VERSION 5.7 ;
  NOWIREEXTENSIONATPIN ON ;
  DIVIDERCHAR "/" ;
  BUSBITCHARS "[]" ;
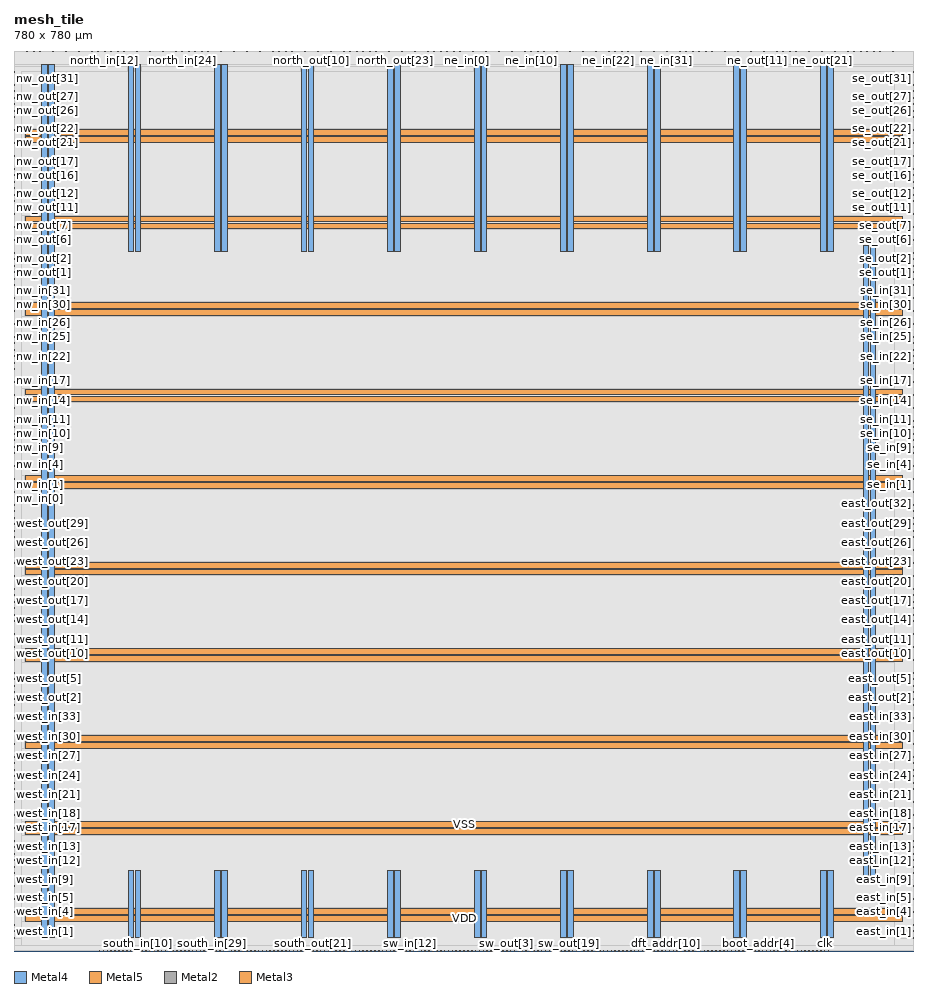
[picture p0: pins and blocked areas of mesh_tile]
MACRO mesh_tile
  CLASS BLOCK ;
  FOREIGN mesh_tile ;
  ORIGIN 0.000 0.000 ;
  SIZE 780.000 BY 780.000 ;
  PIN VDD
    DIRECTION INOUT ;
    USE POWER ;
    PORT
      LAYER Metal4 ;
        RECT 23.900 11.460 28.900 768.620 ;
    END
    PORT
      LAYER Metal4 ;
        RECT 98.900 11.460 103.900 69.720 ;
    END
    PORT
      LAYER Metal4 ;
        RECT 98.900 606.090 103.900 768.620 ;
    END
    PORT
      LAYER Metal4 ;
        RECT 173.900 11.460 178.900 69.720 ;
    END
    PORT
      LAYER Metal4 ;
        RECT 173.900 606.090 178.900 768.620 ;
    END
    PORT
      LAYER Metal4 ;
        RECT 248.900 11.460 253.900 69.720 ;
    END
    PORT
      LAYER Metal4 ;
        RECT 248.900 606.090 253.900 768.620 ;
    END
    PORT
      LAYER Metal4 ;
        RECT 323.900 11.460 328.900 69.720 ;
    END
    PORT
      LAYER Metal4 ;
        RECT 323.900 606.090 328.900 768.620 ;
    END
    PORT
      LAYER Metal4 ;
        RECT 398.900 11.460 403.900 69.720 ;
    END
    PORT
      LAYER Metal4 ;
        RECT 398.900 606.090 403.900 768.620 ;
    END
    PORT
      LAYER Metal4 ;
        RECT 473.900 11.460 478.900 69.720 ;
    END
    PORT
      LAYER Metal4 ;
        RECT 473.900 606.090 478.900 768.620 ;
    END
    PORT
      LAYER Metal4 ;
        RECT 548.900 11.460 553.900 69.720 ;
    END
    PORT
      LAYER Metal4 ;
        RECT 548.900 606.090 553.900 768.620 ;
    END
    PORT
      LAYER Metal4 ;
        RECT 623.900 11.460 628.900 69.720 ;
    END
    PORT
      LAYER Metal4 ;
        RECT 623.900 606.090 628.900 768.620 ;
    END
    PORT
      LAYER Metal4 ;
        RECT 698.900 11.460 703.900 69.720 ;
    END
    PORT
      LAYER Metal4 ;
        RECT 698.900 606.090 703.900 768.620 ;
    END
    PORT
      LAYER Metal5 ;
        RECT 10.080 25.910 770.000 30.910 ;
    END
    PORT
      LAYER Metal5 ;
        RECT 10.080 100.910 770.000 105.910 ;
    END
    PORT
      LAYER Metal5 ;
        RECT 10.080 175.910 770.000 180.910 ;
    END
    PORT
      LAYER Metal5 ;
        RECT 10.080 250.910 770.000 255.910 ;
    END
    PORT
      LAYER Metal5 ;
        RECT 10.080 325.910 770.000 330.910 ;
    END
    PORT
      LAYER Metal5 ;
        RECT 10.080 400.910 770.000 405.910 ;
    END
    PORT
      LAYER Metal5 ;
        RECT 10.080 475.910 770.000 480.910 ;
    END
    PORT
      LAYER Metal5 ;
        RECT 10.080 550.910 770.000 555.910 ;
    END
    PORT
      LAYER Metal5 ;
        RECT 10.080 625.910 770.000 630.910 ;
    END
    PORT
      LAYER Metal5 ;
        RECT 10.080 700.910 770.000 705.910 ;
    END
    PORT
      LAYER Metal4 ;
        RECT 735.860 62.420 740.860 611.820 ;
    END
  END VDD
  PIN VSS
    DIRECTION INOUT ;
    USE GROUND ;
    PORT
      LAYER Metal4 ;
        RECT 29.900 11.460 34.900 768.620 ;
    END
    PORT
      LAYER Metal4 ;
        RECT 104.900 11.460 109.900 69.720 ;
    END
    PORT
      LAYER Metal4 ;
        RECT 104.900 606.090 109.900 768.620 ;
    END
    PORT
      LAYER Metal4 ;
        RECT 179.900 11.460 184.900 69.720 ;
    END
    PORT
      LAYER Metal4 ;
        RECT 179.900 606.090 184.900 768.620 ;
    END
    PORT
      LAYER Metal4 ;
        RECT 254.900 11.460 259.900 69.720 ;
    END
    PORT
      LAYER Metal4 ;
        RECT 254.900 606.090 259.900 768.620 ;
    END
    PORT
      LAYER Metal4 ;
        RECT 329.900 11.460 334.900 69.720 ;
    END
    PORT
      LAYER Metal4 ;
        RECT 329.900 606.090 334.900 768.620 ;
    END
    PORT
      LAYER Metal4 ;
        RECT 404.900 11.460 409.900 69.720 ;
    END
    PORT
      LAYER Metal4 ;
        RECT 404.900 606.090 409.900 768.620 ;
    END
    PORT
      LAYER Metal4 ;
        RECT 479.900 11.460 484.900 69.720 ;
    END
    PORT
      LAYER Metal4 ;
        RECT 479.900 606.090 484.900 768.620 ;
    END
    PORT
      LAYER Metal4 ;
        RECT 554.900 11.460 559.900 69.720 ;
    END
    PORT
      LAYER Metal4 ;
        RECT 554.900 606.090 559.900 768.620 ;
    END
    PORT
      LAYER Metal4 ;
        RECT 629.900 11.460 634.900 69.720 ;
    END
    PORT
      LAYER Metal4 ;
        RECT 629.900 606.090 634.900 768.620 ;
    END
    PORT
      LAYER Metal4 ;
        RECT 704.900 11.460 709.900 69.720 ;
    END
    PORT
      LAYER Metal4 ;
        RECT 704.900 606.090 709.900 768.620 ;
    END
    PORT
      LAYER Metal5 ;
        RECT 10.080 31.910 770.000 36.910 ;
    END
    PORT
      LAYER Metal5 ;
        RECT 10.080 106.910 770.000 111.910 ;
    END
    PORT
      LAYER Metal5 ;
        RECT 10.080 181.910 770.000 186.910 ;
    END
    PORT
      LAYER Metal5 ;
        RECT 10.080 256.910 770.000 261.910 ;
    END
    PORT
      LAYER Metal5 ;
        RECT 10.080 331.910 770.000 336.910 ;
    END
    PORT
      LAYER Metal5 ;
        RECT 10.080 406.910 770.000 411.910 ;
    END
    PORT
      LAYER Metal5 ;
        RECT 10.080 481.910 770.000 486.910 ;
    END
    PORT
      LAYER Metal5 ;
        RECT 10.080 556.910 770.000 561.910 ;
    END
    PORT
      LAYER Metal5 ;
        RECT 10.080 631.910 770.000 636.910 ;
    END
    PORT
      LAYER Metal5 ;
        RECT 10.080 706.910 770.000 711.910 ;
    END
    PORT
      LAYER Metal4 ;
        RECT 742.020 62.420 747.020 611.820 ;
    END
  END VSS
  PIN boot_addr[0]
    DIRECTION INPUT ;
    USE SIGNAL ;
    ANTENNAGATEAREA 2.665600 ;
    PORT
      LAYER Metal2 ;
        RECT 631.680 0.000 632.240 0.560 ;
    END
  END boot_addr[0]
  PIN boot_addr[10]
    DIRECTION INPUT ;
    USE SIGNAL ;
    ANTENNAGATEAREA 2.665600 ;
    PORT
      LAYER Metal2 ;
        RECT 665.280 0.000 665.840 0.560 ;
    END
  END boot_addr[10]
  PIN boot_addr[1]
    DIRECTION INPUT ;
    USE SIGNAL ;
    ANTENNAGATEAREA 2.665600 ;
    PORT
      LAYER Metal2 ;
        RECT 635.040 0.000 635.600 0.560 ;
    END
  END boot_addr[1]
  PIN boot_addr[2]
    DIRECTION INPUT ;
    USE SIGNAL ;
    ANTENNAGATEAREA 2.665600 ;
    PORT
      LAYER Metal2 ;
        RECT 638.400 0.000 638.960 0.560 ;
    END
  END boot_addr[2]
  PIN boot_addr[3]
    DIRECTION INPUT ;
    USE SIGNAL ;
    ANTENNAGATEAREA 2.665600 ;
    PORT
      LAYER Metal2 ;
        RECT 641.760 0.000 642.320 0.560 ;
    END
  END boot_addr[3]
  PIN boot_addr[4]
    DIRECTION INPUT ;
    USE SIGNAL ;
    ANTENNAGATEAREA 2.665600 ;
    PORT
      LAYER Metal2 ;
        RECT 645.120 0.000 645.680 0.560 ;
    END
  END boot_addr[4]
  PIN boot_addr[5]
    DIRECTION INPUT ;
    USE SIGNAL ;
    ANTENNAGATEAREA 2.665600 ;
    PORT
      LAYER Metal2 ;
        RECT 648.480 0.000 649.040 0.560 ;
    END
  END boot_addr[5]
  PIN boot_addr[6]
    DIRECTION INPUT ;
    USE SIGNAL ;
    ANTENNAGATEAREA 2.665600 ;
    PORT
      LAYER Metal2 ;
        RECT 651.840 0.000 652.400 0.560 ;
    END
  END boot_addr[6]
  PIN boot_addr[7]
    DIRECTION INPUT ;
    USE SIGNAL ;
    ANTENNAGATEAREA 2.665600 ;
    PORT
      LAYER Metal2 ;
        RECT 655.200 0.000 655.760 0.560 ;
    END
  END boot_addr[7]
  PIN boot_addr[8]
    DIRECTION INPUT ;
    USE SIGNAL ;
    ANTENNAGATEAREA 2.665600 ;
    PORT
      LAYER Metal2 ;
        RECT 658.560 0.000 659.120 0.560 ;
    END
  END boot_addr[8]
  PIN boot_addr[9]
    DIRECTION INPUT ;
    USE SIGNAL ;
    ANTENNAGATEAREA 2.665600 ;
    PORT
      LAYER Metal2 ;
        RECT 661.920 0.000 662.480 0.560 ;
    END
  END boot_addr[9]
  PIN boot_data[0]
    DIRECTION INPUT ;
    USE SIGNAL ;
    ANTENNAGATEAREA 2.665600 ;
    PORT
      LAYER Metal2 ;
        RECT 668.640 0.000 669.200 0.560 ;
    END
  END boot_data[0]
  PIN boot_data[1]
    DIRECTION INPUT ;
    USE SIGNAL ;
    ANTENNAGATEAREA 2.665600 ;
    PORT
      LAYER Metal2 ;
        RECT 672.000 0.000 672.560 0.560 ;
    END
  END boot_data[1]
  PIN boot_data[2]
    DIRECTION INPUT ;
    USE SIGNAL ;
    ANTENNAGATEAREA 2.665600 ;
    PORT
      LAYER Metal2 ;
        RECT 675.360 0.000 675.920 0.560 ;
    END
  END boot_data[2]
  PIN boot_data[3]
    DIRECTION INPUT ;
    USE SIGNAL ;
    ANTENNAGATEAREA 2.665600 ;
    PORT
      LAYER Metal2 ;
        RECT 678.720 0.000 679.280 0.560 ;
    END
  END boot_data[3]
  PIN boot_data[4]
    DIRECTION INPUT ;
    USE SIGNAL ;
    ANTENNAGATEAREA 2.665600 ;
    PORT
      LAYER Metal2 ;
        RECT 682.080 0.000 682.640 0.560 ;
    END
  END boot_data[4]
  PIN boot_data[5]
    DIRECTION INPUT ;
    USE SIGNAL ;
    ANTENNAGATEAREA 2.665600 ;
    PORT
      LAYER Metal2 ;
        RECT 685.440 0.000 686.000 0.560 ;
    END
  END boot_data[5]
  PIN boot_data[6]
    DIRECTION INPUT ;
    USE SIGNAL ;
    ANTENNAGATEAREA 2.665600 ;
    PORT
      LAYER Metal2 ;
        RECT 688.800 0.000 689.360 0.560 ;
    END
  END boot_data[6]
  PIN boot_data[7]
    DIRECTION INPUT ;
    USE SIGNAL ;
    ANTENNAGATEAREA 2.665600 ;
    PORT
      LAYER Metal2 ;
        RECT 692.160 0.000 692.720 0.560 ;
    END
  END boot_data[7]
  PIN boot_mode
    DIRECTION INPUT ;
    USE SIGNAL ;
    ANTENNAGATEAREA 2.665600 ;
    PORT
      LAYER Metal2 ;
        RECT 695.520 0.000 696.080 0.560 ;
    END
  END boot_mode
  PIN boot_wen
    DIRECTION INPUT ;
    USE SIGNAL ;
    ANTENNAGATEAREA 2.665600 ;
    PORT
      LAYER Metal2 ;
        RECT 698.880 0.000 699.440 0.560 ;
    END
  END boot_wen
  PIN clk
    DIRECTION INPUT ;
    USE SIGNAL ;
    ANTENNAGATEAREA 4.704000 ;
    PORT
      LAYER Metal2 ;
        RECT 702.240 0.000 702.800 0.560 ;
    END
  END clk
  PIN dft_addr[0]
    DIRECTION INPUT ;
    USE SIGNAL ;
    ANTENNAGATEAREA 2.665600 ;
    PORT
      LAYER Metal2 ;
        RECT 530.880 0.000 531.440 0.560 ;
    END
  END dft_addr[0]
  PIN dft_addr[10]
    DIRECTION INPUT ;
    USE SIGNAL ;
    ANTENNAGATEAREA 2.665600 ;
    PORT
      LAYER Metal2 ;
        RECT 564.480 0.000 565.040 0.560 ;
    END
  END dft_addr[10]
  PIN dft_addr[1]
    DIRECTION INPUT ;
    USE SIGNAL ;
    ANTENNAGATEAREA 2.665600 ;
    PORT
      LAYER Metal2 ;
        RECT 534.240 0.000 534.800 0.560 ;
    END
  END dft_addr[1]
  PIN dft_addr[2]
    DIRECTION INPUT ;
    USE SIGNAL ;
    ANTENNAGATEAREA 2.665600 ;
    PORT
      LAYER Metal2 ;
        RECT 537.600 0.000 538.160 0.560 ;
    END
  END dft_addr[2]
  PIN dft_addr[3]
    DIRECTION INPUT ;
    USE SIGNAL ;
    ANTENNAGATEAREA 2.665600 ;
    PORT
      LAYER Metal2 ;
        RECT 540.960 0.000 541.520 0.560 ;
    END
  END dft_addr[3]
  PIN dft_addr[4]
    DIRECTION INPUT ;
    USE SIGNAL ;
    ANTENNAGATEAREA 2.665600 ;
    PORT
      LAYER Metal2 ;
        RECT 544.320 0.000 544.880 0.560 ;
    END
  END dft_addr[4]
  PIN dft_addr[5]
    DIRECTION INPUT ;
    USE SIGNAL ;
    ANTENNAGATEAREA 2.665600 ;
    PORT
      LAYER Metal2 ;
        RECT 547.680 0.000 548.240 0.560 ;
    END
  END dft_addr[5]
  PIN dft_addr[6]
    DIRECTION INPUT ;
    USE SIGNAL ;
    ANTENNAGATEAREA 2.665600 ;
    PORT
      LAYER Metal2 ;
        RECT 551.040 0.000 551.600 0.560 ;
    END
  END dft_addr[6]
  PIN dft_addr[7]
    DIRECTION INPUT ;
    USE SIGNAL ;
    ANTENNAGATEAREA 2.665600 ;
    PORT
      LAYER Metal2 ;
        RECT 554.400 0.000 554.960 0.560 ;
    END
  END dft_addr[7]
  PIN dft_addr[8]
    DIRECTION INPUT ;
    USE SIGNAL ;
    ANTENNAGATEAREA 2.665600 ;
    PORT
      LAYER Metal2 ;
        RECT 557.760 0.000 558.320 0.560 ;
    END
  END dft_addr[8]
  PIN dft_addr[9]
    DIRECTION INPUT ;
    USE SIGNAL ;
    ANTENNAGATEAREA 2.665600 ;
    PORT
      LAYER Metal2 ;
        RECT 561.120 0.000 561.680 0.560 ;
    END
  END dft_addr[9]
  PIN dft_ce
    DIRECTION INPUT ;
    USE SIGNAL ;
    ANTENNAGATEAREA 2.665600 ;
    PORT
      LAYER Metal2 ;
        RECT 567.840 0.000 568.400 0.560 ;
    END
  END dft_ce
  PIN dft_mode
    DIRECTION INPUT ;
    USE SIGNAL ;
    ANTENNAGATEAREA 2.665600 ;
    PORT
      LAYER Metal2 ;
        RECT 571.200 0.000 571.760 0.560 ;
    END
  END dft_mode
  PIN dft_rdata[0]
    DIRECTION OUTPUT ;
    USE SIGNAL ;
    ANTENNADIFFAREA 7.461300 ;
    PORT
      LAYER Metal2 ;
        RECT 574.560 0.000 575.120 0.560 ;
    END
  END dft_rdata[0]
  PIN dft_rdata[1]
    DIRECTION OUTPUT ;
    USE SIGNAL ;
    ANTENNADIFFAREA 7.461300 ;
    PORT
      LAYER Metal2 ;
        RECT 577.920 0.000 578.480 0.560 ;
    END
  END dft_rdata[1]
  PIN dft_rdata[2]
    DIRECTION OUTPUT ;
    USE SIGNAL ;
    ANTENNADIFFAREA 7.461300 ;
    PORT
      LAYER Metal2 ;
        RECT 581.280 0.000 581.840 0.560 ;
    END
  END dft_rdata[2]
  PIN dft_rdata[3]
    DIRECTION OUTPUT ;
    USE SIGNAL ;
    ANTENNADIFFAREA 7.461300 ;
    PORT
      LAYER Metal2 ;
        RECT 584.640 0.000 585.200 0.560 ;
    END
  END dft_rdata[3]
  PIN dft_rdata[4]
    DIRECTION OUTPUT ;
    USE SIGNAL ;
    ANTENNADIFFAREA 7.461300 ;
    PORT
      LAYER Metal2 ;
        RECT 588.000 0.000 588.560 0.560 ;
    END
  END dft_rdata[4]
  PIN dft_rdata[5]
    DIRECTION OUTPUT ;
    USE SIGNAL ;
    ANTENNADIFFAREA 7.461300 ;
    PORT
      LAYER Metal2 ;
        RECT 591.360 0.000 591.920 0.560 ;
    END
  END dft_rdata[5]
  PIN dft_rdata[6]
    DIRECTION OUTPUT ;
    USE SIGNAL ;
    ANTENNADIFFAREA 7.461300 ;
    PORT
      LAYER Metal2 ;
        RECT 594.720 0.000 595.280 0.560 ;
    END
  END dft_rdata[6]
  PIN dft_rdata[7]
    DIRECTION OUTPUT ;
    USE SIGNAL ;
    ANTENNADIFFAREA 7.461300 ;
    PORT
      LAYER Metal2 ;
        RECT 598.080 0.000 598.640 0.560 ;
    END
  END dft_rdata[7]
  PIN dft_wdata[0]
    DIRECTION INPUT ;
    USE SIGNAL ;
    ANTENNAGATEAREA 2.665600 ;
    PORT
      LAYER Metal2 ;
        RECT 601.440 0.000 602.000 0.560 ;
    END
  END dft_wdata[0]
  PIN dft_wdata[1]
    DIRECTION INPUT ;
    USE SIGNAL ;
    ANTENNAGATEAREA 2.665600 ;
    PORT
      LAYER Metal2 ;
        RECT 604.800 0.000 605.360 0.560 ;
    END
  END dft_wdata[1]
  PIN dft_wdata[2]
    DIRECTION INPUT ;
    USE SIGNAL ;
    ANTENNAGATEAREA 2.665600 ;
    PORT
      LAYER Metal2 ;
        RECT 608.160 0.000 608.720 0.560 ;
    END
  END dft_wdata[2]
  PIN dft_wdata[3]
    DIRECTION INPUT ;
    USE SIGNAL ;
    ANTENNAGATEAREA 2.665600 ;
    PORT
      LAYER Metal2 ;
        RECT 611.520 0.000 612.080 0.560 ;
    END
  END dft_wdata[3]
  PIN dft_wdata[4]
    DIRECTION INPUT ;
    USE SIGNAL ;
    ANTENNAGATEAREA 2.665600 ;
    PORT
      LAYER Metal2 ;
        RECT 614.880 0.000 615.440 0.560 ;
    END
  END dft_wdata[4]
  PIN dft_wdata[5]
    DIRECTION INPUT ;
    USE SIGNAL ;
    ANTENNAGATEAREA 2.665600 ;
    PORT
      LAYER Metal2 ;
        RECT 618.240 0.000 618.800 0.560 ;
    END
  END dft_wdata[5]
  PIN dft_wdata[6]
    DIRECTION INPUT ;
    USE SIGNAL ;
    ANTENNAGATEAREA 2.665600 ;
    PORT
      LAYER Metal2 ;
        RECT 621.600 0.000 622.160 0.560 ;
    END
  END dft_wdata[6]
  PIN dft_wdata[7]
    DIRECTION INPUT ;
    USE SIGNAL ;
    ANTENNAGATEAREA 2.665600 ;
    PORT
      LAYER Metal2 ;
        RECT 624.960 0.000 625.520 0.560 ;
    END
  END dft_wdata[7]
  PIN dft_we
    DIRECTION INPUT ;
    USE SIGNAL ;
    ANTENNAGATEAREA 2.665600 ;
    PORT
      LAYER Metal2 ;
        RECT 628.320 0.000 628.880 0.560 ;
    END
  END dft_we
  PIN east_in[0]
    DIRECTION INPUT ;
    USE SIGNAL ;
    ANTENNAGATEAREA 2.665600 ;
    PORT
      LAYER Metal3 ;
        RECT 779.440 11.200 780.000 11.760 ;
    END
  END east_in[0]
  PIN east_in[10]
    DIRECTION INPUT ;
    USE SIGNAL ;
    ANTENNAGATEAREA 2.665600 ;
    PORT
      LAYER Metal3 ;
        RECT 779.440 67.200 780.000 67.760 ;
    END
  END east_in[10]
  PIN east_in[11]
    DIRECTION INPUT ;
    USE SIGNAL ;
    ANTENNAGATEAREA 2.665600 ;
    PORT
      LAYER Metal3 ;
        RECT 779.440 72.800 780.000 73.360 ;
    END
  END east_in[11]
  PIN east_in[12]
    DIRECTION INPUT ;
    USE SIGNAL ;
    ANTENNAGATEAREA 2.665600 ;
    PORT
      LAYER Metal3 ;
        RECT 779.440 78.400 780.000 78.960 ;
    END
  END east_in[12]
  PIN east_in[13]
    DIRECTION INPUT ;
    USE SIGNAL ;
    ANTENNAGATEAREA 2.665600 ;
    PORT
      LAYER Metal3 ;
        RECT 779.440 84.000 780.000 84.560 ;
    END
  END east_in[13]
  PIN east_in[14]
    DIRECTION INPUT ;
    USE SIGNAL ;
    ANTENNAGATEAREA 2.665600 ;
    PORT
      LAYER Metal3 ;
        RECT 779.440 89.600 780.000 90.160 ;
    END
  END east_in[14]
  PIN east_in[15]
    DIRECTION INPUT ;
    USE SIGNAL ;
    ANTENNAGATEAREA 2.665600 ;
    PORT
      LAYER Metal3 ;
        RECT 779.440 95.200 780.000 95.760 ;
    END
  END east_in[15]
  PIN east_in[16]
    DIRECTION INPUT ;
    USE SIGNAL ;
    ANTENNAGATEAREA 2.665600 ;
    PORT
      LAYER Metal3 ;
        RECT 779.440 100.800 780.000 101.360 ;
    END
  END east_in[16]
  PIN east_in[17]
    DIRECTION INPUT ;
    USE SIGNAL ;
    ANTENNAGATEAREA 2.665600 ;
    PORT
      LAYER Metal3 ;
        RECT 779.440 106.400 780.000 106.960 ;
    END
  END east_in[17]
  PIN east_in[18]
    DIRECTION INPUT ;
    USE SIGNAL ;
    ANTENNAGATEAREA 2.665600 ;
    PORT
      LAYER Metal3 ;
        RECT 779.440 112.000 780.000 112.560 ;
    END
  END east_in[18]
  PIN east_in[19]
    DIRECTION INPUT ;
    USE SIGNAL ;
    ANTENNAGATEAREA 2.665600 ;
    PORT
      LAYER Metal3 ;
        RECT 779.440 117.600 780.000 118.160 ;
    END
  END east_in[19]
  PIN east_in[1]
    DIRECTION INPUT ;
    USE SIGNAL ;
    ANTENNAGATEAREA 2.665600 ;
    PORT
      LAYER Metal3 ;
        RECT 779.440 16.800 780.000 17.360 ;
    END
  END east_in[1]
  PIN east_in[20]
    DIRECTION INPUT ;
    USE SIGNAL ;
    ANTENNAGATEAREA 2.665600 ;
    PORT
      LAYER Metal3 ;
        RECT 779.440 123.200 780.000 123.760 ;
    END
  END east_in[20]
  PIN east_in[21]
    DIRECTION INPUT ;
    USE SIGNAL ;
    ANTENNAGATEAREA 2.665600 ;
    PORT
      LAYER Metal3 ;
        RECT 779.440 128.800 780.000 129.360 ;
    END
  END east_in[21]
  PIN east_in[22]
    DIRECTION INPUT ;
    USE SIGNAL ;
    ANTENNAGATEAREA 2.665600 ;
    PORT
      LAYER Metal3 ;
        RECT 779.440 134.400 780.000 134.960 ;
    END
  END east_in[22]
  PIN east_in[23]
    DIRECTION INPUT ;
    USE SIGNAL ;
    ANTENNAGATEAREA 2.665600 ;
    PORT
      LAYER Metal3 ;
        RECT 779.440 140.000 780.000 140.560 ;
    END
  END east_in[23]
  PIN east_in[24]
    DIRECTION INPUT ;
    USE SIGNAL ;
    ANTENNAGATEAREA 2.665600 ;
    PORT
      LAYER Metal3 ;
        RECT 779.440 145.600 780.000 146.160 ;
    END
  END east_in[24]
  PIN east_in[25]
    DIRECTION INPUT ;
    USE SIGNAL ;
    ANTENNAGATEAREA 2.665600 ;
    PORT
      LAYER Metal3 ;
        RECT 779.440 151.200 780.000 151.760 ;
    END
  END east_in[25]
  PIN east_in[26]
    DIRECTION INPUT ;
    USE SIGNAL ;
    ANTENNAGATEAREA 2.665600 ;
    PORT
      LAYER Metal3 ;
        RECT 779.440 156.800 780.000 157.360 ;
    END
  END east_in[26]
  PIN east_in[27]
    DIRECTION INPUT ;
    USE SIGNAL ;
    ANTENNAGATEAREA 2.665600 ;
    PORT
      LAYER Metal3 ;
        RECT 779.440 162.400 780.000 162.960 ;
    END
  END east_in[27]
  PIN east_in[28]
    DIRECTION INPUT ;
    USE SIGNAL ;
    ANTENNAGATEAREA 2.665600 ;
    PORT
      LAYER Metal3 ;
        RECT 779.440 168.000 780.000 168.560 ;
    END
  END east_in[28]
  PIN east_in[29]
    DIRECTION INPUT ;
    USE SIGNAL ;
    ANTENNAGATEAREA 2.665600 ;
    PORT
      LAYER Metal3 ;
        RECT 779.440 173.600 780.000 174.160 ;
    END
  END east_in[29]
  PIN east_in[2]
    DIRECTION INPUT ;
    USE SIGNAL ;
    ANTENNAGATEAREA 2.665600 ;
    PORT
      LAYER Metal3 ;
        RECT 779.440 22.400 780.000 22.960 ;
    END
  END east_in[2]
  PIN east_in[30]
    DIRECTION INPUT ;
    USE SIGNAL ;
    ANTENNAGATEAREA 2.665600 ;
    PORT
      LAYER Metal3 ;
        RECT 779.440 179.200 780.000 179.760 ;
    END
  END east_in[30]
  PIN east_in[31]
    DIRECTION INPUT ;
    USE SIGNAL ;
    ANTENNAGATEAREA 2.665600 ;
    PORT
      LAYER Metal3 ;
        RECT 779.440 184.800 780.000 185.360 ;
    END
  END east_in[31]
  PIN east_in[32]
    DIRECTION INPUT ;
    USE SIGNAL ;
    ANTENNAGATEAREA 2.665600 ;
    PORT
      LAYER Metal3 ;
        RECT 779.440 190.400 780.000 190.960 ;
    END
  END east_in[32]
  PIN east_in[33]
    DIRECTION INPUT ;
    USE SIGNAL ;
    ANTENNAGATEAREA 2.665600 ;
    PORT
      LAYER Metal3 ;
        RECT 779.440 196.000 780.000 196.560 ;
    END
  END east_in[33]
  PIN east_in[3]
    DIRECTION INPUT ;
    USE SIGNAL ;
    ANTENNAGATEAREA 2.665600 ;
    PORT
      LAYER Metal3 ;
        RECT 779.440 28.000 780.000 28.560 ;
    END
  END east_in[3]
  PIN east_in[4]
    DIRECTION INPUT ;
    USE SIGNAL ;
    ANTENNAGATEAREA 2.665600 ;
    PORT
      LAYER Metal3 ;
        RECT 779.440 33.600 780.000 34.160 ;
    END
  END east_in[4]
  PIN east_in[5]
    DIRECTION INPUT ;
    USE SIGNAL ;
    ANTENNAGATEAREA 2.665600 ;
    PORT
      LAYER Metal3 ;
        RECT 779.440 39.200 780.000 39.760 ;
    END
  END east_in[5]
  PIN east_in[6]
    DIRECTION INPUT ;
    USE SIGNAL ;
    ANTENNAGATEAREA 2.665600 ;
    PORT
      LAYER Metal3 ;
        RECT 779.440 44.800 780.000 45.360 ;
    END
  END east_in[6]
  PIN east_in[7]
    DIRECTION INPUT ;
    USE SIGNAL ;
    ANTENNAGATEAREA 2.665600 ;
    PORT
      LAYER Metal3 ;
        RECT 779.440 50.400 780.000 50.960 ;
    END
  END east_in[7]
  PIN east_in[8]
    DIRECTION INPUT ;
    USE SIGNAL ;
    ANTENNAGATEAREA 2.665600 ;
    PORT
      LAYER Metal3 ;
        RECT 779.440 56.000 780.000 56.560 ;
    END
  END east_in[8]
  PIN east_in[9]
    DIRECTION INPUT ;
    USE SIGNAL ;
    ANTENNAGATEAREA 2.665600 ;
    PORT
      LAYER Metal3 ;
        RECT 779.440 61.600 780.000 62.160 ;
    END
  END east_in[9]
  PIN east_out[0]
    DIRECTION OUTPUT ;
    USE SIGNAL ;
    ANTENNADIFFAREA 7.461300 ;
    PORT
      LAYER Metal3 ;
        RECT 779.440 201.600 780.000 202.160 ;
    END
  END east_out[0]
  PIN east_out[10]
    DIRECTION OUTPUT ;
    USE SIGNAL ;
    ANTENNADIFFAREA 7.461300 ;
    PORT
      LAYER Metal3 ;
        RECT 779.440 257.600 780.000 258.160 ;
    END
  END east_out[10]
  PIN east_out[11]
    DIRECTION OUTPUT ;
    USE SIGNAL ;
    ANTENNADIFFAREA 7.461300 ;
    PORT
      LAYER Metal3 ;
        RECT 779.440 263.200 780.000 263.760 ;
    END
  END east_out[11]
  PIN east_out[12]
    DIRECTION OUTPUT ;
    USE SIGNAL ;
    ANTENNADIFFAREA 7.461300 ;
    PORT
      LAYER Metal3 ;
        RECT 779.440 268.800 780.000 269.360 ;
    END
  END east_out[12]
  PIN east_out[13]
    DIRECTION OUTPUT ;
    USE SIGNAL ;
    ANTENNADIFFAREA 7.461300 ;
    PORT
      LAYER Metal3 ;
        RECT 779.440 274.400 780.000 274.960 ;
    END
  END east_out[13]
  PIN east_out[14]
    DIRECTION OUTPUT ;
    USE SIGNAL ;
    ANTENNADIFFAREA 7.461300 ;
    PORT
      LAYER Metal3 ;
        RECT 779.440 280.000 780.000 280.560 ;
    END
  END east_out[14]
  PIN east_out[15]
    DIRECTION OUTPUT ;
    USE SIGNAL ;
    ANTENNADIFFAREA 7.461300 ;
    PORT
      LAYER Metal3 ;
        RECT 779.440 285.600 780.000 286.160 ;
    END
  END east_out[15]
  PIN east_out[16]
    DIRECTION OUTPUT ;
    USE SIGNAL ;
    ANTENNADIFFAREA 7.461300 ;
    PORT
      LAYER Metal3 ;
        RECT 779.440 291.200 780.000 291.760 ;
    END
  END east_out[16]
  PIN east_out[17]
    DIRECTION OUTPUT ;
    USE SIGNAL ;
    ANTENNADIFFAREA 7.461300 ;
    PORT
      LAYER Metal3 ;
        RECT 779.440 296.800 780.000 297.360 ;
    END
  END east_out[17]
  PIN east_out[18]
    DIRECTION OUTPUT ;
    USE SIGNAL ;
    ANTENNADIFFAREA 7.461300 ;
    PORT
      LAYER Metal3 ;
        RECT 779.440 302.400 780.000 302.960 ;
    END
  END east_out[18]
  PIN east_out[19]
    DIRECTION OUTPUT ;
    USE SIGNAL ;
    ANTENNADIFFAREA 7.461300 ;
    PORT
      LAYER Metal3 ;
        RECT 779.440 308.000 780.000 308.560 ;
    END
  END east_out[19]
  PIN east_out[1]
    DIRECTION OUTPUT ;
    USE SIGNAL ;
    ANTENNADIFFAREA 7.461300 ;
    PORT
      LAYER Metal3 ;
        RECT 779.440 207.200 780.000 207.760 ;
    END
  END east_out[1]
  PIN east_out[20]
    DIRECTION OUTPUT ;
    USE SIGNAL ;
    ANTENNADIFFAREA 7.461300 ;
    PORT
      LAYER Metal3 ;
        RECT 779.440 313.600 780.000 314.160 ;
    END
  END east_out[20]
  PIN east_out[21]
    DIRECTION OUTPUT ;
    USE SIGNAL ;
    ANTENNADIFFAREA 7.461300 ;
    PORT
      LAYER Metal3 ;
        RECT 779.440 319.200 780.000 319.760 ;
    END
  END east_out[21]
  PIN east_out[22]
    DIRECTION OUTPUT ;
    USE SIGNAL ;
    ANTENNADIFFAREA 7.461300 ;
    PORT
      LAYER Metal3 ;
        RECT 779.440 324.800 780.000 325.360 ;
    END
  END east_out[22]
  PIN east_out[23]
    DIRECTION OUTPUT ;
    USE SIGNAL ;
    ANTENNADIFFAREA 7.461300 ;
    PORT
      LAYER Metal3 ;
        RECT 779.440 330.400 780.000 330.960 ;
    END
  END east_out[23]
  PIN east_out[24]
    DIRECTION OUTPUT ;
    USE SIGNAL ;
    ANTENNADIFFAREA 7.461300 ;
    PORT
      LAYER Metal3 ;
        RECT 779.440 336.000 780.000 336.560 ;
    END
  END east_out[24]
  PIN east_out[25]
    DIRECTION OUTPUT ;
    USE SIGNAL ;
    ANTENNADIFFAREA 7.461300 ;
    PORT
      LAYER Metal3 ;
        RECT 779.440 341.600 780.000 342.160 ;
    END
  END east_out[25]
  PIN east_out[26]
    DIRECTION OUTPUT ;
    USE SIGNAL ;
    ANTENNADIFFAREA 7.461300 ;
    PORT
      LAYER Metal3 ;
        RECT 779.440 347.200 780.000 347.760 ;
    END
  END east_out[26]
  PIN east_out[27]
    DIRECTION OUTPUT ;
    USE SIGNAL ;
    ANTENNADIFFAREA 7.461300 ;
    PORT
      LAYER Metal3 ;
        RECT 779.440 352.800 780.000 353.360 ;
    END
  END east_out[27]
  PIN east_out[28]
    DIRECTION OUTPUT ;
    USE SIGNAL ;
    ANTENNADIFFAREA 7.461300 ;
    PORT
      LAYER Metal3 ;
        RECT 779.440 358.400 780.000 358.960 ;
    END
  END east_out[28]
  PIN east_out[29]
    DIRECTION OUTPUT ;
    USE SIGNAL ;
    ANTENNADIFFAREA 7.461300 ;
    PORT
      LAYER Metal3 ;
        RECT 779.440 364.000 780.000 364.560 ;
    END
  END east_out[29]
  PIN east_out[2]
    DIRECTION OUTPUT ;
    USE SIGNAL ;
    ANTENNADIFFAREA 7.461300 ;
    PORT
      LAYER Metal3 ;
        RECT 779.440 212.800 780.000 213.360 ;
    END
  END east_out[2]
  PIN east_out[30]
    DIRECTION OUTPUT ;
    USE SIGNAL ;
    ANTENNADIFFAREA 7.461300 ;
    PORT
      LAYER Metal3 ;
        RECT 779.440 369.600 780.000 370.160 ;
    END
  END east_out[30]
  PIN east_out[31]
    DIRECTION OUTPUT ;
    USE SIGNAL ;
    ANTENNADIFFAREA 7.461300 ;
    PORT
      LAYER Metal3 ;
        RECT 779.440 375.200 780.000 375.760 ;
    END
  END east_out[31]
  PIN east_out[32]
    DIRECTION OUTPUT ;
    USE SIGNAL ;
    ANTENNADIFFAREA 7.461300 ;
    PORT
      LAYER Metal3 ;
        RECT 779.440 380.800 780.000 381.360 ;
    END
  END east_out[32]
  PIN east_out[33]
    DIRECTION OUTPUT ;
    USE SIGNAL ;
    ANTENNADIFFAREA 7.461300 ;
    PORT
      LAYER Metal3 ;
        RECT 779.440 386.400 780.000 386.960 ;
    END
  END east_out[33]
  PIN east_out[3]
    DIRECTION OUTPUT ;
    USE SIGNAL ;
    ANTENNADIFFAREA 7.461300 ;
    PORT
      LAYER Metal3 ;
        RECT 779.440 218.400 780.000 218.960 ;
    END
  END east_out[3]
  PIN east_out[4]
    DIRECTION OUTPUT ;
    USE SIGNAL ;
    ANTENNADIFFAREA 7.461300 ;
    PORT
      LAYER Metal3 ;
        RECT 779.440 224.000 780.000 224.560 ;
    END
  END east_out[4]
  PIN east_out[5]
    DIRECTION OUTPUT ;
    USE SIGNAL ;
    ANTENNADIFFAREA 7.461300 ;
    PORT
      LAYER Metal3 ;
        RECT 779.440 229.600 780.000 230.160 ;
    END
  END east_out[5]
  PIN east_out[6]
    DIRECTION OUTPUT ;
    USE SIGNAL ;
    ANTENNADIFFAREA 7.461300 ;
    PORT
      LAYER Metal3 ;
        RECT 779.440 235.200 780.000 235.760 ;
    END
  END east_out[6]
  PIN east_out[7]
    DIRECTION OUTPUT ;
    USE SIGNAL ;
    ANTENNADIFFAREA 7.461300 ;
    PORT
      LAYER Metal3 ;
        RECT 779.440 240.800 780.000 241.360 ;
    END
  END east_out[7]
  PIN east_out[8]
    DIRECTION OUTPUT ;
    USE SIGNAL ;
    ANTENNADIFFAREA 7.461300 ;
    PORT
      LAYER Metal3 ;
        RECT 779.440 246.400 780.000 246.960 ;
    END
  END east_out[8]
  PIN east_out[9]
    DIRECTION OUTPUT ;
    USE SIGNAL ;
    ANTENNADIFFAREA 7.461300 ;
    PORT
      LAYER Metal3 ;
        RECT 779.440 252.000 780.000 252.560 ;
    END
  END east_out[9]
  PIN ne_in[0]
    DIRECTION INPUT ;
    USE SIGNAL ;
    ANTENNAGATEAREA 2.665600 ;
    PORT
      LAYER Metal2 ;
        RECT 392.000 779.440 392.560 780.000 ;
    END
  END ne_in[0]
  PIN ne_in[10]
    DIRECTION INPUT ;
    USE SIGNAL ;
    ANTENNAGATEAREA 2.665600 ;
    PORT
      LAYER Metal2 ;
        RECT 448.000 779.440 448.560 780.000 ;
    END
  END ne_in[10]
  PIN ne_in[11]
    DIRECTION INPUT ;
    USE SIGNAL ;
    ANTENNAGATEAREA 2.665600 ;
    PORT
      LAYER Metal2 ;
        RECT 453.600 779.440 454.160 780.000 ;
    END
  END ne_in[11]
  PIN ne_in[12]
    DIRECTION INPUT ;
    USE SIGNAL ;
    ANTENNAGATEAREA 2.665600 ;
    PORT
      LAYER Metal2 ;
        RECT 459.200 779.440 459.760 780.000 ;
    END
  END ne_in[12]
  PIN ne_in[13]
    DIRECTION INPUT ;
    USE SIGNAL ;
    ANTENNAGATEAREA 2.665600 ;
    PORT
      LAYER Metal2 ;
        RECT 464.800 779.440 465.360 780.000 ;
    END
  END ne_in[13]
  PIN ne_in[14]
    DIRECTION INPUT ;
    USE SIGNAL ;
    ANTENNAGATEAREA 2.665600 ;
    PORT
      LAYER Metal2 ;
        RECT 470.400 779.440 470.960 780.000 ;
    END
  END ne_in[14]
  PIN ne_in[15]
    DIRECTION INPUT ;
    USE SIGNAL ;
    ANTENNAGATEAREA 2.665600 ;
    PORT
      LAYER Metal2 ;
        RECT 476.000 779.440 476.560 780.000 ;
    END
  END ne_in[15]
  PIN ne_in[16]
    DIRECTION INPUT ;
    USE SIGNAL ;
    ANTENNAGATEAREA 2.665600 ;
    PORT
      LAYER Metal2 ;
        RECT 481.600 779.440 482.160 780.000 ;
    END
  END ne_in[16]
  PIN ne_in[17]
    DIRECTION INPUT ;
    USE SIGNAL ;
    ANTENNAGATEAREA 2.665600 ;
    PORT
      LAYER Metal2 ;
        RECT 487.200 779.440 487.760 780.000 ;
    END
  END ne_in[17]
  PIN ne_in[18]
    DIRECTION INPUT ;
    USE SIGNAL ;
    ANTENNAGATEAREA 2.665600 ;
    PORT
      LAYER Metal2 ;
        RECT 492.800 779.440 493.360 780.000 ;
    END
  END ne_in[18]
  PIN ne_in[19]
    DIRECTION INPUT ;
    USE SIGNAL ;
    ANTENNAGATEAREA 2.665600 ;
    PORT
      LAYER Metal2 ;
        RECT 498.400 779.440 498.960 780.000 ;
    END
  END ne_in[19]
  PIN ne_in[1]
    DIRECTION INPUT ;
    USE SIGNAL ;
    ANTENNAGATEAREA 2.665600 ;
    PORT
      LAYER Metal2 ;
        RECT 397.600 779.440 398.160 780.000 ;
    END
  END ne_in[1]
  PIN ne_in[20]
    DIRECTION INPUT ;
    USE SIGNAL ;
    ANTENNAGATEAREA 2.665600 ;
    PORT
      LAYER Metal2 ;
        RECT 504.000 779.440 504.560 780.000 ;
    END
  END ne_in[20]
  PIN ne_in[21]
    DIRECTION INPUT ;
    USE SIGNAL ;
    ANTENNAGATEAREA 2.665600 ;
    PORT
      LAYER Metal2 ;
        RECT 509.600 779.440 510.160 780.000 ;
    END
  END ne_in[21]
  PIN ne_in[22]
    DIRECTION INPUT ;
    USE SIGNAL ;
    ANTENNAGATEAREA 2.665600 ;
    PORT
      LAYER Metal2 ;
        RECT 515.200 779.440 515.760 780.000 ;
    END
  END ne_in[22]
  PIN ne_in[23]
    DIRECTION INPUT ;
    USE SIGNAL ;
    ANTENNAGATEAREA 2.665600 ;
    PORT
      LAYER Metal2 ;
        RECT 520.800 779.440 521.360 780.000 ;
    END
  END ne_in[23]
  PIN ne_in[24]
    DIRECTION INPUT ;
    USE SIGNAL ;
    ANTENNAGATEAREA 2.665600 ;
    PORT
      LAYER Metal2 ;
        RECT 526.400 779.440 526.960 780.000 ;
    END
  END ne_in[24]
  PIN ne_in[25]
    DIRECTION INPUT ;
    USE SIGNAL ;
    ANTENNAGATEAREA 2.665600 ;
    PORT
      LAYER Metal2 ;
        RECT 532.000 779.440 532.560 780.000 ;
    END
  END ne_in[25]
  PIN ne_in[26]
    DIRECTION INPUT ;
    USE SIGNAL ;
    ANTENNAGATEAREA 2.665600 ;
    PORT
      LAYER Metal2 ;
        RECT 537.600 779.440 538.160 780.000 ;
    END
  END ne_in[26]
  PIN ne_in[27]
    DIRECTION INPUT ;
    USE SIGNAL ;
    ANTENNAGATEAREA 2.665600 ;
    PORT
      LAYER Metal2 ;
        RECT 543.200 779.440 543.760 780.000 ;
    END
  END ne_in[27]
  PIN ne_in[28]
    DIRECTION INPUT ;
    USE SIGNAL ;
    ANTENNAGATEAREA 2.665600 ;
    PORT
      LAYER Metal2 ;
        RECT 548.800 779.440 549.360 780.000 ;
    END
  END ne_in[28]
  PIN ne_in[29]
    DIRECTION INPUT ;
    USE SIGNAL ;
    ANTENNAGATEAREA 2.665600 ;
    PORT
      LAYER Metal2 ;
        RECT 554.400 779.440 554.960 780.000 ;
    END
  END ne_in[29]
  PIN ne_in[2]
    DIRECTION INPUT ;
    USE SIGNAL ;
    ANTENNAGATEAREA 2.665600 ;
    PORT
      LAYER Metal2 ;
        RECT 403.200 779.440 403.760 780.000 ;
    END
  END ne_in[2]
  PIN ne_in[30]
    DIRECTION INPUT ;
    USE SIGNAL ;
    ANTENNAGATEAREA 2.665600 ;
    PORT
      LAYER Metal2 ;
        RECT 560.000 779.440 560.560 780.000 ;
    END
  END ne_in[30]
  PIN ne_in[31]
    DIRECTION INPUT ;
    USE SIGNAL ;
    ANTENNAGATEAREA 2.665600 ;
    PORT
      LAYER Metal2 ;
        RECT 565.600 779.440 566.160 780.000 ;
    END
  END ne_in[31]
  PIN ne_in[32]
    DIRECTION INPUT ;
    USE SIGNAL ;
    ANTENNAGATEAREA 2.665600 ;
    PORT
      LAYER Metal2 ;
        RECT 571.200 779.440 571.760 780.000 ;
    END
  END ne_in[32]
  PIN ne_in[33]
    DIRECTION INPUT ;
    USE SIGNAL ;
    ANTENNAGATEAREA 2.665600 ;
    PORT
      LAYER Metal2 ;
        RECT 576.800 779.440 577.360 780.000 ;
    END
  END ne_in[33]
  PIN ne_in[3]
    DIRECTION INPUT ;
    USE SIGNAL ;
    ANTENNAGATEAREA 2.665600 ;
    PORT
      LAYER Metal2 ;
        RECT 408.800 779.440 409.360 780.000 ;
    END
  END ne_in[3]
  PIN ne_in[4]
    DIRECTION INPUT ;
    USE SIGNAL ;
    ANTENNAGATEAREA 2.665600 ;
    PORT
      LAYER Metal2 ;
        RECT 414.400 779.440 414.960 780.000 ;
    END
  END ne_in[4]
  PIN ne_in[5]
    DIRECTION INPUT ;
    USE SIGNAL ;
    ANTENNAGATEAREA 2.665600 ;
    PORT
      LAYER Metal2 ;
        RECT 420.000 779.440 420.560 780.000 ;
    END
  END ne_in[5]
  PIN ne_in[6]
    DIRECTION INPUT ;
    USE SIGNAL ;
    ANTENNAGATEAREA 2.665600 ;
    PORT
      LAYER Metal2 ;
        RECT 425.600 779.440 426.160 780.000 ;
    END
  END ne_in[6]
  PIN ne_in[7]
    DIRECTION INPUT ;
    USE SIGNAL ;
    ANTENNAGATEAREA 2.665600 ;
    PORT
      LAYER Metal2 ;
        RECT 431.200 779.440 431.760 780.000 ;
    END
  END ne_in[7]
  PIN ne_in[8]
    DIRECTION INPUT ;
    USE SIGNAL ;
    ANTENNAGATEAREA 2.665600 ;
    PORT
      LAYER Metal2 ;
        RECT 436.800 779.440 437.360 780.000 ;
    END
  END ne_in[8]
  PIN ne_in[9]
    DIRECTION INPUT ;
    USE SIGNAL ;
    ANTENNAGATEAREA 2.665600 ;
    PORT
      LAYER Metal2 ;
        RECT 442.400 779.440 442.960 780.000 ;
    END
  END ne_in[9]
  PIN ne_out[0]
    DIRECTION OUTPUT ;
    USE SIGNAL ;
    ANTENNADIFFAREA 0.440000 ;
    PORT
      LAYER Metal2 ;
        RECT 582.400 779.440 582.960 780.000 ;
    END
  END ne_out[0]
  PIN ne_out[10]
    DIRECTION OUTPUT ;
    USE SIGNAL ;
    ANTENNADIFFAREA 0.440000 ;
    PORT
      LAYER Metal2 ;
        RECT 638.400 779.440 638.960 780.000 ;
    END
  END ne_out[10]
  PIN ne_out[11]
    DIRECTION OUTPUT ;
    USE SIGNAL ;
    ANTENNADIFFAREA 0.440000 ;
    PORT
      LAYER Metal2 ;
        RECT 644.000 779.440 644.560 780.000 ;
    END
  END ne_out[11]
  PIN ne_out[12]
    DIRECTION OUTPUT ;
    USE SIGNAL ;
    ANTENNADIFFAREA 0.440000 ;
    PORT
      LAYER Metal2 ;
        RECT 649.600 779.440 650.160 780.000 ;
    END
  END ne_out[12]
  PIN ne_out[13]
    DIRECTION OUTPUT ;
    USE SIGNAL ;
    ANTENNADIFFAREA 0.440000 ;
    PORT
      LAYER Metal2 ;
        RECT 655.200 779.440 655.760 780.000 ;
    END
  END ne_out[13]
  PIN ne_out[14]
    DIRECTION OUTPUT ;
    USE SIGNAL ;
    ANTENNADIFFAREA 0.440000 ;
    PORT
      LAYER Metal2 ;
        RECT 660.800 779.440 661.360 780.000 ;
    END
  END ne_out[14]
  PIN ne_out[15]
    DIRECTION OUTPUT ;
    USE SIGNAL ;
    ANTENNADIFFAREA 0.440000 ;
    PORT
      LAYER Metal2 ;
        RECT 666.400 779.440 666.960 780.000 ;
    END
  END ne_out[15]
  PIN ne_out[16]
    DIRECTION OUTPUT ;
    USE SIGNAL ;
    ANTENNADIFFAREA 0.440000 ;
    PORT
      LAYER Metal2 ;
        RECT 672.000 779.440 672.560 780.000 ;
    END
  END ne_out[16]
  PIN ne_out[17]
    DIRECTION OUTPUT ;
    USE SIGNAL ;
    ANTENNADIFFAREA 0.440000 ;
    PORT
      LAYER Metal2 ;
        RECT 677.600 779.440 678.160 780.000 ;
    END
  END ne_out[17]
  PIN ne_out[18]
    DIRECTION OUTPUT ;
    USE SIGNAL ;
    ANTENNADIFFAREA 0.440000 ;
    PORT
      LAYER Metal2 ;
        RECT 683.200 779.440 683.760 780.000 ;
    END
  END ne_out[18]
  PIN ne_out[19]
    DIRECTION OUTPUT ;
    USE SIGNAL ;
    ANTENNADIFFAREA 0.440000 ;
    PORT
      LAYER Metal2 ;
        RECT 688.800 779.440 689.360 780.000 ;
    END
  END ne_out[19]
  PIN ne_out[1]
    DIRECTION OUTPUT ;
    USE SIGNAL ;
    ANTENNADIFFAREA 0.440000 ;
    PORT
      LAYER Metal2 ;
        RECT 588.000 779.440 588.560 780.000 ;
    END
  END ne_out[1]
  PIN ne_out[20]
    DIRECTION OUTPUT ;
    USE SIGNAL ;
    ANTENNADIFFAREA 0.440000 ;
    PORT
      LAYER Metal2 ;
        RECT 694.400 779.440 694.960 780.000 ;
    END
  END ne_out[20]
  PIN ne_out[21]
    DIRECTION OUTPUT ;
    USE SIGNAL ;
    ANTENNADIFFAREA 0.440000 ;
    PORT
      LAYER Metal2 ;
        RECT 700.000 779.440 700.560 780.000 ;
    END
  END ne_out[21]
  PIN ne_out[22]
    DIRECTION OUTPUT ;
    USE SIGNAL ;
    ANTENNADIFFAREA 0.440000 ;
    PORT
      LAYER Metal2 ;
        RECT 705.600 779.440 706.160 780.000 ;
    END
  END ne_out[22]
  PIN ne_out[23]
    DIRECTION OUTPUT ;
    USE SIGNAL ;
    ANTENNADIFFAREA 0.440000 ;
    PORT
      LAYER Metal2 ;
        RECT 711.200 779.440 711.760 780.000 ;
    END
  END ne_out[23]
  PIN ne_out[24]
    DIRECTION OUTPUT ;
    USE SIGNAL ;
    ANTENNADIFFAREA 0.440000 ;
    PORT
      LAYER Metal2 ;
        RECT 716.800 779.440 717.360 780.000 ;
    END
  END ne_out[24]
  PIN ne_out[25]
    DIRECTION OUTPUT ;
    USE SIGNAL ;
    ANTENNADIFFAREA 0.440000 ;
    PORT
      LAYER Metal2 ;
        RECT 722.400 779.440 722.960 780.000 ;
    END
  END ne_out[25]
  PIN ne_out[26]
    DIRECTION OUTPUT ;
    USE SIGNAL ;
    ANTENNADIFFAREA 0.440000 ;
    PORT
      LAYER Metal2 ;
        RECT 728.000 779.440 728.560 780.000 ;
    END
  END ne_out[26]
  PIN ne_out[27]
    DIRECTION OUTPUT ;
    USE SIGNAL ;
    ANTENNADIFFAREA 0.440000 ;
    PORT
      LAYER Metal2 ;
        RECT 733.600 779.440 734.160 780.000 ;
    END
  END ne_out[27]
  PIN ne_out[28]
    DIRECTION OUTPUT ;
    USE SIGNAL ;
    ANTENNADIFFAREA 0.440000 ;
    PORT
      LAYER Metal2 ;
        RECT 739.200 779.440 739.760 780.000 ;
    END
  END ne_out[28]
  PIN ne_out[29]
    DIRECTION OUTPUT ;
    USE SIGNAL ;
    ANTENNADIFFAREA 0.440000 ;
    PORT
      LAYER Metal2 ;
        RECT 744.800 779.440 745.360 780.000 ;
    END
  END ne_out[29]
  PIN ne_out[2]
    DIRECTION OUTPUT ;
    USE SIGNAL ;
    ANTENNADIFFAREA 0.440000 ;
    PORT
      LAYER Metal2 ;
        RECT 593.600 779.440 594.160 780.000 ;
    END
  END ne_out[2]
  PIN ne_out[30]
    DIRECTION OUTPUT ;
    USE SIGNAL ;
    ANTENNADIFFAREA 0.440000 ;
    PORT
      LAYER Metal2 ;
        RECT 750.400 779.440 750.960 780.000 ;
    END
  END ne_out[30]
  PIN ne_out[31]
    DIRECTION OUTPUT ;
    USE SIGNAL ;
    ANTENNADIFFAREA 0.440000 ;
    PORT
      LAYER Metal2 ;
        RECT 756.000 779.440 756.560 780.000 ;
    END
  END ne_out[31]
  PIN ne_out[32]
    DIRECTION OUTPUT ;
    USE SIGNAL ;
    ANTENNADIFFAREA 0.440000 ;
    PORT
      LAYER Metal2 ;
        RECT 761.600 779.440 762.160 780.000 ;
    END
  END ne_out[32]
  PIN ne_out[33]
    DIRECTION OUTPUT ;
    USE SIGNAL ;
    ANTENNADIFFAREA 0.440000 ;
    PORT
      LAYER Metal2 ;
        RECT 767.200 779.440 767.760 780.000 ;
    END
  END ne_out[33]
  PIN ne_out[3]
    DIRECTION OUTPUT ;
    USE SIGNAL ;
    ANTENNADIFFAREA 0.440000 ;
    PORT
      LAYER Metal2 ;
        RECT 599.200 779.440 599.760 780.000 ;
    END
  END ne_out[3]
  PIN ne_out[4]
    DIRECTION OUTPUT ;
    USE SIGNAL ;
    ANTENNADIFFAREA 0.440000 ;
    PORT
      LAYER Metal2 ;
        RECT 604.800 779.440 605.360 780.000 ;
    END
  END ne_out[4]
  PIN ne_out[5]
    DIRECTION OUTPUT ;
    USE SIGNAL ;
    ANTENNADIFFAREA 0.440000 ;
    PORT
      LAYER Metal2 ;
        RECT 610.400 779.440 610.960 780.000 ;
    END
  END ne_out[5]
  PIN ne_out[6]
    DIRECTION OUTPUT ;
    USE SIGNAL ;
    ANTENNADIFFAREA 0.440000 ;
    PORT
      LAYER Metal2 ;
        RECT 616.000 779.440 616.560 780.000 ;
    END
  END ne_out[6]
  PIN ne_out[7]
    DIRECTION OUTPUT ;
    USE SIGNAL ;
    ANTENNADIFFAREA 0.440000 ;
    PORT
      LAYER Metal2 ;
        RECT 621.600 779.440 622.160 780.000 ;
    END
  END ne_out[7]
  PIN ne_out[8]
    DIRECTION OUTPUT ;
    USE SIGNAL ;
    ANTENNADIFFAREA 0.440000 ;
    PORT
      LAYER Metal2 ;
        RECT 627.200 779.440 627.760 780.000 ;
    END
  END ne_out[8]
  PIN ne_out[9]
    DIRECTION OUTPUT ;
    USE SIGNAL ;
    ANTENNADIFFAREA 0.440000 ;
    PORT
      LAYER Metal2 ;
        RECT 632.800 779.440 633.360 780.000 ;
    END
  END ne_out[9]
  PIN north_in[0]
    DIRECTION INPUT ;
    USE SIGNAL ;
    ANTENNAGATEAREA 2.665600 ;
    PORT
      LAYER Metal2 ;
        RECT 11.200 779.440 11.760 780.000 ;
    END
  END north_in[0]
  PIN north_in[10]
    DIRECTION INPUT ;
    USE SIGNAL ;
    ANTENNAGATEAREA 2.665600 ;
    PORT
      LAYER Metal2 ;
        RECT 67.200 779.440 67.760 780.000 ;
    END
  END north_in[10]
  PIN north_in[11]
    DIRECTION INPUT ;
    USE SIGNAL ;
    ANTENNAGATEAREA 2.665600 ;
    PORT
      LAYER Metal2 ;
        RECT 72.800 779.440 73.360 780.000 ;
    END
  END north_in[11]
  PIN north_in[12]
    DIRECTION INPUT ;
    USE SIGNAL ;
    ANTENNAGATEAREA 2.665600 ;
    PORT
      LAYER Metal2 ;
        RECT 78.400 779.440 78.960 780.000 ;
    END
  END north_in[12]
  PIN north_in[13]
    DIRECTION INPUT ;
    USE SIGNAL ;
    ANTENNAGATEAREA 2.665600 ;
    PORT
      LAYER Metal2 ;
        RECT 84.000 779.440 84.560 780.000 ;
    END
  END north_in[13]
  PIN north_in[14]
    DIRECTION INPUT ;
    USE SIGNAL ;
    ANTENNAGATEAREA 2.665600 ;
    PORT
      LAYER Metal2 ;
        RECT 89.600 779.440 90.160 780.000 ;
    END
  END north_in[14]
  PIN north_in[15]
    DIRECTION INPUT ;
    USE SIGNAL ;
    ANTENNAGATEAREA 2.665600 ;
    PORT
      LAYER Metal2 ;
        RECT 95.200 779.440 95.760 780.000 ;
    END
  END north_in[15]
  PIN north_in[16]
    DIRECTION INPUT ;
    USE SIGNAL ;
    ANTENNAGATEAREA 2.665600 ;
    PORT
      LAYER Metal2 ;
        RECT 100.800 779.440 101.360 780.000 ;
    END
  END north_in[16]
  PIN north_in[17]
    DIRECTION INPUT ;
    USE SIGNAL ;
    ANTENNAGATEAREA 2.665600 ;
    PORT
      LAYER Metal2 ;
        RECT 106.400 779.440 106.960 780.000 ;
    END
  END north_in[17]
  PIN north_in[18]
    DIRECTION INPUT ;
    USE SIGNAL ;
    ANTENNAGATEAREA 2.665600 ;
    PORT
      LAYER Metal2 ;
        RECT 112.000 779.440 112.560 780.000 ;
    END
  END north_in[18]
  PIN north_in[19]
    DIRECTION INPUT ;
    USE SIGNAL ;
    ANTENNAGATEAREA 2.665600 ;
    PORT
      LAYER Metal2 ;
        RECT 117.600 779.440 118.160 780.000 ;
    END
  END north_in[19]
  PIN north_in[1]
    DIRECTION INPUT ;
    USE SIGNAL ;
    ANTENNAGATEAREA 2.665600 ;
    PORT
      LAYER Metal2 ;
        RECT 16.800 779.440 17.360 780.000 ;
    END
  END north_in[1]
  PIN north_in[20]
    DIRECTION INPUT ;
    USE SIGNAL ;
    ANTENNAGATEAREA 2.665600 ;
    PORT
      LAYER Metal2 ;
        RECT 123.200 779.440 123.760 780.000 ;
    END
  END north_in[20]
  PIN north_in[21]
    DIRECTION INPUT ;
    USE SIGNAL ;
    ANTENNAGATEAREA 2.665600 ;
    PORT
      LAYER Metal2 ;
        RECT 128.800 779.440 129.360 780.000 ;
    END
  END north_in[21]
  PIN north_in[22]
    DIRECTION INPUT ;
    USE SIGNAL ;
    ANTENNAGATEAREA 2.665600 ;
    PORT
      LAYER Metal2 ;
        RECT 134.400 779.440 134.960 780.000 ;
    END
  END north_in[22]
  PIN north_in[23]
    DIRECTION INPUT ;
    USE SIGNAL ;
    ANTENNAGATEAREA 2.665600 ;
    PORT
      LAYER Metal2 ;
        RECT 140.000 779.440 140.560 780.000 ;
    END
  END north_in[23]
  PIN north_in[24]
    DIRECTION INPUT ;
    USE SIGNAL ;
    ANTENNAGATEAREA 2.665600 ;
    PORT
      LAYER Metal2 ;
        RECT 145.600 779.440 146.160 780.000 ;
    END
  END north_in[24]
  PIN north_in[25]
    DIRECTION INPUT ;
    USE SIGNAL ;
    ANTENNAGATEAREA 2.665600 ;
    PORT
      LAYER Metal2 ;
        RECT 151.200 779.440 151.760 780.000 ;
    END
  END north_in[25]
  PIN north_in[26]
    DIRECTION INPUT ;
    USE SIGNAL ;
    ANTENNAGATEAREA 2.665600 ;
    PORT
      LAYER Metal2 ;
        RECT 156.800 779.440 157.360 780.000 ;
    END
  END north_in[26]
  PIN north_in[27]
    DIRECTION INPUT ;
    USE SIGNAL ;
    ANTENNAGATEAREA 2.665600 ;
    PORT
      LAYER Metal2 ;
        RECT 162.400 779.440 162.960 780.000 ;
    END
  END north_in[27]
  PIN north_in[28]
    DIRECTION INPUT ;
    USE SIGNAL ;
    ANTENNAGATEAREA 2.665600 ;
    PORT
      LAYER Metal2 ;
        RECT 168.000 779.440 168.560 780.000 ;
    END
  END north_in[28]
  PIN north_in[29]
    DIRECTION INPUT ;
    USE SIGNAL ;
    ANTENNAGATEAREA 2.665600 ;
    PORT
      LAYER Metal2 ;
        RECT 173.600 779.440 174.160 780.000 ;
    END
  END north_in[29]
  PIN north_in[2]
    DIRECTION INPUT ;
    USE SIGNAL ;
    ANTENNAGATEAREA 2.665600 ;
    PORT
      LAYER Metal2 ;
        RECT 22.400 779.440 22.960 780.000 ;
    END
  END north_in[2]
  PIN north_in[30]
    DIRECTION INPUT ;
    USE SIGNAL ;
    ANTENNAGATEAREA 2.665600 ;
    PORT
      LAYER Metal2 ;
        RECT 179.200 779.440 179.760 780.000 ;
    END
  END north_in[30]
  PIN north_in[31]
    DIRECTION INPUT ;
    USE SIGNAL ;
    ANTENNAGATEAREA 2.665600 ;
    PORT
      LAYER Metal2 ;
        RECT 184.800 779.440 185.360 780.000 ;
    END
  END north_in[31]
  PIN north_in[32]
    DIRECTION INPUT ;
    USE SIGNAL ;
    ANTENNAGATEAREA 2.665600 ;
    PORT
      LAYER Metal2 ;
        RECT 190.400 779.440 190.960 780.000 ;
    END
  END north_in[32]
  PIN north_in[33]
    DIRECTION INPUT ;
    USE SIGNAL ;
    ANTENNAGATEAREA 2.665600 ;
    PORT
      LAYER Metal2 ;
        RECT 196.000 779.440 196.560 780.000 ;
    END
  END north_in[33]
  PIN north_in[3]
    DIRECTION INPUT ;
    USE SIGNAL ;
    ANTENNAGATEAREA 2.665600 ;
    PORT
      LAYER Metal2 ;
        RECT 28.000 779.440 28.560 780.000 ;
    END
  END north_in[3]
  PIN north_in[4]
    DIRECTION INPUT ;
    USE SIGNAL ;
    ANTENNAGATEAREA 2.665600 ;
    PORT
      LAYER Metal2 ;
        RECT 33.600 779.440 34.160 780.000 ;
    END
  END north_in[4]
  PIN north_in[5]
    DIRECTION INPUT ;
    USE SIGNAL ;
    ANTENNAGATEAREA 2.665600 ;
    PORT
      LAYER Metal2 ;
        RECT 39.200 779.440 39.760 780.000 ;
    END
  END north_in[5]
  PIN north_in[6]
    DIRECTION INPUT ;
    USE SIGNAL ;
    ANTENNAGATEAREA 2.665600 ;
    PORT
      LAYER Metal2 ;
        RECT 44.800 779.440 45.360 780.000 ;
    END
  END north_in[6]
  PIN north_in[7]
    DIRECTION INPUT ;
    USE SIGNAL ;
    ANTENNAGATEAREA 2.665600 ;
    PORT
      LAYER Metal2 ;
        RECT 50.400 779.440 50.960 780.000 ;
    END
  END north_in[7]
  PIN north_in[8]
    DIRECTION INPUT ;
    USE SIGNAL ;
    ANTENNAGATEAREA 2.665600 ;
    PORT
      LAYER Metal2 ;
        RECT 56.000 779.440 56.560 780.000 ;
    END
  END north_in[8]
  PIN north_in[9]
    DIRECTION INPUT ;
    USE SIGNAL ;
    ANTENNAGATEAREA 2.665600 ;
    PORT
      LAYER Metal2 ;
        RECT 61.600 779.440 62.160 780.000 ;
    END
  END north_in[9]
  PIN north_out[0]
    DIRECTION OUTPUT ;
    USE SIGNAL ;
    ANTENNADIFFAREA 0.440000 ;
    PORT
      LAYER Metal2 ;
        RECT 201.600 779.440 202.160 780.000 ;
    END
  END north_out[0]
  PIN north_out[10]
    DIRECTION OUTPUT ;
    USE SIGNAL ;
    ANTENNADIFFAREA 0.440000 ;
    PORT
      LAYER Metal2 ;
        RECT 257.600 779.440 258.160 780.000 ;
    END
  END north_out[10]
  PIN north_out[11]
    DIRECTION OUTPUT ;
    USE SIGNAL ;
    ANTENNADIFFAREA 0.440000 ;
    PORT
      LAYER Metal2 ;
        RECT 263.200 779.440 263.760 780.000 ;
    END
  END north_out[11]
  PIN north_out[12]
    DIRECTION OUTPUT ;
    USE SIGNAL ;
    ANTENNADIFFAREA 0.440000 ;
    PORT
      LAYER Metal2 ;
        RECT 268.800 779.440 269.360 780.000 ;
    END
  END north_out[12]
  PIN north_out[13]
    DIRECTION OUTPUT ;
    USE SIGNAL ;
    ANTENNADIFFAREA 0.440000 ;
    PORT
      LAYER Metal2 ;
        RECT 274.400 779.440 274.960 780.000 ;
    END
  END north_out[13]
  PIN north_out[14]
    DIRECTION OUTPUT ;
    USE SIGNAL ;
    ANTENNADIFFAREA 0.440000 ;
    PORT
      LAYER Metal2 ;
        RECT 280.000 779.440 280.560 780.000 ;
    END
  END north_out[14]
  PIN north_out[15]
    DIRECTION OUTPUT ;
    USE SIGNAL ;
    ANTENNADIFFAREA 0.440000 ;
    PORT
      LAYER Metal2 ;
        RECT 285.600 779.440 286.160 780.000 ;
    END
  END north_out[15]
  PIN north_out[16]
    DIRECTION OUTPUT ;
    USE SIGNAL ;
    ANTENNADIFFAREA 0.440000 ;
    PORT
      LAYER Metal2 ;
        RECT 291.200 779.440 291.760 780.000 ;
    END
  END north_out[16]
  PIN north_out[17]
    DIRECTION OUTPUT ;
    USE SIGNAL ;
    ANTENNADIFFAREA 0.440000 ;
    PORT
      LAYER Metal2 ;
        RECT 296.800 779.440 297.360 780.000 ;
    END
  END north_out[17]
  PIN north_out[18]
    DIRECTION OUTPUT ;
    USE SIGNAL ;
    ANTENNADIFFAREA 0.440000 ;
    PORT
      LAYER Metal2 ;
        RECT 302.400 779.440 302.960 780.000 ;
    END
  END north_out[18]
  PIN north_out[19]
    DIRECTION OUTPUT ;
    USE SIGNAL ;
    ANTENNADIFFAREA 0.440000 ;
    PORT
      LAYER Metal2 ;
        RECT 308.000 779.440 308.560 780.000 ;
    END
  END north_out[19]
  PIN north_out[1]
    DIRECTION OUTPUT ;
    USE SIGNAL ;
    ANTENNADIFFAREA 0.440000 ;
    PORT
      LAYER Metal2 ;
        RECT 207.200 779.440 207.760 780.000 ;
    END
  END north_out[1]
  PIN north_out[20]
    DIRECTION OUTPUT ;
    USE SIGNAL ;
    ANTENNADIFFAREA 0.440000 ;
    PORT
      LAYER Metal2 ;
        RECT 313.600 779.440 314.160 780.000 ;
    END
  END north_out[20]
  PIN north_out[21]
    DIRECTION OUTPUT ;
    USE SIGNAL ;
    ANTENNADIFFAREA 0.440000 ;
    PORT
      LAYER Metal2 ;
        RECT 319.200 779.440 319.760 780.000 ;
    END
  END north_out[21]
  PIN north_out[22]
    DIRECTION OUTPUT ;
    USE SIGNAL ;
    ANTENNADIFFAREA 0.440000 ;
    PORT
      LAYER Metal2 ;
        RECT 324.800 779.440 325.360 780.000 ;
    END
  END north_out[22]
  PIN north_out[23]
    DIRECTION OUTPUT ;
    USE SIGNAL ;
    ANTENNADIFFAREA 0.440000 ;
    PORT
      LAYER Metal2 ;
        RECT 330.400 779.440 330.960 780.000 ;
    END
  END north_out[23]
  PIN north_out[24]
    DIRECTION OUTPUT ;
    USE SIGNAL ;
    ANTENNADIFFAREA 0.440000 ;
    PORT
      LAYER Metal2 ;
        RECT 336.000 779.440 336.560 780.000 ;
    END
  END north_out[24]
  PIN north_out[25]
    DIRECTION OUTPUT ;
    USE SIGNAL ;
    ANTENNADIFFAREA 0.440000 ;
    PORT
      LAYER Metal2 ;
        RECT 341.600 779.440 342.160 780.000 ;
    END
  END north_out[25]
  PIN north_out[26]
    DIRECTION OUTPUT ;
    USE SIGNAL ;
    ANTENNADIFFAREA 0.440000 ;
    PORT
      LAYER Metal2 ;
        RECT 347.200 779.440 347.760 780.000 ;
    END
  END north_out[26]
  PIN north_out[27]
    DIRECTION OUTPUT ;
    USE SIGNAL ;
    ANTENNADIFFAREA 0.440000 ;
    PORT
      LAYER Metal2 ;
        RECT 352.800 779.440 353.360 780.000 ;
    END
  END north_out[27]
  PIN north_out[28]
    DIRECTION OUTPUT ;
    USE SIGNAL ;
    ANTENNADIFFAREA 0.440000 ;
    PORT
      LAYER Metal2 ;
        RECT 358.400 779.440 358.960 780.000 ;
    END
  END north_out[28]
  PIN north_out[29]
    DIRECTION OUTPUT ;
    USE SIGNAL ;
    ANTENNADIFFAREA 0.440000 ;
    PORT
      LAYER Metal2 ;
        RECT 364.000 779.440 364.560 780.000 ;
    END
  END north_out[29]
  PIN north_out[2]
    DIRECTION OUTPUT ;
    USE SIGNAL ;
    ANTENNADIFFAREA 0.440000 ;
    PORT
      LAYER Metal2 ;
        RECT 212.800 779.440 213.360 780.000 ;
    END
  END north_out[2]
  PIN north_out[30]
    DIRECTION OUTPUT ;
    USE SIGNAL ;
    ANTENNADIFFAREA 0.440000 ;
    PORT
      LAYER Metal2 ;
        RECT 369.600 779.440 370.160 780.000 ;
    END
  END north_out[30]
  PIN north_out[31]
    DIRECTION OUTPUT ;
    USE SIGNAL ;
    ANTENNADIFFAREA 0.440000 ;
    PORT
      LAYER Metal2 ;
        RECT 375.200 779.440 375.760 780.000 ;
    END
  END north_out[31]
  PIN north_out[32]
    DIRECTION OUTPUT ;
    USE SIGNAL ;
    ANTENNADIFFAREA 0.440000 ;
    PORT
      LAYER Metal2 ;
        RECT 380.800 779.440 381.360 780.000 ;
    END
  END north_out[32]
  PIN north_out[33]
    DIRECTION OUTPUT ;
    USE SIGNAL ;
    ANTENNADIFFAREA 0.440000 ;
    PORT
      LAYER Metal2 ;
        RECT 386.400 779.440 386.960 780.000 ;
    END
  END north_out[33]
  PIN north_out[3]
    DIRECTION OUTPUT ;
    USE SIGNAL ;
    ANTENNADIFFAREA 0.440000 ;
    PORT
      LAYER Metal2 ;
        RECT 218.400 779.440 218.960 780.000 ;
    END
  END north_out[3]
  PIN north_out[4]
    DIRECTION OUTPUT ;
    USE SIGNAL ;
    ANTENNADIFFAREA 0.440000 ;
    PORT
      LAYER Metal2 ;
        RECT 224.000 779.440 224.560 780.000 ;
    END
  END north_out[4]
  PIN north_out[5]
    DIRECTION OUTPUT ;
    USE SIGNAL ;
    ANTENNADIFFAREA 0.440000 ;
    PORT
      LAYER Metal2 ;
        RECT 229.600 779.440 230.160 780.000 ;
    END
  END north_out[5]
  PIN north_out[6]
    DIRECTION OUTPUT ;
    USE SIGNAL ;
    ANTENNADIFFAREA 0.440000 ;
    PORT
      LAYER Metal2 ;
        RECT 235.200 779.440 235.760 780.000 ;
    END
  END north_out[6]
  PIN north_out[7]
    DIRECTION OUTPUT ;
    USE SIGNAL ;
    ANTENNADIFFAREA 0.440000 ;
    PORT
      LAYER Metal2 ;
        RECT 240.800 779.440 241.360 780.000 ;
    END
  END north_out[7]
  PIN north_out[8]
    DIRECTION OUTPUT ;
    USE SIGNAL ;
    ANTENNADIFFAREA 0.440000 ;
    PORT
      LAYER Metal2 ;
        RECT 246.400 779.440 246.960 780.000 ;
    END
  END north_out[8]
  PIN north_out[9]
    DIRECTION OUTPUT ;
    USE SIGNAL ;
    ANTENNADIFFAREA 0.440000 ;
    PORT
      LAYER Metal2 ;
        RECT 252.000 779.440 252.560 780.000 ;
    END
  END north_out[9]
  PIN nw_in[0]
    DIRECTION INPUT ;
    USE SIGNAL ;
    ANTENNAGATEAREA 2.665600 ;
    PORT
      LAYER Metal3 ;
        RECT 0.000 392.000 0.560 392.560 ;
    END
  END nw_in[0]
  PIN nw_in[10]
    DIRECTION INPUT ;
    USE SIGNAL ;
    ANTENNAGATEAREA 2.665600 ;
    PORT
      LAYER Metal3 ;
        RECT 0.000 448.000 0.560 448.560 ;
    END
  END nw_in[10]
  PIN nw_in[11]
    DIRECTION INPUT ;
    USE SIGNAL ;
    ANTENNAGATEAREA 2.665600 ;
    PORT
      LAYER Metal3 ;
        RECT 0.000 453.600 0.560 454.160 ;
    END
  END nw_in[11]
  PIN nw_in[12]
    DIRECTION INPUT ;
    USE SIGNAL ;
    ANTENNAGATEAREA 2.665600 ;
    PORT
      LAYER Metal3 ;
        RECT 0.000 459.200 0.560 459.760 ;
    END
  END nw_in[12]
  PIN nw_in[13]
    DIRECTION INPUT ;
    USE SIGNAL ;
    ANTENNAGATEAREA 2.665600 ;
    PORT
      LAYER Metal3 ;
        RECT 0.000 464.800 0.560 465.360 ;
    END
  END nw_in[13]
  PIN nw_in[14]
    DIRECTION INPUT ;
    USE SIGNAL ;
    ANTENNAGATEAREA 2.665600 ;
    PORT
      LAYER Metal3 ;
        RECT 0.000 470.400 0.560 470.960 ;
    END
  END nw_in[14]
  PIN nw_in[15]
    DIRECTION INPUT ;
    USE SIGNAL ;
    ANTENNAGATEAREA 2.665600 ;
    PORT
      LAYER Metal3 ;
        RECT 0.000 476.000 0.560 476.560 ;
    END
  END nw_in[15]
  PIN nw_in[16]
    DIRECTION INPUT ;
    USE SIGNAL ;
    ANTENNAGATEAREA 2.665600 ;
    PORT
      LAYER Metal3 ;
        RECT 0.000 481.600 0.560 482.160 ;
    END
  END nw_in[16]
  PIN nw_in[17]
    DIRECTION INPUT ;
    USE SIGNAL ;
    ANTENNAGATEAREA 2.665600 ;
    PORT
      LAYER Metal3 ;
        RECT 0.000 487.200 0.560 487.760 ;
    END
  END nw_in[17]
  PIN nw_in[18]
    DIRECTION INPUT ;
    USE SIGNAL ;
    ANTENNAGATEAREA 2.665600 ;
    PORT
      LAYER Metal3 ;
        RECT 0.000 492.800 0.560 493.360 ;
    END
  END nw_in[18]
  PIN nw_in[19]
    DIRECTION INPUT ;
    USE SIGNAL ;
    ANTENNAGATEAREA 2.665600 ;
    PORT
      LAYER Metal3 ;
        RECT 0.000 498.400 0.560 498.960 ;
    END
  END nw_in[19]
  PIN nw_in[1]
    DIRECTION INPUT ;
    USE SIGNAL ;
    ANTENNAGATEAREA 2.665600 ;
    PORT
      LAYER Metal3 ;
        RECT 0.000 397.600 0.560 398.160 ;
    END
  END nw_in[1]
  PIN nw_in[20]
    DIRECTION INPUT ;
    USE SIGNAL ;
    ANTENNAGATEAREA 2.665600 ;
    PORT
      LAYER Metal3 ;
        RECT 0.000 504.000 0.560 504.560 ;
    END
  END nw_in[20]
  PIN nw_in[21]
    DIRECTION INPUT ;
    USE SIGNAL ;
    ANTENNAGATEAREA 2.665600 ;
    PORT
      LAYER Metal3 ;
        RECT 0.000 509.600 0.560 510.160 ;
    END
  END nw_in[21]
  PIN nw_in[22]
    DIRECTION INPUT ;
    USE SIGNAL ;
    ANTENNAGATEAREA 2.665600 ;
    PORT
      LAYER Metal3 ;
        RECT 0.000 515.200 0.560 515.760 ;
    END
  END nw_in[22]
  PIN nw_in[23]
    DIRECTION INPUT ;
    USE SIGNAL ;
    ANTENNAGATEAREA 2.665600 ;
    PORT
      LAYER Metal3 ;
        RECT 0.000 520.800 0.560 521.360 ;
    END
  END nw_in[23]
  PIN nw_in[24]
    DIRECTION INPUT ;
    USE SIGNAL ;
    ANTENNAGATEAREA 2.665600 ;
    PORT
      LAYER Metal3 ;
        RECT 0.000 526.400 0.560 526.960 ;
    END
  END nw_in[24]
  PIN nw_in[25]
    DIRECTION INPUT ;
    USE SIGNAL ;
    ANTENNAGATEAREA 2.665600 ;
    PORT
      LAYER Metal3 ;
        RECT 0.000 532.000 0.560 532.560 ;
    END
  END nw_in[25]
  PIN nw_in[26]
    DIRECTION INPUT ;
    USE SIGNAL ;
    ANTENNAGATEAREA 2.665600 ;
    PORT
      LAYER Metal3 ;
        RECT 0.000 537.600 0.560 538.160 ;
    END
  END nw_in[26]
  PIN nw_in[27]
    DIRECTION INPUT ;
    USE SIGNAL ;
    ANTENNAGATEAREA 2.665600 ;
    PORT
      LAYER Metal3 ;
        RECT 0.000 543.200 0.560 543.760 ;
    END
  END nw_in[27]
  PIN nw_in[28]
    DIRECTION INPUT ;
    USE SIGNAL ;
    ANTENNAGATEAREA 2.665600 ;
    PORT
      LAYER Metal3 ;
        RECT 0.000 548.800 0.560 549.360 ;
    END
  END nw_in[28]
  PIN nw_in[29]
    DIRECTION INPUT ;
    USE SIGNAL ;
    ANTENNAGATEAREA 2.665600 ;
    PORT
      LAYER Metal3 ;
        RECT 0.000 554.400 0.560 554.960 ;
    END
  END nw_in[29]
  PIN nw_in[2]
    DIRECTION INPUT ;
    USE SIGNAL ;
    ANTENNAGATEAREA 2.665600 ;
    PORT
      LAYER Metal3 ;
        RECT 0.000 403.200 0.560 403.760 ;
    END
  END nw_in[2]
  PIN nw_in[30]
    DIRECTION INPUT ;
    USE SIGNAL ;
    ANTENNAGATEAREA 2.665600 ;
    PORT
      LAYER Metal3 ;
        RECT 0.000 560.000 0.560 560.560 ;
    END
  END nw_in[30]
  PIN nw_in[31]
    DIRECTION INPUT ;
    USE SIGNAL ;
    ANTENNAGATEAREA 2.665600 ;
    PORT
      LAYER Metal3 ;
        RECT 0.000 565.600 0.560 566.160 ;
    END
  END nw_in[31]
  PIN nw_in[32]
    DIRECTION INPUT ;
    USE SIGNAL ;
    ANTENNAGATEAREA 2.665600 ;
    PORT
      LAYER Metal3 ;
        RECT 0.000 571.200 0.560 571.760 ;
    END
  END nw_in[32]
  PIN nw_in[33]
    DIRECTION INPUT ;
    USE SIGNAL ;
    ANTENNAGATEAREA 2.665600 ;
    PORT
      LAYER Metal3 ;
        RECT 0.000 576.800 0.560 577.360 ;
    END
  END nw_in[33]
  PIN nw_in[3]
    DIRECTION INPUT ;
    USE SIGNAL ;
    ANTENNAGATEAREA 2.665600 ;
    PORT
      LAYER Metal3 ;
        RECT 0.000 408.800 0.560 409.360 ;
    END
  END nw_in[3]
  PIN nw_in[4]
    DIRECTION INPUT ;
    USE SIGNAL ;
    ANTENNAGATEAREA 2.665600 ;
    PORT
      LAYER Metal3 ;
        RECT 0.000 414.400 0.560 414.960 ;
    END
  END nw_in[4]
  PIN nw_in[5]
    DIRECTION INPUT ;
    USE SIGNAL ;
    ANTENNAGATEAREA 2.665600 ;
    PORT
      LAYER Metal3 ;
        RECT 0.000 420.000 0.560 420.560 ;
    END
  END nw_in[5]
  PIN nw_in[6]
    DIRECTION INPUT ;
    USE SIGNAL ;
    ANTENNAGATEAREA 2.665600 ;
    PORT
      LAYER Metal3 ;
        RECT 0.000 425.600 0.560 426.160 ;
    END
  END nw_in[6]
  PIN nw_in[7]
    DIRECTION INPUT ;
    USE SIGNAL ;
    ANTENNAGATEAREA 2.665600 ;
    PORT
      LAYER Metal3 ;
        RECT 0.000 431.200 0.560 431.760 ;
    END
  END nw_in[7]
  PIN nw_in[8]
    DIRECTION INPUT ;
    USE SIGNAL ;
    ANTENNAGATEAREA 2.665600 ;
    PORT
      LAYER Metal3 ;
        RECT 0.000 436.800 0.560 437.360 ;
    END
  END nw_in[8]
  PIN nw_in[9]
    DIRECTION INPUT ;
    USE SIGNAL ;
    ANTENNAGATEAREA 2.665600 ;
    PORT
      LAYER Metal3 ;
        RECT 0.000 442.400 0.560 442.960 ;
    END
  END nw_in[9]
  PIN nw_out[0]
    DIRECTION OUTPUT ;
    USE SIGNAL ;
    ANTENNADIFFAREA 0.440000 ;
    PORT
      LAYER Metal3 ;
        RECT 0.000 582.400 0.560 582.960 ;
    END
  END nw_out[0]
  PIN nw_out[10]
    DIRECTION OUTPUT ;
    USE SIGNAL ;
    ANTENNADIFFAREA 0.440000 ;
    PORT
      LAYER Metal3 ;
        RECT 0.000 638.400 0.560 638.960 ;
    END
  END nw_out[10]
  PIN nw_out[11]
    DIRECTION OUTPUT ;
    USE SIGNAL ;
    ANTENNADIFFAREA 0.440000 ;
    PORT
      LAYER Metal3 ;
        RECT 0.000 644.000 0.560 644.560 ;
    END
  END nw_out[11]
  PIN nw_out[12]
    DIRECTION OUTPUT ;
    USE SIGNAL ;
    ANTENNADIFFAREA 0.440000 ;
    PORT
      LAYER Metal3 ;
        RECT 0.000 649.600 0.560 650.160 ;
    END
  END nw_out[12]
  PIN nw_out[13]
    DIRECTION OUTPUT ;
    USE SIGNAL ;
    ANTENNADIFFAREA 0.440000 ;
    PORT
      LAYER Metal3 ;
        RECT 0.000 655.200 0.560 655.760 ;
    END
  END nw_out[13]
  PIN nw_out[14]
    DIRECTION OUTPUT ;
    USE SIGNAL ;
    ANTENNADIFFAREA 0.440000 ;
    PORT
      LAYER Metal3 ;
        RECT 0.000 660.800 0.560 661.360 ;
    END
  END nw_out[14]
  PIN nw_out[15]
    DIRECTION OUTPUT ;
    USE SIGNAL ;
    ANTENNADIFFAREA 0.440000 ;
    PORT
      LAYER Metal3 ;
        RECT 0.000 666.400 0.560 666.960 ;
    END
  END nw_out[15]
  PIN nw_out[16]
    DIRECTION OUTPUT ;
    USE SIGNAL ;
    ANTENNADIFFAREA 0.440000 ;
    PORT
      LAYER Metal3 ;
        RECT 0.000 672.000 0.560 672.560 ;
    END
  END nw_out[16]
  PIN nw_out[17]
    DIRECTION OUTPUT ;
    USE SIGNAL ;
    ANTENNADIFFAREA 0.440000 ;
    PORT
      LAYER Metal3 ;
        RECT 0.000 677.600 0.560 678.160 ;
    END
  END nw_out[17]
  PIN nw_out[18]
    DIRECTION OUTPUT ;
    USE SIGNAL ;
    ANTENNADIFFAREA 0.440000 ;
    PORT
      LAYER Metal3 ;
        RECT 0.000 683.200 0.560 683.760 ;
    END
  END nw_out[18]
  PIN nw_out[19]
    DIRECTION OUTPUT ;
    USE SIGNAL ;
    ANTENNADIFFAREA 0.440000 ;
    PORT
      LAYER Metal3 ;
        RECT 0.000 688.800 0.560 689.360 ;
    END
  END nw_out[19]
  PIN nw_out[1]
    DIRECTION OUTPUT ;
    USE SIGNAL ;
    ANTENNADIFFAREA 0.440000 ;
    PORT
      LAYER Metal3 ;
        RECT 0.000 588.000 0.560 588.560 ;
    END
  END nw_out[1]
  PIN nw_out[20]
    DIRECTION OUTPUT ;
    USE SIGNAL ;
    ANTENNADIFFAREA 0.440000 ;
    PORT
      LAYER Metal3 ;
        RECT 0.000 694.400 0.560 694.960 ;
    END
  END nw_out[20]
  PIN nw_out[21]
    DIRECTION OUTPUT ;
    USE SIGNAL ;
    ANTENNADIFFAREA 0.440000 ;
    PORT
      LAYER Metal3 ;
        RECT 0.000 700.000 0.560 700.560 ;
    END
  END nw_out[21]
  PIN nw_out[22]
    DIRECTION OUTPUT ;
    USE SIGNAL ;
    ANTENNADIFFAREA 0.440000 ;
    PORT
      LAYER Metal3 ;
        RECT 0.000 705.600 0.560 706.160 ;
    END
  END nw_out[22]
  PIN nw_out[23]
    DIRECTION OUTPUT ;
    USE SIGNAL ;
    ANTENNADIFFAREA 0.440000 ;
    PORT
      LAYER Metal3 ;
        RECT 0.000 711.200 0.560 711.760 ;
    END
  END nw_out[23]
  PIN nw_out[24]
    DIRECTION OUTPUT ;
    USE SIGNAL ;
    ANTENNADIFFAREA 0.440000 ;
    PORT
      LAYER Metal3 ;
        RECT 0.000 716.800 0.560 717.360 ;
    END
  END nw_out[24]
  PIN nw_out[25]
    DIRECTION OUTPUT ;
    USE SIGNAL ;
    ANTENNADIFFAREA 0.440000 ;
    PORT
      LAYER Metal3 ;
        RECT 0.000 722.400 0.560 722.960 ;
    END
  END nw_out[25]
  PIN nw_out[26]
    DIRECTION OUTPUT ;
    USE SIGNAL ;
    ANTENNADIFFAREA 0.440000 ;
    PORT
      LAYER Metal3 ;
        RECT 0.000 728.000 0.560 728.560 ;
    END
  END nw_out[26]
  PIN nw_out[27]
    DIRECTION OUTPUT ;
    USE SIGNAL ;
    ANTENNADIFFAREA 0.440000 ;
    PORT
      LAYER Metal3 ;
        RECT 0.000 733.600 0.560 734.160 ;
    END
  END nw_out[27]
  PIN nw_out[28]
    DIRECTION OUTPUT ;
    USE SIGNAL ;
    ANTENNADIFFAREA 0.440000 ;
    PORT
      LAYER Metal3 ;
        RECT 0.000 739.200 0.560 739.760 ;
    END
  END nw_out[28]
  PIN nw_out[29]
    DIRECTION OUTPUT ;
    USE SIGNAL ;
    ANTENNADIFFAREA 0.440000 ;
    PORT
      LAYER Metal3 ;
        RECT 0.000 744.800 0.560 745.360 ;
    END
  END nw_out[29]
  PIN nw_out[2]
    DIRECTION OUTPUT ;
    USE SIGNAL ;
    ANTENNADIFFAREA 0.440000 ;
    PORT
      LAYER Metal3 ;
        RECT 0.000 593.600 0.560 594.160 ;
    END
  END nw_out[2]
  PIN nw_out[30]
    DIRECTION OUTPUT ;
    USE SIGNAL ;
    ANTENNADIFFAREA 0.440000 ;
    PORT
      LAYER Metal3 ;
        RECT 0.000 750.400 0.560 750.960 ;
    END
  END nw_out[30]
  PIN nw_out[31]
    DIRECTION OUTPUT ;
    USE SIGNAL ;
    ANTENNADIFFAREA 0.440000 ;
    PORT
      LAYER Metal3 ;
        RECT 0.000 756.000 0.560 756.560 ;
    END
  END nw_out[31]
  PIN nw_out[32]
    DIRECTION OUTPUT ;
    USE SIGNAL ;
    ANTENNADIFFAREA 0.440000 ;
    PORT
      LAYER Metal3 ;
        RECT 0.000 761.600 0.560 762.160 ;
    END
  END nw_out[32]
  PIN nw_out[33]
    DIRECTION OUTPUT ;
    USE SIGNAL ;
    ANTENNADIFFAREA 0.440000 ;
    PORT
      LAYER Metal3 ;
        RECT 0.000 767.200 0.560 767.760 ;
    END
  END nw_out[33]
  PIN nw_out[3]
    DIRECTION OUTPUT ;
    USE SIGNAL ;
    ANTENNADIFFAREA 0.440000 ;
    PORT
      LAYER Metal3 ;
        RECT 0.000 599.200 0.560 599.760 ;
    END
  END nw_out[3]
  PIN nw_out[4]
    DIRECTION OUTPUT ;
    USE SIGNAL ;
    ANTENNADIFFAREA 0.440000 ;
    PORT
      LAYER Metal3 ;
        RECT 0.000 604.800 0.560 605.360 ;
    END
  END nw_out[4]
  PIN nw_out[5]
    DIRECTION OUTPUT ;
    USE SIGNAL ;
    ANTENNADIFFAREA 0.440000 ;
    PORT
      LAYER Metal3 ;
        RECT 0.000 610.400 0.560 610.960 ;
    END
  END nw_out[5]
  PIN nw_out[6]
    DIRECTION OUTPUT ;
    USE SIGNAL ;
    ANTENNADIFFAREA 0.440000 ;
    PORT
      LAYER Metal3 ;
        RECT 0.000 616.000 0.560 616.560 ;
    END
  END nw_out[6]
  PIN nw_out[7]
    DIRECTION OUTPUT ;
    USE SIGNAL ;
    ANTENNADIFFAREA 0.440000 ;
    PORT
      LAYER Metal3 ;
        RECT 0.000 621.600 0.560 622.160 ;
    END
  END nw_out[7]
  PIN nw_out[8]
    DIRECTION OUTPUT ;
    USE SIGNAL ;
    ANTENNADIFFAREA 0.440000 ;
    PORT
      LAYER Metal3 ;
        RECT 0.000 627.200 0.560 627.760 ;
    END
  END nw_out[8]
  PIN nw_out[9]
    DIRECTION OUTPUT ;
    USE SIGNAL ;
    ANTENNADIFFAREA 0.440000 ;
    PORT
      LAYER Metal3 ;
        RECT 0.000 632.800 0.560 633.360 ;
    END
  END nw_out[9]
  PIN rst
    DIRECTION INPUT ;
    USE SIGNAL ;
    ANTENNAGATEAREA 2.665600 ;
    PORT
      LAYER Metal2 ;
        RECT 705.600 0.000 706.160 0.560 ;
    END
  END rst
  PIN se_in[0]
    DIRECTION INPUT ;
    USE SIGNAL ;
    ANTENNAGATEAREA 2.665600 ;
    PORT
      LAYER Metal3 ;
        RECT 779.440 392.000 780.000 392.560 ;
    END
  END se_in[0]
  PIN se_in[10]
    DIRECTION INPUT ;
    USE SIGNAL ;
    ANTENNAGATEAREA 2.665600 ;
    PORT
      LAYER Metal3 ;
        RECT 779.440 448.000 780.000 448.560 ;
    END
  END se_in[10]
  PIN se_in[11]
    DIRECTION INPUT ;
    USE SIGNAL ;
    ANTENNAGATEAREA 2.665600 ;
    PORT
      LAYER Metal3 ;
        RECT 779.440 453.600 780.000 454.160 ;
    END
  END se_in[11]
  PIN se_in[12]
    DIRECTION INPUT ;
    USE SIGNAL ;
    ANTENNAGATEAREA 2.665600 ;
    PORT
      LAYER Metal3 ;
        RECT 779.440 459.200 780.000 459.760 ;
    END
  END se_in[12]
  PIN se_in[13]
    DIRECTION INPUT ;
    USE SIGNAL ;
    ANTENNAGATEAREA 2.665600 ;
    PORT
      LAYER Metal3 ;
        RECT 779.440 464.800 780.000 465.360 ;
    END
  END se_in[13]
  PIN se_in[14]
    DIRECTION INPUT ;
    USE SIGNAL ;
    ANTENNAGATEAREA 2.665600 ;
    PORT
      LAYER Metal3 ;
        RECT 779.440 470.400 780.000 470.960 ;
    END
  END se_in[14]
  PIN se_in[15]
    DIRECTION INPUT ;
    USE SIGNAL ;
    ANTENNAGATEAREA 2.665600 ;
    PORT
      LAYER Metal3 ;
        RECT 779.440 476.000 780.000 476.560 ;
    END
  END se_in[15]
  PIN se_in[16]
    DIRECTION INPUT ;
    USE SIGNAL ;
    ANTENNAGATEAREA 2.665600 ;
    PORT
      LAYER Metal3 ;
        RECT 779.440 481.600 780.000 482.160 ;
    END
  END se_in[16]
  PIN se_in[17]
    DIRECTION INPUT ;
    USE SIGNAL ;
    ANTENNAGATEAREA 2.665600 ;
    PORT
      LAYER Metal3 ;
        RECT 779.440 487.200 780.000 487.760 ;
    END
  END se_in[17]
  PIN se_in[18]
    DIRECTION INPUT ;
    USE SIGNAL ;
    ANTENNAGATEAREA 2.665600 ;
    PORT
      LAYER Metal3 ;
        RECT 779.440 492.800 780.000 493.360 ;
    END
  END se_in[18]
  PIN se_in[19]
    DIRECTION INPUT ;
    USE SIGNAL ;
    ANTENNAGATEAREA 2.665600 ;
    PORT
      LAYER Metal3 ;
        RECT 779.440 498.400 780.000 498.960 ;
    END
  END se_in[19]
  PIN se_in[1]
    DIRECTION INPUT ;
    USE SIGNAL ;
    ANTENNAGATEAREA 2.665600 ;
    PORT
      LAYER Metal3 ;
        RECT 779.440 397.600 780.000 398.160 ;
    END
  END se_in[1]
  PIN se_in[20]
    DIRECTION INPUT ;
    USE SIGNAL ;
    ANTENNAGATEAREA 2.665600 ;
    PORT
      LAYER Metal3 ;
        RECT 779.440 504.000 780.000 504.560 ;
    END
  END se_in[20]
  PIN se_in[21]
    DIRECTION INPUT ;
    USE SIGNAL ;
    ANTENNAGATEAREA 2.665600 ;
    PORT
      LAYER Metal3 ;
        RECT 779.440 509.600 780.000 510.160 ;
    END
  END se_in[21]
  PIN se_in[22]
    DIRECTION INPUT ;
    USE SIGNAL ;
    ANTENNAGATEAREA 2.665600 ;
    PORT
      LAYER Metal3 ;
        RECT 779.440 515.200 780.000 515.760 ;
    END
  END se_in[22]
  PIN se_in[23]
    DIRECTION INPUT ;
    USE SIGNAL ;
    ANTENNAGATEAREA 2.665600 ;
    PORT
      LAYER Metal3 ;
        RECT 779.440 520.800 780.000 521.360 ;
    END
  END se_in[23]
  PIN se_in[24]
    DIRECTION INPUT ;
    USE SIGNAL ;
    ANTENNAGATEAREA 2.665600 ;
    PORT
      LAYER Metal3 ;
        RECT 779.440 526.400 780.000 526.960 ;
    END
  END se_in[24]
  PIN se_in[25]
    DIRECTION INPUT ;
    USE SIGNAL ;
    ANTENNAGATEAREA 2.665600 ;
    PORT
      LAYER Metal3 ;
        RECT 779.440 532.000 780.000 532.560 ;
    END
  END se_in[25]
  PIN se_in[26]
    DIRECTION INPUT ;
    USE SIGNAL ;
    ANTENNAGATEAREA 2.665600 ;
    PORT
      LAYER Metal3 ;
        RECT 779.440 537.600 780.000 538.160 ;
    END
  END se_in[26]
  PIN se_in[27]
    DIRECTION INPUT ;
    USE SIGNAL ;
    ANTENNAGATEAREA 2.665600 ;
    PORT
      LAYER Metal3 ;
        RECT 779.440 543.200 780.000 543.760 ;
    END
  END se_in[27]
  PIN se_in[28]
    DIRECTION INPUT ;
    USE SIGNAL ;
    ANTENNAGATEAREA 2.665600 ;
    PORT
      LAYER Metal3 ;
        RECT 779.440 548.800 780.000 549.360 ;
    END
  END se_in[28]
  PIN se_in[29]
    DIRECTION INPUT ;
    USE SIGNAL ;
    ANTENNAGATEAREA 2.665600 ;
    PORT
      LAYER Metal3 ;
        RECT 779.440 554.400 780.000 554.960 ;
    END
  END se_in[29]
  PIN se_in[2]
    DIRECTION INPUT ;
    USE SIGNAL ;
    ANTENNAGATEAREA 2.665600 ;
    PORT
      LAYER Metal3 ;
        RECT 779.440 403.200 780.000 403.760 ;
    END
  END se_in[2]
  PIN se_in[30]
    DIRECTION INPUT ;
    USE SIGNAL ;
    ANTENNAGATEAREA 2.665600 ;
    PORT
      LAYER Metal3 ;
        RECT 779.440 560.000 780.000 560.560 ;
    END
  END se_in[30]
  PIN se_in[31]
    DIRECTION INPUT ;
    USE SIGNAL ;
    ANTENNAGATEAREA 2.665600 ;
    PORT
      LAYER Metal3 ;
        RECT 779.440 565.600 780.000 566.160 ;
    END
  END se_in[31]
  PIN se_in[32]
    DIRECTION INPUT ;
    USE SIGNAL ;
    ANTENNAGATEAREA 2.665600 ;
    PORT
      LAYER Metal3 ;
        RECT 779.440 571.200 780.000 571.760 ;
    END
  END se_in[32]
  PIN se_in[33]
    DIRECTION INPUT ;
    USE SIGNAL ;
    ANTENNAGATEAREA 2.665600 ;
    PORT
      LAYER Metal3 ;
        RECT 779.440 576.800 780.000 577.360 ;
    END
  END se_in[33]
  PIN se_in[3]
    DIRECTION INPUT ;
    USE SIGNAL ;
    ANTENNAGATEAREA 2.665600 ;
    PORT
      LAYER Metal3 ;
        RECT 779.440 408.800 780.000 409.360 ;
    END
  END se_in[3]
  PIN se_in[4]
    DIRECTION INPUT ;
    USE SIGNAL ;
    ANTENNAGATEAREA 2.665600 ;
    PORT
      LAYER Metal3 ;
        RECT 779.440 414.400 780.000 414.960 ;
    END
  END se_in[4]
  PIN se_in[5]
    DIRECTION INPUT ;
    USE SIGNAL ;
    ANTENNAGATEAREA 2.665600 ;
    PORT
      LAYER Metal3 ;
        RECT 779.440 420.000 780.000 420.560 ;
    END
  END se_in[5]
  PIN se_in[6]
    DIRECTION INPUT ;
    USE SIGNAL ;
    ANTENNAGATEAREA 2.665600 ;
    PORT
      LAYER Metal3 ;
        RECT 779.440 425.600 780.000 426.160 ;
    END
  END se_in[6]
  PIN se_in[7]
    DIRECTION INPUT ;
    USE SIGNAL ;
    ANTENNAGATEAREA 2.665600 ;
    PORT
      LAYER Metal3 ;
        RECT 779.440 431.200 780.000 431.760 ;
    END
  END se_in[7]
  PIN se_in[8]
    DIRECTION INPUT ;
    USE SIGNAL ;
    ANTENNAGATEAREA 2.665600 ;
    PORT
      LAYER Metal3 ;
        RECT 779.440 436.800 780.000 437.360 ;
    END
  END se_in[8]
  PIN se_in[9]
    DIRECTION INPUT ;
    USE SIGNAL ;
    ANTENNAGATEAREA 2.665600 ;
    PORT
      LAYER Metal3 ;
        RECT 779.440 442.400 780.000 442.960 ;
    END
  END se_in[9]
  PIN se_out[0]
    DIRECTION OUTPUT ;
    USE SIGNAL ;
    ANTENNADIFFAREA 7.461300 ;
    PORT
      LAYER Metal3 ;
        RECT 779.440 582.400 780.000 582.960 ;
    END
  END se_out[0]
  PIN se_out[10]
    DIRECTION OUTPUT ;
    USE SIGNAL ;
    ANTENNADIFFAREA 7.461300 ;
    PORT
      LAYER Metal3 ;
        RECT 779.440 638.400 780.000 638.960 ;
    END
  END se_out[10]
  PIN se_out[11]
    DIRECTION OUTPUT ;
    USE SIGNAL ;
    ANTENNADIFFAREA 7.461300 ;
    PORT
      LAYER Metal3 ;
        RECT 779.440 644.000 780.000 644.560 ;
    END
  END se_out[11]
  PIN se_out[12]
    DIRECTION OUTPUT ;
    USE SIGNAL ;
    ANTENNADIFFAREA 7.461300 ;
    PORT
      LAYER Metal3 ;
        RECT 779.440 649.600 780.000 650.160 ;
    END
  END se_out[12]
  PIN se_out[13]
    DIRECTION OUTPUT ;
    USE SIGNAL ;
    ANTENNADIFFAREA 7.461300 ;
    PORT
      LAYER Metal3 ;
        RECT 779.440 655.200 780.000 655.760 ;
    END
  END se_out[13]
  PIN se_out[14]
    DIRECTION OUTPUT ;
    USE SIGNAL ;
    ANTENNADIFFAREA 7.461300 ;
    PORT
      LAYER Metal3 ;
        RECT 779.440 660.800 780.000 661.360 ;
    END
  END se_out[14]
  PIN se_out[15]
    DIRECTION OUTPUT ;
    USE SIGNAL ;
    ANTENNADIFFAREA 7.461300 ;
    PORT
      LAYER Metal3 ;
        RECT 779.440 666.400 780.000 666.960 ;
    END
  END se_out[15]
  PIN se_out[16]
    DIRECTION OUTPUT ;
    USE SIGNAL ;
    ANTENNADIFFAREA 7.461300 ;
    PORT
      LAYER Metal3 ;
        RECT 779.440 672.000 780.000 672.560 ;
    END
  END se_out[16]
  PIN se_out[17]
    DIRECTION OUTPUT ;
    USE SIGNAL ;
    ANTENNADIFFAREA 7.461300 ;
    PORT
      LAYER Metal3 ;
        RECT 779.440 677.600 780.000 678.160 ;
    END
  END se_out[17]
  PIN se_out[18]
    DIRECTION OUTPUT ;
    USE SIGNAL ;
    ANTENNADIFFAREA 7.461300 ;
    PORT
      LAYER Metal3 ;
        RECT 779.440 683.200 780.000 683.760 ;
    END
  END se_out[18]
  PIN se_out[19]
    DIRECTION OUTPUT ;
    USE SIGNAL ;
    ANTENNADIFFAREA 7.461300 ;
    PORT
      LAYER Metal3 ;
        RECT 779.440 688.800 780.000 689.360 ;
    END
  END se_out[19]
  PIN se_out[1]
    DIRECTION OUTPUT ;
    USE SIGNAL ;
    ANTENNADIFFAREA 7.461300 ;
    PORT
      LAYER Metal3 ;
        RECT 779.440 588.000 780.000 588.560 ;
    END
  END se_out[1]
  PIN se_out[20]
    DIRECTION OUTPUT ;
    USE SIGNAL ;
    ANTENNADIFFAREA 7.461300 ;
    PORT
      LAYER Metal3 ;
        RECT 779.440 694.400 780.000 694.960 ;
    END
  END se_out[20]
  PIN se_out[21]
    DIRECTION OUTPUT ;
    USE SIGNAL ;
    ANTENNADIFFAREA 7.461300 ;
    PORT
      LAYER Metal3 ;
        RECT 779.440 700.000 780.000 700.560 ;
    END
  END se_out[21]
  PIN se_out[22]
    DIRECTION OUTPUT ;
    USE SIGNAL ;
    ANTENNADIFFAREA 7.461300 ;
    PORT
      LAYER Metal3 ;
        RECT 779.440 705.600 780.000 706.160 ;
    END
  END se_out[22]
  PIN se_out[23]
    DIRECTION OUTPUT ;
    USE SIGNAL ;
    ANTENNADIFFAREA 7.461300 ;
    PORT
      LAYER Metal3 ;
        RECT 779.440 711.200 780.000 711.760 ;
    END
  END se_out[23]
  PIN se_out[24]
    DIRECTION OUTPUT ;
    USE SIGNAL ;
    ANTENNADIFFAREA 7.461300 ;
    PORT
      LAYER Metal3 ;
        RECT 779.440 716.800 780.000 717.360 ;
    END
  END se_out[24]
  PIN se_out[25]
    DIRECTION OUTPUT ;
    USE SIGNAL ;
    ANTENNADIFFAREA 7.461300 ;
    PORT
      LAYER Metal3 ;
        RECT 779.440 722.400 780.000 722.960 ;
    END
  END se_out[25]
  PIN se_out[26]
    DIRECTION OUTPUT ;
    USE SIGNAL ;
    ANTENNADIFFAREA 7.461300 ;
    PORT
      LAYER Metal3 ;
        RECT 779.440 728.000 780.000 728.560 ;
    END
  END se_out[26]
  PIN se_out[27]
    DIRECTION OUTPUT ;
    USE SIGNAL ;
    ANTENNADIFFAREA 7.461300 ;
    PORT
      LAYER Metal3 ;
        RECT 779.440 733.600 780.000 734.160 ;
    END
  END se_out[27]
  PIN se_out[28]
    DIRECTION OUTPUT ;
    USE SIGNAL ;
    ANTENNADIFFAREA 7.461300 ;
    PORT
      LAYER Metal3 ;
        RECT 779.440 739.200 780.000 739.760 ;
    END
  END se_out[28]
  PIN se_out[29]
    DIRECTION OUTPUT ;
    USE SIGNAL ;
    ANTENNADIFFAREA 7.461300 ;
    PORT
      LAYER Metal3 ;
        RECT 779.440 744.800 780.000 745.360 ;
    END
  END se_out[29]
  PIN se_out[2]
    DIRECTION OUTPUT ;
    USE SIGNAL ;
    ANTENNADIFFAREA 7.461300 ;
    PORT
      LAYER Metal3 ;
        RECT 779.440 593.600 780.000 594.160 ;
    END
  END se_out[2]
  PIN se_out[30]
    DIRECTION OUTPUT ;
    USE SIGNAL ;
    ANTENNADIFFAREA 7.461300 ;
    PORT
      LAYER Metal3 ;
        RECT 779.440 750.400 780.000 750.960 ;
    END
  END se_out[30]
  PIN se_out[31]
    DIRECTION OUTPUT ;
    USE SIGNAL ;
    ANTENNADIFFAREA 7.461300 ;
    PORT
      LAYER Metal3 ;
        RECT 779.440 756.000 780.000 756.560 ;
    END
  END se_out[31]
  PIN se_out[32]
    DIRECTION OUTPUT ;
    USE SIGNAL ;
    ANTENNADIFFAREA 7.461300 ;
    PORT
      LAYER Metal3 ;
        RECT 779.440 761.600 780.000 762.160 ;
    END
  END se_out[32]
  PIN se_out[33]
    DIRECTION OUTPUT ;
    USE SIGNAL ;
    ANTENNADIFFAREA 7.461300 ;
    PORT
      LAYER Metal3 ;
        RECT 779.440 767.200 780.000 767.760 ;
    END
  END se_out[33]
  PIN se_out[3]
    DIRECTION OUTPUT ;
    USE SIGNAL ;
    ANTENNADIFFAREA 7.461300 ;
    PORT
      LAYER Metal3 ;
        RECT 779.440 599.200 780.000 599.760 ;
    END
  END se_out[3]
  PIN se_out[4]
    DIRECTION OUTPUT ;
    USE SIGNAL ;
    ANTENNADIFFAREA 7.461300 ;
    PORT
      LAYER Metal3 ;
        RECT 779.440 604.800 780.000 605.360 ;
    END
  END se_out[4]
  PIN se_out[5]
    DIRECTION OUTPUT ;
    USE SIGNAL ;
    ANTENNADIFFAREA 7.461300 ;
    PORT
      LAYER Metal3 ;
        RECT 779.440 610.400 780.000 610.960 ;
    END
  END se_out[5]
  PIN se_out[6]
    DIRECTION OUTPUT ;
    USE SIGNAL ;
    ANTENNADIFFAREA 7.461300 ;
    PORT
      LAYER Metal3 ;
        RECT 779.440 616.000 780.000 616.560 ;
    END
  END se_out[6]
  PIN se_out[7]
    DIRECTION OUTPUT ;
    USE SIGNAL ;
    ANTENNADIFFAREA 7.461300 ;
    PORT
      LAYER Metal3 ;
        RECT 779.440 621.600 780.000 622.160 ;
    END
  END se_out[7]
  PIN se_out[8]
    DIRECTION OUTPUT ;
    USE SIGNAL ;
    ANTENNADIFFAREA 7.461300 ;
    PORT
      LAYER Metal3 ;
        RECT 779.440 627.200 780.000 627.760 ;
    END
  END se_out[8]
  PIN se_out[9]
    DIRECTION OUTPUT ;
    USE SIGNAL ;
    ANTENNADIFFAREA 7.461300 ;
    PORT
      LAYER Metal3 ;
        RECT 779.440 632.800 780.000 633.360 ;
    END
  END se_out[9]
  PIN south_in[0]
    DIRECTION INPUT ;
    USE SIGNAL ;
    ANTENNAGATEAREA 2.665600 ;
    PORT
      LAYER Metal2 ;
        RECT 73.920 0.000 74.480 0.560 ;
    END
  END south_in[0]
  PIN south_in[10]
    DIRECTION INPUT ;
    USE SIGNAL ;
    ANTENNAGATEAREA 2.665600 ;
    PORT
      LAYER Metal2 ;
        RECT 107.520 0.000 108.080 0.560 ;
    END
  END south_in[10]
  PIN south_in[11]
    DIRECTION INPUT ;
    USE SIGNAL ;
    ANTENNAGATEAREA 2.665600 ;
    PORT
      LAYER Metal2 ;
        RECT 110.880 0.000 111.440 0.560 ;
    END
  END south_in[11]
  PIN south_in[12]
    DIRECTION INPUT ;
    USE SIGNAL ;
    ANTENNAGATEAREA 2.665600 ;
    PORT
      LAYER Metal2 ;
        RECT 114.240 0.000 114.800 0.560 ;
    END
  END south_in[12]
  PIN south_in[13]
    DIRECTION INPUT ;
    USE SIGNAL ;
    ANTENNAGATEAREA 2.665600 ;
    PORT
      LAYER Metal2 ;
        RECT 117.600 0.000 118.160 0.560 ;
    END
  END south_in[13]
  PIN south_in[14]
    DIRECTION INPUT ;
    USE SIGNAL ;
    ANTENNAGATEAREA 2.665600 ;
    PORT
      LAYER Metal2 ;
        RECT 120.960 0.000 121.520 0.560 ;
    END
  END south_in[14]
  PIN south_in[15]
    DIRECTION INPUT ;
    USE SIGNAL ;
    ANTENNAGATEAREA 2.665600 ;
    PORT
      LAYER Metal2 ;
        RECT 124.320 0.000 124.880 0.560 ;
    END
  END south_in[15]
  PIN south_in[16]
    DIRECTION INPUT ;
    USE SIGNAL ;
    ANTENNAGATEAREA 2.665600 ;
    PORT
      LAYER Metal2 ;
        RECT 127.680 0.000 128.240 0.560 ;
    END
  END south_in[16]
  PIN south_in[17]
    DIRECTION INPUT ;
    USE SIGNAL ;
    ANTENNAGATEAREA 2.665600 ;
    PORT
      LAYER Metal2 ;
        RECT 131.040 0.000 131.600 0.560 ;
    END
  END south_in[17]
  PIN south_in[18]
    DIRECTION INPUT ;
    USE SIGNAL ;
    ANTENNAGATEAREA 2.665600 ;
    PORT
      LAYER Metal2 ;
        RECT 134.400 0.000 134.960 0.560 ;
    END
  END south_in[18]
  PIN south_in[19]
    DIRECTION INPUT ;
    USE SIGNAL ;
    ANTENNAGATEAREA 2.665600 ;
    PORT
      LAYER Metal2 ;
        RECT 137.760 0.000 138.320 0.560 ;
    END
  END south_in[19]
  PIN south_in[1]
    DIRECTION INPUT ;
    USE SIGNAL ;
    ANTENNAGATEAREA 2.665600 ;
    PORT
      LAYER Metal2 ;
        RECT 77.280 0.000 77.840 0.560 ;
    END
  END south_in[1]
  PIN south_in[20]
    DIRECTION INPUT ;
    USE SIGNAL ;
    ANTENNAGATEAREA 2.665600 ;
    PORT
      LAYER Metal2 ;
        RECT 141.120 0.000 141.680 0.560 ;
    END
  END south_in[20]
  PIN south_in[21]
    DIRECTION INPUT ;
    USE SIGNAL ;
    ANTENNAGATEAREA 2.665600 ;
    PORT
      LAYER Metal2 ;
        RECT 144.480 0.000 145.040 0.560 ;
    END
  END south_in[21]
  PIN south_in[22]
    DIRECTION INPUT ;
    USE SIGNAL ;
    ANTENNAGATEAREA 2.665600 ;
    PORT
      LAYER Metal2 ;
        RECT 147.840 0.000 148.400 0.560 ;
    END
  END south_in[22]
  PIN south_in[23]
    DIRECTION INPUT ;
    USE SIGNAL ;
    ANTENNAGATEAREA 2.665600 ;
    PORT
      LAYER Metal2 ;
        RECT 151.200 0.000 151.760 0.560 ;
    END
  END south_in[23]
  PIN south_in[24]
    DIRECTION INPUT ;
    USE SIGNAL ;
    ANTENNAGATEAREA 2.665600 ;
    PORT
      LAYER Metal2 ;
        RECT 154.560 0.000 155.120 0.560 ;
    END
  END south_in[24]
  PIN south_in[25]
    DIRECTION INPUT ;
    USE SIGNAL ;
    ANTENNAGATEAREA 2.665600 ;
    PORT
      LAYER Metal2 ;
        RECT 157.920 0.000 158.480 0.560 ;
    END
  END south_in[25]
  PIN south_in[26]
    DIRECTION INPUT ;
    USE SIGNAL ;
    ANTENNAGATEAREA 2.665600 ;
    PORT
      LAYER Metal2 ;
        RECT 161.280 0.000 161.840 0.560 ;
    END
  END south_in[26]
  PIN south_in[27]
    DIRECTION INPUT ;
    USE SIGNAL ;
    ANTENNAGATEAREA 2.665600 ;
    PORT
      LAYER Metal2 ;
        RECT 164.640 0.000 165.200 0.560 ;
    END
  END south_in[27]
  PIN south_in[28]
    DIRECTION INPUT ;
    USE SIGNAL ;
    ANTENNAGATEAREA 2.665600 ;
    PORT
      LAYER Metal2 ;
        RECT 168.000 0.000 168.560 0.560 ;
    END
  END south_in[28]
  PIN south_in[29]
    DIRECTION INPUT ;
    USE SIGNAL ;
    ANTENNAGATEAREA 2.665600 ;
    PORT
      LAYER Metal2 ;
        RECT 171.360 0.000 171.920 0.560 ;
    END
  END south_in[29]
  PIN south_in[2]
    DIRECTION INPUT ;
    USE SIGNAL ;
    ANTENNAGATEAREA 2.665600 ;
    PORT
      LAYER Metal2 ;
        RECT 80.640 0.000 81.200 0.560 ;
    END
  END south_in[2]
  PIN south_in[30]
    DIRECTION INPUT ;
    USE SIGNAL ;
    ANTENNAGATEAREA 2.665600 ;
    PORT
      LAYER Metal2 ;
        RECT 174.720 0.000 175.280 0.560 ;
    END
  END south_in[30]
  PIN south_in[31]
    DIRECTION INPUT ;
    USE SIGNAL ;
    ANTENNAGATEAREA 2.665600 ;
    PORT
      LAYER Metal2 ;
        RECT 178.080 0.000 178.640 0.560 ;
    END
  END south_in[31]
  PIN south_in[32]
    DIRECTION INPUT ;
    USE SIGNAL ;
    ANTENNAGATEAREA 2.665600 ;
    PORT
      LAYER Metal2 ;
        RECT 181.440 0.000 182.000 0.560 ;
    END
  END south_in[32]
  PIN south_in[33]
    DIRECTION INPUT ;
    USE SIGNAL ;
    ANTENNAGATEAREA 2.665600 ;
    PORT
      LAYER Metal2 ;
        RECT 184.800 0.000 185.360 0.560 ;
    END
  END south_in[33]
  PIN south_in[3]
    DIRECTION INPUT ;
    USE SIGNAL ;
    ANTENNAGATEAREA 2.665600 ;
    PORT
      LAYER Metal2 ;
        RECT 84.000 0.000 84.560 0.560 ;
    END
  END south_in[3]
  PIN south_in[4]
    DIRECTION INPUT ;
    USE SIGNAL ;
    ANTENNAGATEAREA 2.665600 ;
    PORT
      LAYER Metal2 ;
        RECT 87.360 0.000 87.920 0.560 ;
    END
  END south_in[4]
  PIN south_in[5]
    DIRECTION INPUT ;
    USE SIGNAL ;
    ANTENNAGATEAREA 2.665600 ;
    PORT
      LAYER Metal2 ;
        RECT 90.720 0.000 91.280 0.560 ;
    END
  END south_in[5]
  PIN south_in[6]
    DIRECTION INPUT ;
    USE SIGNAL ;
    ANTENNAGATEAREA 2.665600 ;
    PORT
      LAYER Metal2 ;
        RECT 94.080 0.000 94.640 0.560 ;
    END
  END south_in[6]
  PIN south_in[7]
    DIRECTION INPUT ;
    USE SIGNAL ;
    ANTENNAGATEAREA 2.665600 ;
    PORT
      LAYER Metal2 ;
        RECT 97.440 0.000 98.000 0.560 ;
    END
  END south_in[7]
  PIN south_in[8]
    DIRECTION INPUT ;
    USE SIGNAL ;
    ANTENNAGATEAREA 2.665600 ;
    PORT
      LAYER Metal2 ;
        RECT 100.800 0.000 101.360 0.560 ;
    END
  END south_in[8]
  PIN south_in[9]
    DIRECTION INPUT ;
    USE SIGNAL ;
    ANTENNAGATEAREA 2.665600 ;
    PORT
      LAYER Metal2 ;
        RECT 104.160 0.000 104.720 0.560 ;
    END
  END south_in[9]
  PIN south_out[0]
    DIRECTION OUTPUT ;
    USE SIGNAL ;
    ANTENNADIFFAREA 7.461300 ;
    PORT
      LAYER Metal2 ;
        RECT 188.160 0.000 188.720 0.560 ;
    END
  END south_out[0]
  PIN south_out[10]
    DIRECTION OUTPUT ;
    USE SIGNAL ;
    ANTENNADIFFAREA 7.461300 ;
    PORT
      LAYER Metal2 ;
        RECT 221.760 0.000 222.320 0.560 ;
    END
  END south_out[10]
  PIN south_out[11]
    DIRECTION OUTPUT ;
    USE SIGNAL ;
    ANTENNADIFFAREA 7.461300 ;
    PORT
      LAYER Metal2 ;
        RECT 225.120 0.000 225.680 0.560 ;
    END
  END south_out[11]
  PIN south_out[12]
    DIRECTION OUTPUT ;
    USE SIGNAL ;
    ANTENNADIFFAREA 7.461300 ;
    PORT
      LAYER Metal2 ;
        RECT 228.480 0.000 229.040 0.560 ;
    END
  END south_out[12]
  PIN south_out[13]
    DIRECTION OUTPUT ;
    USE SIGNAL ;
    ANTENNADIFFAREA 7.461300 ;
    PORT
      LAYER Metal2 ;
        RECT 231.840 0.000 232.400 0.560 ;
    END
  END south_out[13]
  PIN south_out[14]
    DIRECTION OUTPUT ;
    USE SIGNAL ;
    ANTENNADIFFAREA 7.461300 ;
    PORT
      LAYER Metal2 ;
        RECT 235.200 0.000 235.760 0.560 ;
    END
  END south_out[14]
  PIN south_out[15]
    DIRECTION OUTPUT ;
    USE SIGNAL ;
    ANTENNADIFFAREA 7.461300 ;
    PORT
      LAYER Metal2 ;
        RECT 238.560 0.000 239.120 0.560 ;
    END
  END south_out[15]
  PIN south_out[16]
    DIRECTION OUTPUT ;
    USE SIGNAL ;
    ANTENNADIFFAREA 7.461300 ;
    PORT
      LAYER Metal2 ;
        RECT 241.920 0.000 242.480 0.560 ;
    END
  END south_out[16]
  PIN south_out[17]
    DIRECTION OUTPUT ;
    USE SIGNAL ;
    ANTENNADIFFAREA 7.461300 ;
    PORT
      LAYER Metal2 ;
        RECT 245.280 0.000 245.840 0.560 ;
    END
  END south_out[17]
  PIN south_out[18]
    DIRECTION OUTPUT ;
    USE SIGNAL ;
    ANTENNADIFFAREA 7.461300 ;
    PORT
      LAYER Metal2 ;
        RECT 248.640 0.000 249.200 0.560 ;
    END
  END south_out[18]
  PIN south_out[19]
    DIRECTION OUTPUT ;
    USE SIGNAL ;
    ANTENNADIFFAREA 7.461300 ;
    PORT
      LAYER Metal2 ;
        RECT 252.000 0.000 252.560 0.560 ;
    END
  END south_out[19]
  PIN south_out[1]
    DIRECTION OUTPUT ;
    USE SIGNAL ;
    ANTENNADIFFAREA 7.461300 ;
    PORT
      LAYER Metal2 ;
        RECT 191.520 0.000 192.080 0.560 ;
    END
  END south_out[1]
  PIN south_out[20]
    DIRECTION OUTPUT ;
    USE SIGNAL ;
    ANTENNADIFFAREA 7.461300 ;
    PORT
      LAYER Metal2 ;
        RECT 255.360 0.000 255.920 0.560 ;
    END
  END south_out[20]
  PIN south_out[21]
    DIRECTION OUTPUT ;
    USE SIGNAL ;
    ANTENNADIFFAREA 7.461300 ;
    PORT
      LAYER Metal2 ;
        RECT 258.720 0.000 259.280 0.560 ;
    END
  END south_out[21]
  PIN south_out[22]
    DIRECTION OUTPUT ;
    USE SIGNAL ;
    ANTENNADIFFAREA 7.461300 ;
    PORT
      LAYER Metal2 ;
        RECT 262.080 0.000 262.640 0.560 ;
    END
  END south_out[22]
  PIN south_out[23]
    DIRECTION OUTPUT ;
    USE SIGNAL ;
    ANTENNADIFFAREA 7.461300 ;
    PORT
      LAYER Metal2 ;
        RECT 265.440 0.000 266.000 0.560 ;
    END
  END south_out[23]
  PIN south_out[24]
    DIRECTION OUTPUT ;
    USE SIGNAL ;
    ANTENNADIFFAREA 7.461300 ;
    PORT
      LAYER Metal2 ;
        RECT 268.800 0.000 269.360 0.560 ;
    END
  END south_out[24]
  PIN south_out[25]
    DIRECTION OUTPUT ;
    USE SIGNAL ;
    ANTENNADIFFAREA 7.461300 ;
    PORT
      LAYER Metal2 ;
        RECT 272.160 0.000 272.720 0.560 ;
    END
  END south_out[25]
  PIN south_out[26]
    DIRECTION OUTPUT ;
    USE SIGNAL ;
    ANTENNADIFFAREA 7.461300 ;
    PORT
      LAYER Metal2 ;
        RECT 275.520 0.000 276.080 0.560 ;
    END
  END south_out[26]
  PIN south_out[27]
    DIRECTION OUTPUT ;
    USE SIGNAL ;
    ANTENNADIFFAREA 7.461300 ;
    PORT
      LAYER Metal2 ;
        RECT 278.880 0.000 279.440 0.560 ;
    END
  END south_out[27]
  PIN south_out[28]
    DIRECTION OUTPUT ;
    USE SIGNAL ;
    ANTENNADIFFAREA 7.461300 ;
    PORT
      LAYER Metal2 ;
        RECT 282.240 0.000 282.800 0.560 ;
    END
  END south_out[28]
  PIN south_out[29]
    DIRECTION OUTPUT ;
    USE SIGNAL ;
    ANTENNADIFFAREA 7.461300 ;
    PORT
      LAYER Metal2 ;
        RECT 285.600 0.000 286.160 0.560 ;
    END
  END south_out[29]
  PIN south_out[2]
    DIRECTION OUTPUT ;
    USE SIGNAL ;
    ANTENNADIFFAREA 7.461300 ;
    PORT
      LAYER Metal2 ;
        RECT 194.880 0.000 195.440 0.560 ;
    END
  END south_out[2]
  PIN south_out[30]
    DIRECTION OUTPUT ;
    USE SIGNAL ;
    ANTENNADIFFAREA 7.461300 ;
    PORT
      LAYER Metal2 ;
        RECT 288.960 0.000 289.520 0.560 ;
    END
  END south_out[30]
  PIN south_out[31]
    DIRECTION OUTPUT ;
    USE SIGNAL ;
    ANTENNADIFFAREA 7.461300 ;
    PORT
      LAYER Metal2 ;
        RECT 292.320 0.000 292.880 0.560 ;
    END
  END south_out[31]
  PIN south_out[32]
    DIRECTION OUTPUT ;
    USE SIGNAL ;
    ANTENNADIFFAREA 7.461300 ;
    PORT
      LAYER Metal2 ;
        RECT 295.680 0.000 296.240 0.560 ;
    END
  END south_out[32]
  PIN south_out[33]
    DIRECTION OUTPUT ;
    USE SIGNAL ;
    ANTENNADIFFAREA 7.461300 ;
    PORT
      LAYER Metal2 ;
        RECT 299.040 0.000 299.600 0.560 ;
    END
  END south_out[33]
  PIN south_out[3]
    DIRECTION OUTPUT ;
    USE SIGNAL ;
    ANTENNADIFFAREA 7.461300 ;
    PORT
      LAYER Metal2 ;
        RECT 198.240 0.000 198.800 0.560 ;
    END
  END south_out[3]
  PIN south_out[4]
    DIRECTION OUTPUT ;
    USE SIGNAL ;
    ANTENNADIFFAREA 7.461300 ;
    PORT
      LAYER Metal2 ;
        RECT 201.600 0.000 202.160 0.560 ;
    END
  END south_out[4]
  PIN south_out[5]
    DIRECTION OUTPUT ;
    USE SIGNAL ;
    ANTENNADIFFAREA 7.461300 ;
    PORT
      LAYER Metal2 ;
        RECT 204.960 0.000 205.520 0.560 ;
    END
  END south_out[5]
  PIN south_out[6]
    DIRECTION OUTPUT ;
    USE SIGNAL ;
    ANTENNADIFFAREA 7.461300 ;
    PORT
      LAYER Metal2 ;
        RECT 208.320 0.000 208.880 0.560 ;
    END
  END south_out[6]
  PIN south_out[7]
    DIRECTION OUTPUT ;
    USE SIGNAL ;
    ANTENNADIFFAREA 7.461300 ;
    PORT
      LAYER Metal2 ;
        RECT 211.680 0.000 212.240 0.560 ;
    END
  END south_out[7]
  PIN south_out[8]
    DIRECTION OUTPUT ;
    USE SIGNAL ;
    ANTENNADIFFAREA 7.461300 ;
    PORT
      LAYER Metal2 ;
        RECT 215.040 0.000 215.600 0.560 ;
    END
  END south_out[8]
  PIN south_out[9]
    DIRECTION OUTPUT ;
    USE SIGNAL ;
    ANTENNADIFFAREA 7.461300 ;
    PORT
      LAYER Metal2 ;
        RECT 218.400 0.000 218.960 0.560 ;
    END
  END south_out[9]
  PIN sw_in[0]
    DIRECTION INPUT ;
    USE SIGNAL ;
    ANTENNAGATEAREA 2.665600 ;
    PORT
      LAYER Metal2 ;
        RECT 302.400 0.000 302.960 0.560 ;
    END
  END sw_in[0]
  PIN sw_in[10]
    DIRECTION INPUT ;
    USE SIGNAL ;
    ANTENNAGATEAREA 2.665600 ;
    PORT
      LAYER Metal2 ;
        RECT 336.000 0.000 336.560 0.560 ;
    END
  END sw_in[10]
  PIN sw_in[11]
    DIRECTION INPUT ;
    USE SIGNAL ;
    ANTENNAGATEAREA 2.665600 ;
    PORT
      LAYER Metal2 ;
        RECT 339.360 0.000 339.920 0.560 ;
    END
  END sw_in[11]
  PIN sw_in[12]
    DIRECTION INPUT ;
    USE SIGNAL ;
    ANTENNAGATEAREA 2.665600 ;
    PORT
      LAYER Metal2 ;
        RECT 342.720 0.000 343.280 0.560 ;
    END
  END sw_in[12]
  PIN sw_in[13]
    DIRECTION INPUT ;
    USE SIGNAL ;
    ANTENNAGATEAREA 2.665600 ;
    PORT
      LAYER Metal2 ;
        RECT 346.080 0.000 346.640 0.560 ;
    END
  END sw_in[13]
  PIN sw_in[14]
    DIRECTION INPUT ;
    USE SIGNAL ;
    ANTENNAGATEAREA 2.665600 ;
    PORT
      LAYER Metal2 ;
        RECT 349.440 0.000 350.000 0.560 ;
    END
  END sw_in[14]
  PIN sw_in[15]
    DIRECTION INPUT ;
    USE SIGNAL ;
    ANTENNAGATEAREA 2.665600 ;
    PORT
      LAYER Metal2 ;
        RECT 352.800 0.000 353.360 0.560 ;
    END
  END sw_in[15]
  PIN sw_in[16]
    DIRECTION INPUT ;
    USE SIGNAL ;
    ANTENNAGATEAREA 2.665600 ;
    PORT
      LAYER Metal2 ;
        RECT 356.160 0.000 356.720 0.560 ;
    END
  END sw_in[16]
  PIN sw_in[17]
    DIRECTION INPUT ;
    USE SIGNAL ;
    ANTENNAGATEAREA 2.665600 ;
    PORT
      LAYER Metal2 ;
        RECT 359.520 0.000 360.080 0.560 ;
    END
  END sw_in[17]
  PIN sw_in[18]
    DIRECTION INPUT ;
    USE SIGNAL ;
    ANTENNAGATEAREA 2.665600 ;
    PORT
      LAYER Metal2 ;
        RECT 362.880 0.000 363.440 0.560 ;
    END
  END sw_in[18]
  PIN sw_in[19]
    DIRECTION INPUT ;
    USE SIGNAL ;
    ANTENNAGATEAREA 2.665600 ;
    PORT
      LAYER Metal2 ;
        RECT 366.240 0.000 366.800 0.560 ;
    END
  END sw_in[19]
  PIN sw_in[1]
    DIRECTION INPUT ;
    USE SIGNAL ;
    ANTENNAGATEAREA 2.665600 ;
    PORT
      LAYER Metal2 ;
        RECT 305.760 0.000 306.320 0.560 ;
    END
  END sw_in[1]
  PIN sw_in[20]
    DIRECTION INPUT ;
    USE SIGNAL ;
    ANTENNAGATEAREA 2.665600 ;
    PORT
      LAYER Metal2 ;
        RECT 369.600 0.000 370.160 0.560 ;
    END
  END sw_in[20]
  PIN sw_in[21]
    DIRECTION INPUT ;
    USE SIGNAL ;
    ANTENNAGATEAREA 2.665600 ;
    PORT
      LAYER Metal2 ;
        RECT 372.960 0.000 373.520 0.560 ;
    END
  END sw_in[21]
  PIN sw_in[22]
    DIRECTION INPUT ;
    USE SIGNAL ;
    ANTENNAGATEAREA 2.665600 ;
    PORT
      LAYER Metal2 ;
        RECT 376.320 0.000 376.880 0.560 ;
    END
  END sw_in[22]
  PIN sw_in[23]
    DIRECTION INPUT ;
    USE SIGNAL ;
    ANTENNAGATEAREA 2.665600 ;
    PORT
      LAYER Metal2 ;
        RECT 379.680 0.000 380.240 0.560 ;
    END
  END sw_in[23]
  PIN sw_in[24]
    DIRECTION INPUT ;
    USE SIGNAL ;
    ANTENNAGATEAREA 2.665600 ;
    PORT
      LAYER Metal2 ;
        RECT 383.040 0.000 383.600 0.560 ;
    END
  END sw_in[24]
  PIN sw_in[25]
    DIRECTION INPUT ;
    USE SIGNAL ;
    ANTENNAGATEAREA 2.665600 ;
    PORT
      LAYER Metal2 ;
        RECT 386.400 0.000 386.960 0.560 ;
    END
  END sw_in[25]
  PIN sw_in[26]
    DIRECTION INPUT ;
    USE SIGNAL ;
    ANTENNAGATEAREA 2.665600 ;
    PORT
      LAYER Metal2 ;
        RECT 389.760 0.000 390.320 0.560 ;
    END
  END sw_in[26]
  PIN sw_in[27]
    DIRECTION INPUT ;
    USE SIGNAL ;
    ANTENNAGATEAREA 2.665600 ;
    PORT
      LAYER Metal2 ;
        RECT 393.120 0.000 393.680 0.560 ;
    END
  END sw_in[27]
  PIN sw_in[28]
    DIRECTION INPUT ;
    USE SIGNAL ;
    ANTENNAGATEAREA 2.665600 ;
    PORT
      LAYER Metal2 ;
        RECT 396.480 0.000 397.040 0.560 ;
    END
  END sw_in[28]
  PIN sw_in[29]
    DIRECTION INPUT ;
    USE SIGNAL ;
    ANTENNAGATEAREA 2.665600 ;
    PORT
      LAYER Metal2 ;
        RECT 399.840 0.000 400.400 0.560 ;
    END
  END sw_in[29]
  PIN sw_in[2]
    DIRECTION INPUT ;
    USE SIGNAL ;
    ANTENNAGATEAREA 2.665600 ;
    PORT
      LAYER Metal2 ;
        RECT 309.120 0.000 309.680 0.560 ;
    END
  END sw_in[2]
  PIN sw_in[30]
    DIRECTION INPUT ;
    USE SIGNAL ;
    ANTENNAGATEAREA 2.665600 ;
    PORT
      LAYER Metal2 ;
        RECT 403.200 0.000 403.760 0.560 ;
    END
  END sw_in[30]
  PIN sw_in[31]
    DIRECTION INPUT ;
    USE SIGNAL ;
    ANTENNAGATEAREA 2.665600 ;
    PORT
      LAYER Metal2 ;
        RECT 406.560 0.000 407.120 0.560 ;
    END
  END sw_in[31]
  PIN sw_in[32]
    DIRECTION INPUT ;
    USE SIGNAL ;
    ANTENNAGATEAREA 2.665600 ;
    PORT
      LAYER Metal2 ;
        RECT 409.920 0.000 410.480 0.560 ;
    END
  END sw_in[32]
  PIN sw_in[33]
    DIRECTION INPUT ;
    USE SIGNAL ;
    ANTENNAGATEAREA 2.665600 ;
    PORT
      LAYER Metal2 ;
        RECT 413.280 0.000 413.840 0.560 ;
    END
  END sw_in[33]
  PIN sw_in[3]
    DIRECTION INPUT ;
    USE SIGNAL ;
    ANTENNAGATEAREA 2.665600 ;
    PORT
      LAYER Metal2 ;
        RECT 312.480 0.000 313.040 0.560 ;
    END
  END sw_in[3]
  PIN sw_in[4]
    DIRECTION INPUT ;
    USE SIGNAL ;
    ANTENNAGATEAREA 2.665600 ;
    PORT
      LAYER Metal2 ;
        RECT 315.840 0.000 316.400 0.560 ;
    END
  END sw_in[4]
  PIN sw_in[5]
    DIRECTION INPUT ;
    USE SIGNAL ;
    ANTENNAGATEAREA 2.665600 ;
    PORT
      LAYER Metal2 ;
        RECT 319.200 0.000 319.760 0.560 ;
    END
  END sw_in[5]
  PIN sw_in[6]
    DIRECTION INPUT ;
    USE SIGNAL ;
    ANTENNAGATEAREA 2.665600 ;
    PORT
      LAYER Metal2 ;
        RECT 322.560 0.000 323.120 0.560 ;
    END
  END sw_in[6]
  PIN sw_in[7]
    DIRECTION INPUT ;
    USE SIGNAL ;
    ANTENNAGATEAREA 2.665600 ;
    PORT
      LAYER Metal2 ;
        RECT 325.920 0.000 326.480 0.560 ;
    END
  END sw_in[7]
  PIN sw_in[8]
    DIRECTION INPUT ;
    USE SIGNAL ;
    ANTENNAGATEAREA 2.665600 ;
    PORT
      LAYER Metal2 ;
        RECT 329.280 0.000 329.840 0.560 ;
    END
  END sw_in[8]
  PIN sw_in[9]
    DIRECTION INPUT ;
    USE SIGNAL ;
    ANTENNAGATEAREA 2.665600 ;
    PORT
      LAYER Metal2 ;
        RECT 332.640 0.000 333.200 0.560 ;
    END
  END sw_in[9]
  PIN sw_out[0]
    DIRECTION OUTPUT ;
    USE SIGNAL ;
    ANTENNADIFFAREA 0.440000 ;
    PORT
      LAYER Metal2 ;
        RECT 416.640 0.000 417.200 0.560 ;
    END
  END sw_out[0]
  PIN sw_out[10]
    DIRECTION OUTPUT ;
    USE SIGNAL ;
    ANTENNADIFFAREA 0.440000 ;
    PORT
      LAYER Metal2 ;
        RECT 450.240 0.000 450.800 0.560 ;
    END
  END sw_out[10]
  PIN sw_out[11]
    DIRECTION OUTPUT ;
    USE SIGNAL ;
    ANTENNADIFFAREA 0.440000 ;
    PORT
      LAYER Metal2 ;
        RECT 453.600 0.000 454.160 0.560 ;
    END
  END sw_out[11]
  PIN sw_out[12]
    DIRECTION OUTPUT ;
    USE SIGNAL ;
    ANTENNADIFFAREA 0.440000 ;
    PORT
      LAYER Metal2 ;
        RECT 456.960 0.000 457.520 0.560 ;
    END
  END sw_out[12]
  PIN sw_out[13]
    DIRECTION OUTPUT ;
    USE SIGNAL ;
    ANTENNADIFFAREA 0.440000 ;
    PORT
      LAYER Metal2 ;
        RECT 460.320 0.000 460.880 0.560 ;
    END
  END sw_out[13]
  PIN sw_out[14]
    DIRECTION OUTPUT ;
    USE SIGNAL ;
    ANTENNADIFFAREA 0.440000 ;
    PORT
      LAYER Metal2 ;
        RECT 463.680 0.000 464.240 0.560 ;
    END
  END sw_out[14]
  PIN sw_out[15]
    DIRECTION OUTPUT ;
    USE SIGNAL ;
    ANTENNADIFFAREA 0.440000 ;
    PORT
      LAYER Metal2 ;
        RECT 467.040 0.000 467.600 0.560 ;
    END
  END sw_out[15]
  PIN sw_out[16]
    DIRECTION OUTPUT ;
    USE SIGNAL ;
    ANTENNADIFFAREA 0.440000 ;
    PORT
      LAYER Metal2 ;
        RECT 470.400 0.000 470.960 0.560 ;
    END
  END sw_out[16]
  PIN sw_out[17]
    DIRECTION OUTPUT ;
    USE SIGNAL ;
    ANTENNADIFFAREA 0.440000 ;
    PORT
      LAYER Metal2 ;
        RECT 473.760 0.000 474.320 0.560 ;
    END
  END sw_out[17]
  PIN sw_out[18]
    DIRECTION OUTPUT ;
    USE SIGNAL ;
    ANTENNADIFFAREA 0.440000 ;
    PORT
      LAYER Metal2 ;
        RECT 477.120 0.000 477.680 0.560 ;
    END
  END sw_out[18]
  PIN sw_out[19]
    DIRECTION OUTPUT ;
    USE SIGNAL ;
    ANTENNADIFFAREA 0.440000 ;
    PORT
      LAYER Metal2 ;
        RECT 480.480 0.000 481.040 0.560 ;
    END
  END sw_out[19]
  PIN sw_out[1]
    DIRECTION OUTPUT ;
    USE SIGNAL ;
    ANTENNADIFFAREA 0.440000 ;
    PORT
      LAYER Metal2 ;
        RECT 420.000 0.000 420.560 0.560 ;
    END
  END sw_out[1]
  PIN sw_out[20]
    DIRECTION OUTPUT ;
    USE SIGNAL ;
    ANTENNADIFFAREA 0.440000 ;
    PORT
      LAYER Metal2 ;
        RECT 483.840 0.000 484.400 0.560 ;
    END
  END sw_out[20]
  PIN sw_out[21]
    DIRECTION OUTPUT ;
    USE SIGNAL ;
    ANTENNADIFFAREA 0.440000 ;
    PORT
      LAYER Metal2 ;
        RECT 487.200 0.000 487.760 0.560 ;
    END
  END sw_out[21]
  PIN sw_out[22]
    DIRECTION OUTPUT ;
    USE SIGNAL ;
    ANTENNADIFFAREA 0.440000 ;
    PORT
      LAYER Metal2 ;
        RECT 490.560 0.000 491.120 0.560 ;
    END
  END sw_out[22]
  PIN sw_out[23]
    DIRECTION OUTPUT ;
    USE SIGNAL ;
    ANTENNADIFFAREA 0.440000 ;
    PORT
      LAYER Metal2 ;
        RECT 493.920 0.000 494.480 0.560 ;
    END
  END sw_out[23]
  PIN sw_out[24]
    DIRECTION OUTPUT ;
    USE SIGNAL ;
    ANTENNADIFFAREA 0.440000 ;
    PORT
      LAYER Metal2 ;
        RECT 497.280 0.000 497.840 0.560 ;
    END
  END sw_out[24]
  PIN sw_out[25]
    DIRECTION OUTPUT ;
    USE SIGNAL ;
    ANTENNADIFFAREA 0.440000 ;
    PORT
      LAYER Metal2 ;
        RECT 500.640 0.000 501.200 0.560 ;
    END
  END sw_out[25]
  PIN sw_out[26]
    DIRECTION OUTPUT ;
    USE SIGNAL ;
    ANTENNADIFFAREA 0.440000 ;
    PORT
      LAYER Metal2 ;
        RECT 504.000 0.000 504.560 0.560 ;
    END
  END sw_out[26]
  PIN sw_out[27]
    DIRECTION OUTPUT ;
    USE SIGNAL ;
    ANTENNADIFFAREA 0.440000 ;
    PORT
      LAYER Metal2 ;
        RECT 507.360 0.000 507.920 0.560 ;
    END
  END sw_out[27]
  PIN sw_out[28]
    DIRECTION OUTPUT ;
    USE SIGNAL ;
    ANTENNADIFFAREA 0.440000 ;
    PORT
      LAYER Metal2 ;
        RECT 510.720 0.000 511.280 0.560 ;
    END
  END sw_out[28]
  PIN sw_out[29]
    DIRECTION OUTPUT ;
    USE SIGNAL ;
    ANTENNADIFFAREA 0.440000 ;
    PORT
      LAYER Metal2 ;
        RECT 514.080 0.000 514.640 0.560 ;
    END
  END sw_out[29]
  PIN sw_out[2]
    DIRECTION OUTPUT ;
    USE SIGNAL ;
    ANTENNADIFFAREA 0.440000 ;
    PORT
      LAYER Metal2 ;
        RECT 423.360 0.000 423.920 0.560 ;
    END
  END sw_out[2]
  PIN sw_out[30]
    DIRECTION OUTPUT ;
    USE SIGNAL ;
    ANTENNADIFFAREA 0.440000 ;
    PORT
      LAYER Metal2 ;
        RECT 517.440 0.000 518.000 0.560 ;
    END
  END sw_out[30]
  PIN sw_out[31]
    DIRECTION OUTPUT ;
    USE SIGNAL ;
    ANTENNADIFFAREA 0.440000 ;
    PORT
      LAYER Metal2 ;
        RECT 520.800 0.000 521.360 0.560 ;
    END
  END sw_out[31]
  PIN sw_out[32]
    DIRECTION OUTPUT ;
    USE SIGNAL ;
    ANTENNADIFFAREA 0.440000 ;
    PORT
      LAYER Metal2 ;
        RECT 524.160 0.000 524.720 0.560 ;
    END
  END sw_out[32]
  PIN sw_out[33]
    DIRECTION OUTPUT ;
    USE SIGNAL ;
    ANTENNADIFFAREA 0.440000 ;
    PORT
      LAYER Metal2 ;
        RECT 527.520 0.000 528.080 0.560 ;
    END
  END sw_out[33]
  PIN sw_out[3]
    DIRECTION OUTPUT ;
    USE SIGNAL ;
    ANTENNADIFFAREA 0.440000 ;
    PORT
      LAYER Metal2 ;
        RECT 426.720 0.000 427.280 0.560 ;
    END
  END sw_out[3]
  PIN sw_out[4]
    DIRECTION OUTPUT ;
    USE SIGNAL ;
    ANTENNADIFFAREA 0.440000 ;
    PORT
      LAYER Metal2 ;
        RECT 430.080 0.000 430.640 0.560 ;
    END
  END sw_out[4]
  PIN sw_out[5]
    DIRECTION OUTPUT ;
    USE SIGNAL ;
    ANTENNADIFFAREA 0.440000 ;
    PORT
      LAYER Metal2 ;
        RECT 433.440 0.000 434.000 0.560 ;
    END
  END sw_out[5]
  PIN sw_out[6]
    DIRECTION OUTPUT ;
    USE SIGNAL ;
    ANTENNADIFFAREA 0.440000 ;
    PORT
      LAYER Metal2 ;
        RECT 436.800 0.000 437.360 0.560 ;
    END
  END sw_out[6]
  PIN sw_out[7]
    DIRECTION OUTPUT ;
    USE SIGNAL ;
    ANTENNADIFFAREA 0.440000 ;
    PORT
      LAYER Metal2 ;
        RECT 440.160 0.000 440.720 0.560 ;
    END
  END sw_out[7]
  PIN sw_out[8]
    DIRECTION OUTPUT ;
    USE SIGNAL ;
    ANTENNADIFFAREA 0.440000 ;
    PORT
      LAYER Metal2 ;
        RECT 443.520 0.000 444.080 0.560 ;
    END
  END sw_out[8]
  PIN sw_out[9]
    DIRECTION OUTPUT ;
    USE SIGNAL ;
    ANTENNADIFFAREA 0.440000 ;
    PORT
      LAYER Metal2 ;
        RECT 446.880 0.000 447.440 0.560 ;
    END
  END sw_out[9]
  PIN west_in[0]
    DIRECTION INPUT ;
    USE SIGNAL ;
    ANTENNAGATEAREA 2.665600 ;
    PORT
      LAYER Metal3 ;
        RECT 0.000 11.200 0.560 11.760 ;
    END
  END west_in[0]
  PIN west_in[10]
    DIRECTION INPUT ;
    USE SIGNAL ;
    ANTENNAGATEAREA 2.665600 ;
    PORT
      LAYER Metal3 ;
        RECT 0.000 67.200 0.560 67.760 ;
    END
  END west_in[10]
  PIN west_in[11]
    DIRECTION INPUT ;
    USE SIGNAL ;
    ANTENNAGATEAREA 2.665600 ;
    PORT
      LAYER Metal3 ;
        RECT 0.000 72.800 0.560 73.360 ;
    END
  END west_in[11]
  PIN west_in[12]
    DIRECTION INPUT ;
    USE SIGNAL ;
    ANTENNAGATEAREA 2.665600 ;
    PORT
      LAYER Metal3 ;
        RECT 0.000 78.400 0.560 78.960 ;
    END
  END west_in[12]
  PIN west_in[13]
    DIRECTION INPUT ;
    USE SIGNAL ;
    ANTENNAGATEAREA 2.665600 ;
    PORT
      LAYER Metal3 ;
        RECT 0.000 84.000 0.560 84.560 ;
    END
  END west_in[13]
  PIN west_in[14]
    DIRECTION INPUT ;
    USE SIGNAL ;
    ANTENNAGATEAREA 2.665600 ;
    PORT
      LAYER Metal3 ;
        RECT 0.000 89.600 0.560 90.160 ;
    END
  END west_in[14]
  PIN west_in[15]
    DIRECTION INPUT ;
    USE SIGNAL ;
    ANTENNAGATEAREA 2.665600 ;
    PORT
      LAYER Metal3 ;
        RECT 0.000 95.200 0.560 95.760 ;
    END
  END west_in[15]
  PIN west_in[16]
    DIRECTION INPUT ;
    USE SIGNAL ;
    ANTENNAGATEAREA 2.665600 ;
    PORT
      LAYER Metal3 ;
        RECT 0.000 100.800 0.560 101.360 ;
    END
  END west_in[16]
  PIN west_in[17]
    DIRECTION INPUT ;
    USE SIGNAL ;
    ANTENNAGATEAREA 2.665600 ;
    PORT
      LAYER Metal3 ;
        RECT 0.000 106.400 0.560 106.960 ;
    END
  END west_in[17]
  PIN west_in[18]
    DIRECTION INPUT ;
    USE SIGNAL ;
    ANTENNAGATEAREA 2.665600 ;
    PORT
      LAYER Metal3 ;
        RECT 0.000 112.000 0.560 112.560 ;
    END
  END west_in[18]
  PIN west_in[19]
    DIRECTION INPUT ;
    USE SIGNAL ;
    ANTENNAGATEAREA 2.665600 ;
    PORT
      LAYER Metal3 ;
        RECT 0.000 117.600 0.560 118.160 ;
    END
  END west_in[19]
  PIN west_in[1]
    DIRECTION INPUT ;
    USE SIGNAL ;
    ANTENNAGATEAREA 2.665600 ;
    PORT
      LAYER Metal3 ;
        RECT 0.000 16.800 0.560 17.360 ;
    END
  END west_in[1]
  PIN west_in[20]
    DIRECTION INPUT ;
    USE SIGNAL ;
    ANTENNAGATEAREA 2.665600 ;
    PORT
      LAYER Metal3 ;
        RECT 0.000 123.200 0.560 123.760 ;
    END
  END west_in[20]
  PIN west_in[21]
    DIRECTION INPUT ;
    USE SIGNAL ;
    ANTENNAGATEAREA 2.665600 ;
    PORT
      LAYER Metal3 ;
        RECT 0.000 128.800 0.560 129.360 ;
    END
  END west_in[21]
  PIN west_in[22]
    DIRECTION INPUT ;
    USE SIGNAL ;
    ANTENNAGATEAREA 2.665600 ;
    PORT
      LAYER Metal3 ;
        RECT 0.000 134.400 0.560 134.960 ;
    END
  END west_in[22]
  PIN west_in[23]
    DIRECTION INPUT ;
    USE SIGNAL ;
    ANTENNAGATEAREA 2.665600 ;
    PORT
      LAYER Metal3 ;
        RECT 0.000 140.000 0.560 140.560 ;
    END
  END west_in[23]
  PIN west_in[24]
    DIRECTION INPUT ;
    USE SIGNAL ;
    ANTENNAGATEAREA 2.665600 ;
    PORT
      LAYER Metal3 ;
        RECT 0.000 145.600 0.560 146.160 ;
    END
  END west_in[24]
  PIN west_in[25]
    DIRECTION INPUT ;
    USE SIGNAL ;
    ANTENNAGATEAREA 2.665600 ;
    PORT
      LAYER Metal3 ;
        RECT 0.000 151.200 0.560 151.760 ;
    END
  END west_in[25]
  PIN west_in[26]
    DIRECTION INPUT ;
    USE SIGNAL ;
    ANTENNAGATEAREA 2.665600 ;
    PORT
      LAYER Metal3 ;
        RECT 0.000 156.800 0.560 157.360 ;
    END
  END west_in[26]
  PIN west_in[27]
    DIRECTION INPUT ;
    USE SIGNAL ;
    ANTENNAGATEAREA 2.665600 ;
    PORT
      LAYER Metal3 ;
        RECT 0.000 162.400 0.560 162.960 ;
    END
  END west_in[27]
  PIN west_in[28]
    DIRECTION INPUT ;
    USE SIGNAL ;
    ANTENNAGATEAREA 2.665600 ;
    PORT
      LAYER Metal3 ;
        RECT 0.000 168.000 0.560 168.560 ;
    END
  END west_in[28]
  PIN west_in[29]
    DIRECTION INPUT ;
    USE SIGNAL ;
    ANTENNAGATEAREA 2.665600 ;
    PORT
      LAYER Metal3 ;
        RECT 0.000 173.600 0.560 174.160 ;
    END
  END west_in[29]
  PIN west_in[2]
    DIRECTION INPUT ;
    USE SIGNAL ;
    ANTENNAGATEAREA 2.665600 ;
    PORT
      LAYER Metal3 ;
        RECT 0.000 22.400 0.560 22.960 ;
    END
  END west_in[2]
  PIN west_in[30]
    DIRECTION INPUT ;
    USE SIGNAL ;
    ANTENNAGATEAREA 2.665600 ;
    PORT
      LAYER Metal3 ;
        RECT 0.000 179.200 0.560 179.760 ;
    END
  END west_in[30]
  PIN west_in[31]
    DIRECTION INPUT ;
    USE SIGNAL ;
    ANTENNAGATEAREA 2.665600 ;
    PORT
      LAYER Metal3 ;
        RECT 0.000 184.800 0.560 185.360 ;
    END
  END west_in[31]
  PIN west_in[32]
    DIRECTION INPUT ;
    USE SIGNAL ;
    ANTENNAGATEAREA 2.665600 ;
    PORT
      LAYER Metal3 ;
        RECT 0.000 190.400 0.560 190.960 ;
    END
  END west_in[32]
  PIN west_in[33]
    DIRECTION INPUT ;
    USE SIGNAL ;
    ANTENNAGATEAREA 2.665600 ;
    PORT
      LAYER Metal3 ;
        RECT 0.000 196.000 0.560 196.560 ;
    END
  END west_in[33]
  PIN west_in[3]
    DIRECTION INPUT ;
    USE SIGNAL ;
    ANTENNAGATEAREA 2.665600 ;
    PORT
      LAYER Metal3 ;
        RECT 0.000 28.000 0.560 28.560 ;
    END
  END west_in[3]
  PIN west_in[4]
    DIRECTION INPUT ;
    USE SIGNAL ;
    ANTENNAGATEAREA 2.665600 ;
    PORT
      LAYER Metal3 ;
        RECT 0.000 33.600 0.560 34.160 ;
    END
  END west_in[4]
  PIN west_in[5]
    DIRECTION INPUT ;
    USE SIGNAL ;
    ANTENNAGATEAREA 2.665600 ;
    PORT
      LAYER Metal3 ;
        RECT 0.000 39.200 0.560 39.760 ;
    END
  END west_in[5]
  PIN west_in[6]
    DIRECTION INPUT ;
    USE SIGNAL ;
    ANTENNAGATEAREA 2.665600 ;
    PORT
      LAYER Metal3 ;
        RECT 0.000 44.800 0.560 45.360 ;
    END
  END west_in[6]
  PIN west_in[7]
    DIRECTION INPUT ;
    USE SIGNAL ;
    ANTENNAGATEAREA 2.665600 ;
    PORT
      LAYER Metal3 ;
        RECT 0.000 50.400 0.560 50.960 ;
    END
  END west_in[7]
  PIN west_in[8]
    DIRECTION INPUT ;
    USE SIGNAL ;
    ANTENNAGATEAREA 2.665600 ;
    PORT
      LAYER Metal3 ;
        RECT 0.000 56.000 0.560 56.560 ;
    END
  END west_in[8]
  PIN west_in[9]
    DIRECTION INPUT ;
    USE SIGNAL ;
    ANTENNAGATEAREA 2.665600 ;
    PORT
      LAYER Metal3 ;
        RECT 0.000 61.600 0.560 62.160 ;
    END
  END west_in[9]
  PIN west_out[0]
    DIRECTION OUTPUT ;
    USE SIGNAL ;
    ANTENNADIFFAREA 7.461300 ;
    PORT
      LAYER Metal3 ;
        RECT 0.000 201.600 0.560 202.160 ;
    END
  END west_out[0]
  PIN west_out[10]
    DIRECTION OUTPUT ;
    USE SIGNAL ;
    ANTENNADIFFAREA 7.461300 ;
    PORT
      LAYER Metal3 ;
        RECT 0.000 257.600 0.560 258.160 ;
    END
  END west_out[10]
  PIN west_out[11]
    DIRECTION OUTPUT ;
    USE SIGNAL ;
    ANTENNADIFFAREA 7.461300 ;
    PORT
      LAYER Metal3 ;
        RECT 0.000 263.200 0.560 263.760 ;
    END
  END west_out[11]
  PIN west_out[12]
    DIRECTION OUTPUT ;
    USE SIGNAL ;
    ANTENNADIFFAREA 7.461300 ;
    PORT
      LAYER Metal3 ;
        RECT 0.000 268.800 0.560 269.360 ;
    END
  END west_out[12]
  PIN west_out[13]
    DIRECTION OUTPUT ;
    USE SIGNAL ;
    ANTENNADIFFAREA 7.461300 ;
    PORT
      LAYER Metal3 ;
        RECT 0.000 274.400 0.560 274.960 ;
    END
  END west_out[13]
  PIN west_out[14]
    DIRECTION OUTPUT ;
    USE SIGNAL ;
    ANTENNADIFFAREA 7.461300 ;
    PORT
      LAYER Metal3 ;
        RECT 0.000 280.000 0.560 280.560 ;
    END
  END west_out[14]
  PIN west_out[15]
    DIRECTION OUTPUT ;
    USE SIGNAL ;
    ANTENNADIFFAREA 7.461300 ;
    PORT
      LAYER Metal3 ;
        RECT 0.000 285.600 0.560 286.160 ;
    END
  END west_out[15]
  PIN west_out[16]
    DIRECTION OUTPUT ;
    USE SIGNAL ;
    ANTENNADIFFAREA 7.461300 ;
    PORT
      LAYER Metal3 ;
        RECT 0.000 291.200 0.560 291.760 ;
    END
  END west_out[16]
  PIN west_out[17]
    DIRECTION OUTPUT ;
    USE SIGNAL ;
    ANTENNADIFFAREA 7.461300 ;
    PORT
      LAYER Metal3 ;
        RECT 0.000 296.800 0.560 297.360 ;
    END
  END west_out[17]
  PIN west_out[18]
    DIRECTION OUTPUT ;
    USE SIGNAL ;
    ANTENNADIFFAREA 7.461300 ;
    PORT
      LAYER Metal3 ;
        RECT 0.000 302.400 0.560 302.960 ;
    END
  END west_out[18]
  PIN west_out[19]
    DIRECTION OUTPUT ;
    USE SIGNAL ;
    ANTENNADIFFAREA 7.461300 ;
    PORT
      LAYER Metal3 ;
        RECT 0.000 308.000 0.560 308.560 ;
    END
  END west_out[19]
  PIN west_out[1]
    DIRECTION OUTPUT ;
    USE SIGNAL ;
    ANTENNADIFFAREA 7.461300 ;
    PORT
      LAYER Metal3 ;
        RECT 0.000 207.200 0.560 207.760 ;
    END
  END west_out[1]
  PIN west_out[20]
    DIRECTION OUTPUT ;
    USE SIGNAL ;
    ANTENNADIFFAREA 7.461300 ;
    PORT
      LAYER Metal3 ;
        RECT 0.000 313.600 0.560 314.160 ;
    END
  END west_out[20]
  PIN west_out[21]
    DIRECTION OUTPUT ;
    USE SIGNAL ;
    ANTENNADIFFAREA 7.461300 ;
    PORT
      LAYER Metal3 ;
        RECT 0.000 319.200 0.560 319.760 ;
    END
  END west_out[21]
  PIN west_out[22]
    DIRECTION OUTPUT ;
    USE SIGNAL ;
    ANTENNADIFFAREA 7.461300 ;
    PORT
      LAYER Metal3 ;
        RECT 0.000 324.800 0.560 325.360 ;
    END
  END west_out[22]
  PIN west_out[23]
    DIRECTION OUTPUT ;
    USE SIGNAL ;
    ANTENNADIFFAREA 7.461300 ;
    PORT
      LAYER Metal3 ;
        RECT 0.000 330.400 0.560 330.960 ;
    END
  END west_out[23]
  PIN west_out[24]
    DIRECTION OUTPUT ;
    USE SIGNAL ;
    ANTENNADIFFAREA 7.461300 ;
    PORT
      LAYER Metal3 ;
        RECT 0.000 336.000 0.560 336.560 ;
    END
  END west_out[24]
  PIN west_out[25]
    DIRECTION OUTPUT ;
    USE SIGNAL ;
    ANTENNADIFFAREA 7.461300 ;
    PORT
      LAYER Metal3 ;
        RECT 0.000 341.600 0.560 342.160 ;
    END
  END west_out[25]
  PIN west_out[26]
    DIRECTION OUTPUT ;
    USE SIGNAL ;
    ANTENNADIFFAREA 7.461300 ;
    PORT
      LAYER Metal3 ;
        RECT 0.000 347.200 0.560 347.760 ;
    END
  END west_out[26]
  PIN west_out[27]
    DIRECTION OUTPUT ;
    USE SIGNAL ;
    ANTENNADIFFAREA 7.461300 ;
    PORT
      LAYER Metal3 ;
        RECT 0.000 352.800 0.560 353.360 ;
    END
  END west_out[27]
  PIN west_out[28]
    DIRECTION OUTPUT ;
    USE SIGNAL ;
    ANTENNADIFFAREA 7.461300 ;
    PORT
      LAYER Metal3 ;
        RECT 0.000 358.400 0.560 358.960 ;
    END
  END west_out[28]
  PIN west_out[29]
    DIRECTION OUTPUT ;
    USE SIGNAL ;
    ANTENNADIFFAREA 7.461300 ;
    PORT
      LAYER Metal3 ;
        RECT 0.000 364.000 0.560 364.560 ;
    END
  END west_out[29]
  PIN west_out[2]
    DIRECTION OUTPUT ;
    USE SIGNAL ;
    ANTENNADIFFAREA 7.461300 ;
    PORT
      LAYER Metal3 ;
        RECT 0.000 212.800 0.560 213.360 ;
    END
  END west_out[2]
  PIN west_out[30]
    DIRECTION OUTPUT ;
    USE SIGNAL ;
    ANTENNADIFFAREA 7.461300 ;
    PORT
      LAYER Metal3 ;
        RECT 0.000 369.600 0.560 370.160 ;
    END
  END west_out[30]
  PIN west_out[31]
    DIRECTION OUTPUT ;
    USE SIGNAL ;
    ANTENNADIFFAREA 7.461300 ;
    PORT
      LAYER Metal3 ;
        RECT 0.000 375.200 0.560 375.760 ;
    END
  END west_out[31]
  PIN west_out[32]
    DIRECTION OUTPUT ;
    USE SIGNAL ;
    ANTENNADIFFAREA 7.461300 ;
    PORT
      LAYER Metal3 ;
        RECT 0.000 380.800 0.560 381.360 ;
    END
  END west_out[32]
  PIN west_out[33]
    DIRECTION OUTPUT ;
    USE SIGNAL ;
    ANTENNADIFFAREA 7.461300 ;
    PORT
      LAYER Metal3 ;
        RECT 0.000 386.400 0.560 386.960 ;
    END
  END west_out[33]
  PIN west_out[3]
    DIRECTION OUTPUT ;
    USE SIGNAL ;
    ANTENNADIFFAREA 7.461300 ;
    PORT
      LAYER Metal3 ;
        RECT 0.000 218.400 0.560 218.960 ;
    END
  END west_out[3]
  PIN west_out[4]
    DIRECTION OUTPUT ;
    USE SIGNAL ;
    ANTENNADIFFAREA 7.461300 ;
    PORT
      LAYER Metal3 ;
        RECT 0.000 224.000 0.560 224.560 ;
    END
  END west_out[4]
  PIN west_out[5]
    DIRECTION OUTPUT ;
    USE SIGNAL ;
    ANTENNADIFFAREA 7.461300 ;
    PORT
      LAYER Metal3 ;
        RECT 0.000 229.600 0.560 230.160 ;
    END
  END west_out[5]
  PIN west_out[6]
    DIRECTION OUTPUT ;
    USE SIGNAL ;
    ANTENNADIFFAREA 7.461300 ;
    PORT
      LAYER Metal3 ;
        RECT 0.000 235.200 0.560 235.760 ;
    END
  END west_out[6]
  PIN west_out[7]
    DIRECTION OUTPUT ;
    USE SIGNAL ;
    ANTENNADIFFAREA 7.461300 ;
    PORT
      LAYER Metal3 ;
        RECT 0.000 240.800 0.560 241.360 ;
    END
  END west_out[7]
  PIN west_out[8]
    DIRECTION OUTPUT ;
    USE SIGNAL ;
    ANTENNADIFFAREA 7.461300 ;
    PORT
      LAYER Metal3 ;
        RECT 0.000 246.400 0.560 246.960 ;
    END
  END west_out[8]
  PIN west_out[9]
    DIRECTION OUTPUT ;
    USE SIGNAL ;
    ANTENNADIFFAREA 7.461300 ;
    PORT
      LAYER Metal3 ;
        RECT 0.000 252.000 0.560 252.560 ;
    END
  END west_out[9]
  OBS
      LAYER Nwell ;
        RECT 9.650 11.330 770.430 768.750 ;
      LAYER Metal1 ;
        RECT 10.080 11.460 770.000 768.620 ;
      LAYER Metal2 ;
        RECT 0.140 779.140 10.900 779.940 ;
        RECT 12.060 779.140 16.500 779.940 ;
        RECT 17.660 779.140 22.100 779.940 ;
        RECT 23.260 779.140 27.700 779.940 ;
        RECT 28.860 779.140 33.300 779.940 ;
        RECT 34.460 779.140 38.900 779.940 ;
        RECT 40.060 779.140 44.500 779.940 ;
        RECT 45.660 779.140 50.100 779.940 ;
        RECT 51.260 779.140 55.700 779.940 ;
        RECT 56.860 779.140 61.300 779.940 ;
        RECT 62.460 779.140 66.900 779.940 ;
        RECT 68.060 779.140 72.500 779.940 ;
        RECT 73.660 779.140 78.100 779.940 ;
        RECT 79.260 779.140 83.700 779.940 ;
        RECT 84.860 779.140 89.300 779.940 ;
        RECT 90.460 779.140 94.900 779.940 ;
        RECT 96.060 779.140 100.500 779.940 ;
        RECT 101.660 779.140 106.100 779.940 ;
        RECT 107.260 779.140 111.700 779.940 ;
        RECT 112.860 779.140 117.300 779.940 ;
        RECT 118.460 779.140 122.900 779.940 ;
        RECT 124.060 779.140 128.500 779.940 ;
        RECT 129.660 779.140 134.100 779.940 ;
        RECT 135.260 779.140 139.700 779.940 ;
        RECT 140.860 779.140 145.300 779.940 ;
        RECT 146.460 779.140 150.900 779.940 ;
        RECT 152.060 779.140 156.500 779.940 ;
        RECT 157.660 779.140 162.100 779.940 ;
        RECT 163.260 779.140 167.700 779.940 ;
        RECT 168.860 779.140 173.300 779.940 ;
        RECT 174.460 779.140 178.900 779.940 ;
        RECT 180.060 779.140 184.500 779.940 ;
        RECT 185.660 779.140 190.100 779.940 ;
        RECT 191.260 779.140 195.700 779.940 ;
        RECT 196.860 779.140 201.300 779.940 ;
        RECT 202.460 779.140 206.900 779.940 ;
        RECT 208.060 779.140 212.500 779.940 ;
        RECT 213.660 779.140 218.100 779.940 ;
        RECT 219.260 779.140 223.700 779.940 ;
        RECT 224.860 779.140 229.300 779.940 ;
        RECT 230.460 779.140 234.900 779.940 ;
        RECT 236.060 779.140 240.500 779.940 ;
        RECT 241.660 779.140 246.100 779.940 ;
        RECT 247.260 779.140 251.700 779.940 ;
        RECT 252.860 779.140 257.300 779.940 ;
        RECT 258.460 779.140 262.900 779.940 ;
        RECT 264.060 779.140 268.500 779.940 ;
        RECT 269.660 779.140 274.100 779.940 ;
        RECT 275.260 779.140 279.700 779.940 ;
        RECT 280.860 779.140 285.300 779.940 ;
        RECT 286.460 779.140 290.900 779.940 ;
        RECT 292.060 779.140 296.500 779.940 ;
        RECT 297.660 779.140 302.100 779.940 ;
        RECT 303.260 779.140 307.700 779.940 ;
        RECT 308.860 779.140 313.300 779.940 ;
        RECT 314.460 779.140 318.900 779.940 ;
        RECT 320.060 779.140 324.500 779.940 ;
        RECT 325.660 779.140 330.100 779.940 ;
        RECT 331.260 779.140 335.700 779.940 ;
        RECT 336.860 779.140 341.300 779.940 ;
        RECT 342.460 779.140 346.900 779.940 ;
        RECT 348.060 779.140 352.500 779.940 ;
        RECT 353.660 779.140 358.100 779.940 ;
        RECT 359.260 779.140 363.700 779.940 ;
        RECT 364.860 779.140 369.300 779.940 ;
        RECT 370.460 779.140 374.900 779.940 ;
        RECT 376.060 779.140 380.500 779.940 ;
        RECT 381.660 779.140 386.100 779.940 ;
        RECT 387.260 779.140 391.700 779.940 ;
        RECT 392.860 779.140 397.300 779.940 ;
        RECT 398.460 779.140 402.900 779.940 ;
        RECT 404.060 779.140 408.500 779.940 ;
        RECT 409.660 779.140 414.100 779.940 ;
        RECT 415.260 779.140 419.700 779.940 ;
        RECT 420.860 779.140 425.300 779.940 ;
        RECT 426.460 779.140 430.900 779.940 ;
        RECT 432.060 779.140 436.500 779.940 ;
        RECT 437.660 779.140 442.100 779.940 ;
        RECT 443.260 779.140 447.700 779.940 ;
        RECT 448.860 779.140 453.300 779.940 ;
        RECT 454.460 779.140 458.900 779.940 ;
        RECT 460.060 779.140 464.500 779.940 ;
        RECT 465.660 779.140 470.100 779.940 ;
        RECT 471.260 779.140 475.700 779.940 ;
        RECT 476.860 779.140 481.300 779.940 ;
        RECT 482.460 779.140 486.900 779.940 ;
        RECT 488.060 779.140 492.500 779.940 ;
        RECT 493.660 779.140 498.100 779.940 ;
        RECT 499.260 779.140 503.700 779.940 ;
        RECT 504.860 779.140 509.300 779.940 ;
        RECT 510.460 779.140 514.900 779.940 ;
        RECT 516.060 779.140 520.500 779.940 ;
        RECT 521.660 779.140 526.100 779.940 ;
        RECT 527.260 779.140 531.700 779.940 ;
        RECT 532.860 779.140 537.300 779.940 ;
        RECT 538.460 779.140 542.900 779.940 ;
        RECT 544.060 779.140 548.500 779.940 ;
        RECT 549.660 779.140 554.100 779.940 ;
        RECT 555.260 779.140 559.700 779.940 ;
        RECT 560.860 779.140 565.300 779.940 ;
        RECT 566.460 779.140 570.900 779.940 ;
        RECT 572.060 779.140 576.500 779.940 ;
        RECT 577.660 779.140 582.100 779.940 ;
        RECT 583.260 779.140 587.700 779.940 ;
        RECT 588.860 779.140 593.300 779.940 ;
        RECT 594.460 779.140 598.900 779.940 ;
        RECT 600.060 779.140 604.500 779.940 ;
        RECT 605.660 779.140 610.100 779.940 ;
        RECT 611.260 779.140 615.700 779.940 ;
        RECT 616.860 779.140 621.300 779.940 ;
        RECT 622.460 779.140 626.900 779.940 ;
        RECT 628.060 779.140 632.500 779.940 ;
        RECT 633.660 779.140 638.100 779.940 ;
        RECT 639.260 779.140 643.700 779.940 ;
        RECT 644.860 779.140 649.300 779.940 ;
        RECT 650.460 779.140 654.900 779.940 ;
        RECT 656.060 779.140 660.500 779.940 ;
        RECT 661.660 779.140 666.100 779.940 ;
        RECT 667.260 779.140 671.700 779.940 ;
        RECT 672.860 779.140 677.300 779.940 ;
        RECT 678.460 779.140 682.900 779.940 ;
        RECT 684.060 779.140 688.500 779.940 ;
        RECT 689.660 779.140 694.100 779.940 ;
        RECT 695.260 779.140 699.700 779.940 ;
        RECT 700.860 779.140 705.300 779.940 ;
        RECT 706.460 779.140 710.900 779.940 ;
        RECT 712.060 779.140 716.500 779.940 ;
        RECT 717.660 779.140 722.100 779.940 ;
        RECT 723.260 779.140 727.700 779.940 ;
        RECT 728.860 779.140 733.300 779.940 ;
        RECT 734.460 779.140 738.900 779.940 ;
        RECT 740.060 779.140 744.500 779.940 ;
        RECT 745.660 779.140 750.100 779.940 ;
        RECT 751.260 779.140 755.700 779.940 ;
        RECT 756.860 779.140 761.300 779.940 ;
        RECT 762.460 779.140 766.900 779.940 ;
        RECT 768.060 779.140 779.380 779.940 ;
        RECT 0.140 0.860 779.380 779.140 ;
        RECT 0.140 0.560 73.620 0.860 ;
        RECT 74.780 0.560 76.980 0.860 ;
        RECT 78.140 0.560 80.340 0.860 ;
        RECT 81.500 0.560 83.700 0.860 ;
        RECT 84.860 0.560 87.060 0.860 ;
        RECT 88.220 0.560 90.420 0.860 ;
        RECT 91.580 0.560 93.780 0.860 ;
        RECT 94.940 0.560 97.140 0.860 ;
        RECT 98.300 0.560 100.500 0.860 ;
        RECT 101.660 0.560 103.860 0.860 ;
        RECT 105.020 0.560 107.220 0.860 ;
        RECT 108.380 0.560 110.580 0.860 ;
        RECT 111.740 0.560 113.940 0.860 ;
        RECT 115.100 0.560 117.300 0.860 ;
        RECT 118.460 0.560 120.660 0.860 ;
        RECT 121.820 0.560 124.020 0.860 ;
        RECT 125.180 0.560 127.380 0.860 ;
        RECT 128.540 0.560 130.740 0.860 ;
        RECT 131.900 0.560 134.100 0.860 ;
        RECT 135.260 0.560 137.460 0.860 ;
        RECT 138.620 0.560 140.820 0.860 ;
        RECT 141.980 0.560 144.180 0.860 ;
        RECT 145.340 0.560 147.540 0.860 ;
        RECT 148.700 0.560 150.900 0.860 ;
        RECT 152.060 0.560 154.260 0.860 ;
        RECT 155.420 0.560 157.620 0.860 ;
        RECT 158.780 0.560 160.980 0.860 ;
        RECT 162.140 0.560 164.340 0.860 ;
        RECT 165.500 0.560 167.700 0.860 ;
        RECT 168.860 0.560 171.060 0.860 ;
        RECT 172.220 0.560 174.420 0.860 ;
        RECT 175.580 0.560 177.780 0.860 ;
        RECT 178.940 0.560 181.140 0.860 ;
        RECT 182.300 0.560 184.500 0.860 ;
        RECT 185.660 0.560 187.860 0.860 ;
        RECT 189.020 0.560 191.220 0.860 ;
        RECT 192.380 0.560 194.580 0.860 ;
        RECT 195.740 0.560 197.940 0.860 ;
        RECT 199.100 0.560 201.300 0.860 ;
        RECT 202.460 0.560 204.660 0.860 ;
        RECT 205.820 0.560 208.020 0.860 ;
        RECT 209.180 0.560 211.380 0.860 ;
        RECT 212.540 0.560 214.740 0.860 ;
        RECT 215.900 0.560 218.100 0.860 ;
        RECT 219.260 0.560 221.460 0.860 ;
        RECT 222.620 0.560 224.820 0.860 ;
        RECT 225.980 0.560 228.180 0.860 ;
        RECT 229.340 0.560 231.540 0.860 ;
        RECT 232.700 0.560 234.900 0.860 ;
        RECT 236.060 0.560 238.260 0.860 ;
        RECT 239.420 0.560 241.620 0.860 ;
        RECT 242.780 0.560 244.980 0.860 ;
        RECT 246.140 0.560 248.340 0.860 ;
        RECT 249.500 0.560 251.700 0.860 ;
        RECT 252.860 0.560 255.060 0.860 ;
        RECT 256.220 0.560 258.420 0.860 ;
        RECT 259.580 0.560 261.780 0.860 ;
        RECT 262.940 0.560 265.140 0.860 ;
        RECT 266.300 0.560 268.500 0.860 ;
        RECT 269.660 0.560 271.860 0.860 ;
        RECT 273.020 0.560 275.220 0.860 ;
        RECT 276.380 0.560 278.580 0.860 ;
        RECT 279.740 0.560 281.940 0.860 ;
        RECT 283.100 0.560 285.300 0.860 ;
        RECT 286.460 0.560 288.660 0.860 ;
        RECT 289.820 0.560 292.020 0.860 ;
        RECT 293.180 0.560 295.380 0.860 ;
        RECT 296.540 0.560 298.740 0.860 ;
        RECT 299.900 0.560 302.100 0.860 ;
        RECT 303.260 0.560 305.460 0.860 ;
        RECT 306.620 0.560 308.820 0.860 ;
        RECT 309.980 0.560 312.180 0.860 ;
        RECT 313.340 0.560 315.540 0.860 ;
        RECT 316.700 0.560 318.900 0.860 ;
        RECT 320.060 0.560 322.260 0.860 ;
        RECT 323.420 0.560 325.620 0.860 ;
        RECT 326.780 0.560 328.980 0.860 ;
        RECT 330.140 0.560 332.340 0.860 ;
        RECT 333.500 0.560 335.700 0.860 ;
        RECT 336.860 0.560 339.060 0.860 ;
        RECT 340.220 0.560 342.420 0.860 ;
        RECT 343.580 0.560 345.780 0.860 ;
        RECT 346.940 0.560 349.140 0.860 ;
        RECT 350.300 0.560 352.500 0.860 ;
        RECT 353.660 0.560 355.860 0.860 ;
        RECT 357.020 0.560 359.220 0.860 ;
        RECT 360.380 0.560 362.580 0.860 ;
        RECT 363.740 0.560 365.940 0.860 ;
        RECT 367.100 0.560 369.300 0.860 ;
        RECT 370.460 0.560 372.660 0.860 ;
        RECT 373.820 0.560 376.020 0.860 ;
        RECT 377.180 0.560 379.380 0.860 ;
        RECT 380.540 0.560 382.740 0.860 ;
        RECT 383.900 0.560 386.100 0.860 ;
        RECT 387.260 0.560 389.460 0.860 ;
        RECT 390.620 0.560 392.820 0.860 ;
        RECT 393.980 0.560 396.180 0.860 ;
        RECT 397.340 0.560 399.540 0.860 ;
        RECT 400.700 0.560 402.900 0.860 ;
        RECT 404.060 0.560 406.260 0.860 ;
        RECT 407.420 0.560 409.620 0.860 ;
        RECT 410.780 0.560 412.980 0.860 ;
        RECT 414.140 0.560 416.340 0.860 ;
        RECT 417.500 0.560 419.700 0.860 ;
        RECT 420.860 0.560 423.060 0.860 ;
        RECT 424.220 0.560 426.420 0.860 ;
        RECT 427.580 0.560 429.780 0.860 ;
        RECT 430.940 0.560 433.140 0.860 ;
        RECT 434.300 0.560 436.500 0.860 ;
        RECT 437.660 0.560 439.860 0.860 ;
        RECT 441.020 0.560 443.220 0.860 ;
        RECT 444.380 0.560 446.580 0.860 ;
        RECT 447.740 0.560 449.940 0.860 ;
        RECT 451.100 0.560 453.300 0.860 ;
        RECT 454.460 0.560 456.660 0.860 ;
        RECT 457.820 0.560 460.020 0.860 ;
        RECT 461.180 0.560 463.380 0.860 ;
        RECT 464.540 0.560 466.740 0.860 ;
        RECT 467.900 0.560 470.100 0.860 ;
        RECT 471.260 0.560 473.460 0.860 ;
        RECT 474.620 0.560 476.820 0.860 ;
        RECT 477.980 0.560 480.180 0.860 ;
        RECT 481.340 0.560 483.540 0.860 ;
        RECT 484.700 0.560 486.900 0.860 ;
        RECT 488.060 0.560 490.260 0.860 ;
        RECT 491.420 0.560 493.620 0.860 ;
        RECT 494.780 0.560 496.980 0.860 ;
        RECT 498.140 0.560 500.340 0.860 ;
        RECT 501.500 0.560 503.700 0.860 ;
        RECT 504.860 0.560 507.060 0.860 ;
        RECT 508.220 0.560 510.420 0.860 ;
        RECT 511.580 0.560 513.780 0.860 ;
        RECT 514.940 0.560 517.140 0.860 ;
        RECT 518.300 0.560 520.500 0.860 ;
        RECT 521.660 0.560 523.860 0.860 ;
        RECT 525.020 0.560 527.220 0.860 ;
        RECT 528.380 0.560 530.580 0.860 ;
        RECT 531.740 0.560 533.940 0.860 ;
        RECT 535.100 0.560 537.300 0.860 ;
        RECT 538.460 0.560 540.660 0.860 ;
        RECT 541.820 0.560 544.020 0.860 ;
        RECT 545.180 0.560 547.380 0.860 ;
        RECT 548.540 0.560 550.740 0.860 ;
        RECT 551.900 0.560 554.100 0.860 ;
        RECT 555.260 0.560 557.460 0.860 ;
        RECT 558.620 0.560 560.820 0.860 ;
        RECT 561.980 0.560 564.180 0.860 ;
        RECT 565.340 0.560 567.540 0.860 ;
        RECT 568.700 0.560 570.900 0.860 ;
        RECT 572.060 0.560 574.260 0.860 ;
        RECT 575.420 0.560 577.620 0.860 ;
        RECT 578.780 0.560 580.980 0.860 ;
        RECT 582.140 0.560 584.340 0.860 ;
        RECT 585.500 0.560 587.700 0.860 ;
        RECT 588.860 0.560 591.060 0.860 ;
        RECT 592.220 0.560 594.420 0.860 ;
        RECT 595.580 0.560 597.780 0.860 ;
        RECT 598.940 0.560 601.140 0.860 ;
        RECT 602.300 0.560 604.500 0.860 ;
        RECT 605.660 0.560 607.860 0.860 ;
        RECT 609.020 0.560 611.220 0.860 ;
        RECT 612.380 0.560 614.580 0.860 ;
        RECT 615.740 0.560 617.940 0.860 ;
        RECT 619.100 0.560 621.300 0.860 ;
        RECT 622.460 0.560 624.660 0.860 ;
        RECT 625.820 0.560 628.020 0.860 ;
        RECT 629.180 0.560 631.380 0.860 ;
        RECT 632.540 0.560 634.740 0.860 ;
        RECT 635.900 0.560 638.100 0.860 ;
        RECT 639.260 0.560 641.460 0.860 ;
        RECT 642.620 0.560 644.820 0.860 ;
        RECT 645.980 0.560 648.180 0.860 ;
        RECT 649.340 0.560 651.540 0.860 ;
        RECT 652.700 0.560 654.900 0.860 ;
        RECT 656.060 0.560 658.260 0.860 ;
        RECT 659.420 0.560 661.620 0.860 ;
        RECT 662.780 0.560 664.980 0.860 ;
        RECT 666.140 0.560 668.340 0.860 ;
        RECT 669.500 0.560 671.700 0.860 ;
        RECT 672.860 0.560 675.060 0.860 ;
        RECT 676.220 0.560 678.420 0.860 ;
        RECT 679.580 0.560 681.780 0.860 ;
        RECT 682.940 0.560 685.140 0.860 ;
        RECT 686.300 0.560 688.500 0.860 ;
        RECT 689.660 0.560 691.860 0.860 ;
        RECT 693.020 0.560 695.220 0.860 ;
        RECT 696.380 0.560 698.580 0.860 ;
        RECT 699.740 0.560 701.940 0.860 ;
        RECT 703.100 0.560 705.300 0.860 ;
        RECT 706.460 0.560 779.380 0.860 ;
      LAYER Metal3 ;
        RECT 0.560 768.060 779.940 779.380 ;
        RECT 0.860 766.900 779.140 768.060 ;
        RECT 0.560 762.460 779.940 766.900 ;
        RECT 0.860 761.300 779.140 762.460 ;
        RECT 0.560 756.860 779.940 761.300 ;
        RECT 0.860 755.700 779.140 756.860 ;
        RECT 0.560 751.260 779.940 755.700 ;
        RECT 0.860 750.100 779.140 751.260 ;
        RECT 0.560 745.660 779.940 750.100 ;
        RECT 0.860 744.500 779.140 745.660 ;
        RECT 0.560 740.060 779.940 744.500 ;
        RECT 0.860 738.900 779.140 740.060 ;
        RECT 0.560 734.460 779.940 738.900 ;
        RECT 0.860 733.300 779.140 734.460 ;
        RECT 0.560 728.860 779.940 733.300 ;
        RECT 0.860 727.700 779.140 728.860 ;
        RECT 0.560 723.260 779.940 727.700 ;
        RECT 0.860 722.100 779.140 723.260 ;
        RECT 0.560 717.660 779.940 722.100 ;
        RECT 0.860 716.500 779.140 717.660 ;
        RECT 0.560 712.060 779.940 716.500 ;
        RECT 0.860 710.900 779.140 712.060 ;
        RECT 0.560 706.460 779.940 710.900 ;
        RECT 0.860 705.300 779.140 706.460 ;
        RECT 0.560 700.860 779.940 705.300 ;
        RECT 0.860 699.700 779.140 700.860 ;
        RECT 0.560 695.260 779.940 699.700 ;
        RECT 0.860 694.100 779.140 695.260 ;
        RECT 0.560 689.660 779.940 694.100 ;
        RECT 0.860 688.500 779.140 689.660 ;
        RECT 0.560 684.060 779.940 688.500 ;
        RECT 0.860 682.900 779.140 684.060 ;
        RECT 0.560 678.460 779.940 682.900 ;
        RECT 0.860 677.300 779.140 678.460 ;
        RECT 0.560 672.860 779.940 677.300 ;
        RECT 0.860 671.700 779.140 672.860 ;
        RECT 0.560 667.260 779.940 671.700 ;
        RECT 0.860 666.100 779.140 667.260 ;
        RECT 0.560 661.660 779.940 666.100 ;
        RECT 0.860 660.500 779.140 661.660 ;
        RECT 0.560 656.060 779.940 660.500 ;
        RECT 0.860 654.900 779.140 656.060 ;
        RECT 0.560 650.460 779.940 654.900 ;
        RECT 0.860 649.300 779.140 650.460 ;
        RECT 0.560 644.860 779.940 649.300 ;
        RECT 0.860 643.700 779.140 644.860 ;
        RECT 0.560 639.260 779.940 643.700 ;
        RECT 0.860 638.100 779.140 639.260 ;
        RECT 0.560 633.660 779.940 638.100 ;
        RECT 0.860 632.500 779.140 633.660 ;
        RECT 0.560 628.060 779.940 632.500 ;
        RECT 0.860 626.900 779.140 628.060 ;
        RECT 0.560 622.460 779.940 626.900 ;
        RECT 0.860 621.300 779.140 622.460 ;
        RECT 0.560 616.860 779.940 621.300 ;
        RECT 0.860 615.700 779.140 616.860 ;
        RECT 0.560 611.260 779.940 615.700 ;
        RECT 0.860 610.100 779.140 611.260 ;
        RECT 0.560 605.660 779.940 610.100 ;
        RECT 0.860 604.500 779.140 605.660 ;
        RECT 0.560 600.060 779.940 604.500 ;
        RECT 0.860 598.900 779.140 600.060 ;
        RECT 0.560 594.460 779.940 598.900 ;
        RECT 0.860 593.300 779.140 594.460 ;
        RECT 0.560 588.860 779.940 593.300 ;
        RECT 0.860 587.700 779.140 588.860 ;
        RECT 0.560 583.260 779.940 587.700 ;
        RECT 0.860 582.100 779.140 583.260 ;
        RECT 0.560 577.660 779.940 582.100 ;
        RECT 0.860 576.500 779.140 577.660 ;
        RECT 0.560 572.060 779.940 576.500 ;
        RECT 0.860 570.900 779.140 572.060 ;
        RECT 0.560 566.460 779.940 570.900 ;
        RECT 0.860 565.300 779.140 566.460 ;
        RECT 0.560 560.860 779.940 565.300 ;
        RECT 0.860 559.700 779.140 560.860 ;
        RECT 0.560 555.260 779.940 559.700 ;
        RECT 0.860 554.100 779.140 555.260 ;
        RECT 0.560 549.660 779.940 554.100 ;
        RECT 0.860 548.500 779.140 549.660 ;
        RECT 0.560 544.060 779.940 548.500 ;
        RECT 0.860 542.900 779.140 544.060 ;
        RECT 0.560 538.460 779.940 542.900 ;
        RECT 0.860 537.300 779.140 538.460 ;
        RECT 0.560 532.860 779.940 537.300 ;
        RECT 0.860 531.700 779.140 532.860 ;
        RECT 0.560 527.260 779.940 531.700 ;
        RECT 0.860 526.100 779.140 527.260 ;
        RECT 0.560 521.660 779.940 526.100 ;
        RECT 0.860 520.500 779.140 521.660 ;
        RECT 0.560 516.060 779.940 520.500 ;
        RECT 0.860 514.900 779.140 516.060 ;
        RECT 0.560 510.460 779.940 514.900 ;
        RECT 0.860 509.300 779.140 510.460 ;
        RECT 0.560 504.860 779.940 509.300 ;
        RECT 0.860 503.700 779.140 504.860 ;
        RECT 0.560 499.260 779.940 503.700 ;
        RECT 0.860 498.100 779.140 499.260 ;
        RECT 0.560 493.660 779.940 498.100 ;
        RECT 0.860 492.500 779.140 493.660 ;
        RECT 0.560 488.060 779.940 492.500 ;
        RECT 0.860 486.900 779.140 488.060 ;
        RECT 0.560 482.460 779.940 486.900 ;
        RECT 0.860 481.300 779.140 482.460 ;
        RECT 0.560 476.860 779.940 481.300 ;
        RECT 0.860 475.700 779.140 476.860 ;
        RECT 0.560 471.260 779.940 475.700 ;
        RECT 0.860 470.100 779.140 471.260 ;
        RECT 0.560 465.660 779.940 470.100 ;
        RECT 0.860 464.500 779.140 465.660 ;
        RECT 0.560 460.060 779.940 464.500 ;
        RECT 0.860 458.900 779.140 460.060 ;
        RECT 0.560 454.460 779.940 458.900 ;
        RECT 0.860 453.300 779.140 454.460 ;
        RECT 0.560 448.860 779.940 453.300 ;
        RECT 0.860 447.700 779.140 448.860 ;
        RECT 0.560 443.260 779.940 447.700 ;
        RECT 0.860 442.100 779.140 443.260 ;
        RECT 0.560 437.660 779.940 442.100 ;
        RECT 0.860 436.500 779.140 437.660 ;
        RECT 0.560 432.060 779.940 436.500 ;
        RECT 0.860 430.900 779.140 432.060 ;
        RECT 0.560 426.460 779.940 430.900 ;
        RECT 0.860 425.300 779.140 426.460 ;
        RECT 0.560 420.860 779.940 425.300 ;
        RECT 0.860 419.700 779.140 420.860 ;
        RECT 0.560 415.260 779.940 419.700 ;
        RECT 0.860 414.100 779.140 415.260 ;
        RECT 0.560 409.660 779.940 414.100 ;
        RECT 0.860 408.500 779.140 409.660 ;
        RECT 0.560 404.060 779.940 408.500 ;
        RECT 0.860 402.900 779.140 404.060 ;
        RECT 0.560 398.460 779.940 402.900 ;
        RECT 0.860 397.300 779.140 398.460 ;
        RECT 0.560 392.860 779.940 397.300 ;
        RECT 0.860 391.700 779.140 392.860 ;
        RECT 0.560 387.260 779.940 391.700 ;
        RECT 0.860 386.100 779.140 387.260 ;
        RECT 0.560 381.660 779.940 386.100 ;
        RECT 0.860 380.500 779.140 381.660 ;
        RECT 0.560 376.060 779.940 380.500 ;
        RECT 0.860 374.900 779.140 376.060 ;
        RECT 0.560 370.460 779.940 374.900 ;
        RECT 0.860 369.300 779.140 370.460 ;
        RECT 0.560 364.860 779.940 369.300 ;
        RECT 0.860 363.700 779.140 364.860 ;
        RECT 0.560 359.260 779.940 363.700 ;
        RECT 0.860 358.100 779.140 359.260 ;
        RECT 0.560 353.660 779.940 358.100 ;
        RECT 0.860 352.500 779.140 353.660 ;
        RECT 0.560 348.060 779.940 352.500 ;
        RECT 0.860 346.900 779.140 348.060 ;
        RECT 0.560 342.460 779.940 346.900 ;
        RECT 0.860 341.300 779.140 342.460 ;
        RECT 0.560 336.860 779.940 341.300 ;
        RECT 0.860 335.700 779.140 336.860 ;
        RECT 0.560 331.260 779.940 335.700 ;
        RECT 0.860 330.100 779.140 331.260 ;
        RECT 0.560 325.660 779.940 330.100 ;
        RECT 0.860 324.500 779.140 325.660 ;
        RECT 0.560 320.060 779.940 324.500 ;
        RECT 0.860 318.900 779.140 320.060 ;
        RECT 0.560 314.460 779.940 318.900 ;
        RECT 0.860 313.300 779.140 314.460 ;
        RECT 0.560 308.860 779.940 313.300 ;
        RECT 0.860 307.700 779.140 308.860 ;
        RECT 0.560 303.260 779.940 307.700 ;
        RECT 0.860 302.100 779.140 303.260 ;
        RECT 0.560 297.660 779.940 302.100 ;
        RECT 0.860 296.500 779.140 297.660 ;
        RECT 0.560 292.060 779.940 296.500 ;
        RECT 0.860 290.900 779.140 292.060 ;
        RECT 0.560 286.460 779.940 290.900 ;
        RECT 0.860 285.300 779.140 286.460 ;
        RECT 0.560 280.860 779.940 285.300 ;
        RECT 0.860 279.700 779.140 280.860 ;
        RECT 0.560 275.260 779.940 279.700 ;
        RECT 0.860 274.100 779.140 275.260 ;
        RECT 0.560 269.660 779.940 274.100 ;
        RECT 0.860 268.500 779.140 269.660 ;
        RECT 0.560 264.060 779.940 268.500 ;
        RECT 0.860 262.900 779.140 264.060 ;
        RECT 0.560 258.460 779.940 262.900 ;
        RECT 0.860 257.300 779.140 258.460 ;
        RECT 0.560 252.860 779.940 257.300 ;
        RECT 0.860 251.700 779.140 252.860 ;
        RECT 0.560 247.260 779.940 251.700 ;
        RECT 0.860 246.100 779.140 247.260 ;
        RECT 0.560 241.660 779.940 246.100 ;
        RECT 0.860 240.500 779.140 241.660 ;
        RECT 0.560 236.060 779.940 240.500 ;
        RECT 0.860 234.900 779.140 236.060 ;
        RECT 0.560 230.460 779.940 234.900 ;
        RECT 0.860 229.300 779.140 230.460 ;
        RECT 0.560 224.860 779.940 229.300 ;
        RECT 0.860 223.700 779.140 224.860 ;
        RECT 0.560 219.260 779.940 223.700 ;
        RECT 0.860 218.100 779.140 219.260 ;
        RECT 0.560 213.660 779.940 218.100 ;
        RECT 0.860 212.500 779.140 213.660 ;
        RECT 0.560 208.060 779.940 212.500 ;
        RECT 0.860 206.900 779.140 208.060 ;
        RECT 0.560 202.460 779.940 206.900 ;
        RECT 0.860 201.300 779.140 202.460 ;
        RECT 0.560 196.860 779.940 201.300 ;
        RECT 0.860 195.700 779.140 196.860 ;
        RECT 0.560 191.260 779.940 195.700 ;
        RECT 0.860 190.100 779.140 191.260 ;
        RECT 0.560 185.660 779.940 190.100 ;
        RECT 0.860 184.500 779.140 185.660 ;
        RECT 0.560 180.060 779.940 184.500 ;
        RECT 0.860 178.900 779.140 180.060 ;
        RECT 0.560 174.460 779.940 178.900 ;
        RECT 0.860 173.300 779.140 174.460 ;
        RECT 0.560 168.860 779.940 173.300 ;
        RECT 0.860 167.700 779.140 168.860 ;
        RECT 0.560 163.260 779.940 167.700 ;
        RECT 0.860 162.100 779.140 163.260 ;
        RECT 0.560 157.660 779.940 162.100 ;
        RECT 0.860 156.500 779.140 157.660 ;
        RECT 0.560 152.060 779.940 156.500 ;
        RECT 0.860 150.900 779.140 152.060 ;
        RECT 0.560 146.460 779.940 150.900 ;
        RECT 0.860 145.300 779.140 146.460 ;
        RECT 0.560 140.860 779.940 145.300 ;
        RECT 0.860 139.700 779.140 140.860 ;
        RECT 0.560 135.260 779.940 139.700 ;
        RECT 0.860 134.100 779.140 135.260 ;
        RECT 0.560 129.660 779.940 134.100 ;
        RECT 0.860 128.500 779.140 129.660 ;
        RECT 0.560 124.060 779.940 128.500 ;
        RECT 0.860 122.900 779.140 124.060 ;
        RECT 0.560 118.460 779.940 122.900 ;
        RECT 0.860 117.300 779.140 118.460 ;
        RECT 0.560 112.860 779.940 117.300 ;
        RECT 0.860 111.700 779.140 112.860 ;
        RECT 0.560 107.260 779.940 111.700 ;
        RECT 0.860 106.100 779.140 107.260 ;
        RECT 0.560 101.660 779.940 106.100 ;
        RECT 0.860 100.500 779.140 101.660 ;
        RECT 0.560 96.060 779.940 100.500 ;
        RECT 0.860 94.900 779.140 96.060 ;
        RECT 0.560 90.460 779.940 94.900 ;
        RECT 0.860 89.300 779.140 90.460 ;
        RECT 0.560 84.860 779.940 89.300 ;
        RECT 0.860 83.700 779.140 84.860 ;
        RECT 0.560 79.260 779.940 83.700 ;
        RECT 0.860 78.100 779.140 79.260 ;
        RECT 0.560 73.660 779.940 78.100 ;
        RECT 0.860 72.500 779.140 73.660 ;
        RECT 0.560 68.060 779.940 72.500 ;
        RECT 0.860 66.900 779.140 68.060 ;
        RECT 0.560 62.460 779.940 66.900 ;
        RECT 0.860 61.300 779.140 62.460 ;
        RECT 0.560 56.860 779.940 61.300 ;
        RECT 0.860 55.700 779.140 56.860 ;
        RECT 0.560 51.260 779.940 55.700 ;
        RECT 0.860 50.100 779.140 51.260 ;
        RECT 0.560 45.660 779.940 50.100 ;
        RECT 0.860 44.500 779.140 45.660 ;
        RECT 0.560 40.060 779.940 44.500 ;
        RECT 0.860 38.900 779.140 40.060 ;
        RECT 0.560 34.460 779.940 38.900 ;
        RECT 0.860 33.300 779.140 34.460 ;
        RECT 0.560 28.860 779.940 33.300 ;
        RECT 0.860 27.700 779.140 28.860 ;
        RECT 0.560 23.260 779.940 27.700 ;
        RECT 0.860 22.100 779.140 23.260 ;
        RECT 0.560 17.660 779.940 22.100 ;
        RECT 0.860 16.500 779.140 17.660 ;
        RECT 0.560 12.060 779.940 16.500 ;
        RECT 0.860 10.900 779.140 12.060 ;
        RECT 0.560 0.700 779.940 10.900 ;
      LAYER Metal4 ;
        RECT 0.140 11.160 23.600 766.550 ;
        RECT 29.200 11.160 29.600 766.550 ;
        RECT 35.200 605.790 98.600 766.550 ;
        RECT 104.200 605.790 104.600 766.550 ;
        RECT 110.200 605.790 173.600 766.550 ;
        RECT 179.200 605.790 179.600 766.550 ;
        RECT 185.200 605.790 248.600 766.550 ;
        RECT 254.200 605.790 254.600 766.550 ;
        RECT 260.200 605.790 323.600 766.550 ;
        RECT 329.200 605.790 329.600 766.550 ;
        RECT 335.200 605.790 398.600 766.550 ;
        RECT 404.200 605.790 404.600 766.550 ;
        RECT 410.200 605.790 473.600 766.550 ;
        RECT 479.200 605.790 479.600 766.550 ;
        RECT 485.200 605.790 548.600 766.550 ;
        RECT 554.200 605.790 554.600 766.550 ;
        RECT 560.200 605.790 623.600 766.550 ;
        RECT 629.200 605.790 629.600 766.550 ;
        RECT 635.200 605.790 698.600 766.550 ;
        RECT 704.200 605.790 704.600 766.550 ;
        RECT 710.200 612.120 779.380 766.550 ;
        RECT 710.200 605.790 735.560 612.120 ;
        RECT 35.200 70.020 735.560 605.790 ;
        RECT 35.200 11.160 98.600 70.020 ;
        RECT 104.200 11.160 104.600 70.020 ;
        RECT 110.200 11.160 173.600 70.020 ;
        RECT 179.200 11.160 179.600 70.020 ;
        RECT 185.200 11.160 248.600 70.020 ;
        RECT 254.200 11.160 254.600 70.020 ;
        RECT 260.200 11.160 323.600 70.020 ;
        RECT 329.200 11.160 329.600 70.020 ;
        RECT 335.200 11.160 398.600 70.020 ;
        RECT 404.200 11.160 404.600 70.020 ;
        RECT 410.200 11.160 473.600 70.020 ;
        RECT 479.200 11.160 479.600 70.020 ;
        RECT 485.200 11.160 548.600 70.020 ;
        RECT 554.200 11.160 554.600 70.020 ;
        RECT 560.200 11.160 623.600 70.020 ;
        RECT 629.200 11.160 629.600 70.020 ;
        RECT 635.200 11.160 698.600 70.020 ;
        RECT 704.200 11.160 704.600 70.020 ;
        RECT 710.200 62.120 735.560 70.020 ;
        RECT 741.160 62.120 741.720 612.120 ;
        RECT 747.320 62.120 779.380 612.120 ;
        RECT 710.200 11.160 779.380 62.120 ;
        RECT 0.140 4.760 779.380 11.160 ;
      LAYER Metal5 ;
        RECT 6.220 712.510 763.220 762.070 ;
        RECT 6.220 700.310 9.480 712.510 ;
        RECT 6.220 637.510 763.220 700.310 ;
        RECT 6.220 625.310 9.480 637.510 ;
        RECT 6.220 562.510 763.220 625.310 ;
        RECT 6.220 550.310 9.480 562.510 ;
        RECT 6.220 487.510 763.220 550.310 ;
        RECT 6.220 475.310 9.480 487.510 ;
        RECT 6.220 412.510 763.220 475.310 ;
        RECT 6.220 400.310 9.480 412.510 ;
        RECT 6.220 337.510 763.220 400.310 ;
        RECT 6.220 325.310 9.480 337.510 ;
        RECT 6.220 262.510 763.220 325.310 ;
        RECT 6.220 250.310 9.480 262.510 ;
        RECT 6.220 187.510 763.220 250.310 ;
        RECT 6.220 175.310 9.480 187.510 ;
        RECT 6.220 112.510 763.220 175.310 ;
        RECT 6.220 100.310 9.480 112.510 ;
        RECT 6.220 37.510 763.220 100.310 ;
        RECT 6.220 25.310 9.480 37.510 ;
        RECT 6.220 4.730 763.220 25.310 ;
  END
END mesh_tile
END LIBRARY

